VERSION 5.8 ;
BUSBITCHARS "[]" ;
DIVIDERCHAR "/" ;
UNITS
    DATABASE MICRONS 1000 ;
END UNITS

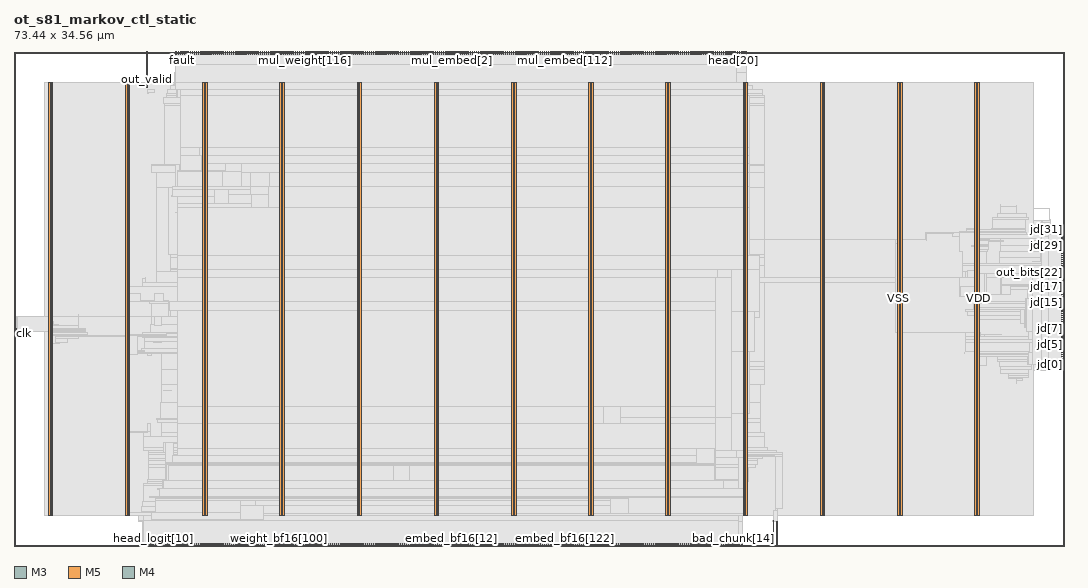
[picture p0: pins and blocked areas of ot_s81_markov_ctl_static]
MACRO ot_s81_markov_ctl_static
  FOREIGN ot_s81_markov_ctl_static 0 0 ;
  CLASS BLOCK ;
  SIZE 73.44 BY 34.56 ;
  PIN bad_chunk[0]
    DIRECTION INPUT ;
    USE SIGNAL ;
    PORT
      LAYER M3 ;
        RECT  49.32 0 49.338 0.144 ;
    END
  END bad_chunk[0]
  PIN bad_chunk[10]
    DIRECTION INPUT ;
    USE SIGNAL ;
    PORT
      LAYER M3 ;
        RECT  50.04 0 50.058 0.144 ;
    END
  END bad_chunk[10]
  PIN bad_chunk[11]
    DIRECTION INPUT ;
    USE SIGNAL ;
    PORT
      LAYER M5 ;
        RECT  50.064 0 50.088 0.192 ;
    END
  END bad_chunk[11]
  PIN bad_chunk[12]
    DIRECTION INPUT ;
    USE SIGNAL ;
    PORT
      LAYER M3 ;
        RECT  50.184 0 50.202 0.144 ;
    END
  END bad_chunk[12]
  PIN bad_chunk[13]
    DIRECTION INPUT ;
    USE SIGNAL ;
    PORT
      LAYER M5 ;
        RECT  50.208 0 50.232 0.192 ;
    END
  END bad_chunk[13]
  PIN bad_chunk[14]
    DIRECTION INPUT ;
    USE SIGNAL ;
    PORT
      LAYER M3 ;
        RECT  50.328 0 50.346 0.144 ;
    END
  END bad_chunk[14]
  PIN bad_chunk[15]
    DIRECTION INPUT ;
    USE SIGNAL ;
    PORT
      LAYER M5 ;
        RECT  50.352 0 50.376 0.192 ;
    END
  END bad_chunk[15]
  PIN bad_chunk[1]
    DIRECTION INPUT ;
    USE SIGNAL ;
    PORT
      LAYER M5 ;
        RECT  49.344 0 49.368 0.192 ;
    END
  END bad_chunk[1]
  PIN bad_chunk[2]
    DIRECTION INPUT ;
    USE SIGNAL ;
    PORT
      LAYER M3 ;
        RECT  49.464 0 49.482 0.144 ;
    END
  END bad_chunk[2]
  PIN bad_chunk[3]
    DIRECTION INPUT ;
    USE SIGNAL ;
    PORT
      LAYER M5 ;
        RECT  49.488 0 49.512 0.192 ;
    END
  END bad_chunk[3]
  PIN bad_chunk[4]
    DIRECTION INPUT ;
    USE SIGNAL ;
    PORT
      LAYER M3 ;
        RECT  49.608 0 49.626 0.144 ;
    END
  END bad_chunk[4]
  PIN bad_chunk[5]
    DIRECTION INPUT ;
    USE SIGNAL ;
    PORT
      LAYER M5 ;
        RECT  49.632 0 49.656 0.192 ;
    END
  END bad_chunk[5]
  PIN bad_chunk[6]
    DIRECTION INPUT ;
    USE SIGNAL ;
    PORT
      LAYER M3 ;
        RECT  49.752 0 49.77 0.144 ;
    END
  END bad_chunk[6]
  PIN bad_chunk[7]
    DIRECTION INPUT ;
    USE SIGNAL ;
    PORT
      LAYER M5 ;
        RECT  49.776 0 49.8 0.192 ;
    END
  END bad_chunk[7]
  PIN bad_chunk[8]
    DIRECTION INPUT ;
    USE SIGNAL ;
    PORT
      LAYER M3 ;
        RECT  49.896 0 49.914 0.144 ;
    END
  END bad_chunk[8]
  PIN bad_chunk[9]
    DIRECTION INPUT ;
    USE SIGNAL ;
    PORT
      LAYER M5 ;
        RECT  49.92 0 49.944 0.192 ;
    END
  END bad_chunk[9]
  PIN bad_tree[0]
    DIRECTION INPUT ;
    USE SIGNAL ;
    PORT
      LAYER M3 ;
        RECT  50.472 0 50.49 0.144 ;
    END
  END bad_tree[0]
  PIN bad_tree[1]
    DIRECTION INPUT ;
    USE SIGNAL ;
    PORT
      LAYER M5 ;
        RECT  50.496 0 50.52 0.192 ;
    END
  END bad_tree[1]
  PIN bad_tree[2]
    DIRECTION INPUT ;
    USE SIGNAL ;
    PORT
      LAYER M3 ;
        RECT  50.616 0 50.634 0.144 ;
    END
  END bad_tree[2]
  PIN bad_tree[3]
    DIRECTION INPUT ;
    USE SIGNAL ;
    PORT
      LAYER M5 ;
        RECT  50.64 0 50.664 0.192 ;
    END
  END bad_tree[3]
  PIN bad_tree[4]
    DIRECTION INPUT ;
    USE SIGNAL ;
    PORT
      LAYER M3 ;
        RECT  50.76 0 50.778 0.144 ;
    END
  END bad_tree[4]
  PIN clk
    DIRECTION INPUT ;
    USE SIGNAL ;
    PORT
      LAYER M4 ;
        RECT  0 14.88 0.192 14.904 ;
    END
  END clk
  PIN embed_bf16[0]
    DIRECTION INPUT ;
    USE SIGNAL ;
    PORT
      LAYER M3 ;
        RECT  29.736 0 29.754 0.144 ;
    END
  END embed_bf16[0]
  PIN embed_bf16[100]
    DIRECTION INPUT ;
    USE SIGNAL ;
    PORT
      LAYER M3 ;
        RECT  36.936 0 36.954 0.144 ;
    END
  END embed_bf16[100]
  PIN embed_bf16[101]
    DIRECTION INPUT ;
    USE SIGNAL ;
    PORT
      LAYER M5 ;
        RECT  36.96 0 36.984 0.192 ;
    END
  END embed_bf16[101]
  PIN embed_bf16[102]
    DIRECTION INPUT ;
    USE SIGNAL ;
    PORT
      LAYER M3 ;
        RECT  37.08 0 37.098 0.144 ;
    END
  END embed_bf16[102]
  PIN embed_bf16[103]
    DIRECTION INPUT ;
    USE SIGNAL ;
    PORT
      LAYER M5 ;
        RECT  37.104 0 37.128 0.192 ;
    END
  END embed_bf16[103]
  PIN embed_bf16[104]
    DIRECTION INPUT ;
    USE SIGNAL ;
    PORT
      LAYER M3 ;
        RECT  37.224 0 37.242 0.144 ;
    END
  END embed_bf16[104]
  PIN embed_bf16[105]
    DIRECTION INPUT ;
    USE SIGNAL ;
    PORT
      LAYER M5 ;
        RECT  37.248 0 37.272 0.192 ;
    END
  END embed_bf16[105]
  PIN embed_bf16[106]
    DIRECTION INPUT ;
    USE SIGNAL ;
    PORT
      LAYER M3 ;
        RECT  37.368 0 37.386 0.144 ;
    END
  END embed_bf16[106]
  PIN embed_bf16[107]
    DIRECTION INPUT ;
    USE SIGNAL ;
    PORT
      LAYER M5 ;
        RECT  37.392 0 37.416 0.192 ;
    END
  END embed_bf16[107]
  PIN embed_bf16[108]
    DIRECTION INPUT ;
    USE SIGNAL ;
    PORT
      LAYER M3 ;
        RECT  37.512 0 37.53 0.144 ;
    END
  END embed_bf16[108]
  PIN embed_bf16[109]
    DIRECTION INPUT ;
    USE SIGNAL ;
    PORT
      LAYER M5 ;
        RECT  37.536 0 37.56 0.192 ;
    END
  END embed_bf16[109]
  PIN embed_bf16[10]
    DIRECTION INPUT ;
    USE SIGNAL ;
    PORT
      LAYER M3 ;
        RECT  30.456 0 30.474 0.144 ;
    END
  END embed_bf16[10]
  PIN embed_bf16[110]
    DIRECTION INPUT ;
    USE SIGNAL ;
    PORT
      LAYER M3 ;
        RECT  37.656 0 37.674 0.144 ;
    END
  END embed_bf16[110]
  PIN embed_bf16[111]
    DIRECTION INPUT ;
    USE SIGNAL ;
    PORT
      LAYER M5 ;
        RECT  37.68 0 37.704 0.192 ;
    END
  END embed_bf16[111]
  PIN embed_bf16[112]
    DIRECTION INPUT ;
    USE SIGNAL ;
    PORT
      LAYER M3 ;
        RECT  37.8 0 37.818 0.144 ;
    END
  END embed_bf16[112]
  PIN embed_bf16[113]
    DIRECTION INPUT ;
    USE SIGNAL ;
    PORT
      LAYER M5 ;
        RECT  37.824 0 37.848 0.192 ;
    END
  END embed_bf16[113]
  PIN embed_bf16[114]
    DIRECTION INPUT ;
    USE SIGNAL ;
    PORT
      LAYER M3 ;
        RECT  37.944 0 37.962 0.144 ;
    END
  END embed_bf16[114]
  PIN embed_bf16[115]
    DIRECTION INPUT ;
    USE SIGNAL ;
    PORT
      LAYER M5 ;
        RECT  37.968 0 37.992 0.192 ;
    END
  END embed_bf16[115]
  PIN embed_bf16[116]
    DIRECTION INPUT ;
    USE SIGNAL ;
    PORT
      LAYER M3 ;
        RECT  38.088 0 38.106 0.144 ;
    END
  END embed_bf16[116]
  PIN embed_bf16[117]
    DIRECTION INPUT ;
    USE SIGNAL ;
    PORT
      LAYER M5 ;
        RECT  38.112 0 38.136 0.192 ;
    END
  END embed_bf16[117]
  PIN embed_bf16[118]
    DIRECTION INPUT ;
    USE SIGNAL ;
    PORT
      LAYER M3 ;
        RECT  38.232 0 38.25 0.144 ;
    END
  END embed_bf16[118]
  PIN embed_bf16[119]
    DIRECTION INPUT ;
    USE SIGNAL ;
    PORT
      LAYER M5 ;
        RECT  38.256 0 38.28 0.192 ;
    END
  END embed_bf16[119]
  PIN embed_bf16[11]
    DIRECTION INPUT ;
    USE SIGNAL ;
    PORT
      LAYER M5 ;
        RECT  30.48 0 30.504 0.192 ;
    END
  END embed_bf16[11]
  PIN embed_bf16[120]
    DIRECTION INPUT ;
    USE SIGNAL ;
    PORT
      LAYER M3 ;
        RECT  38.376 0 38.394 0.144 ;
    END
  END embed_bf16[120]
  PIN embed_bf16[121]
    DIRECTION INPUT ;
    USE SIGNAL ;
    PORT
      LAYER M5 ;
        RECT  38.4 0 38.424 0.192 ;
    END
  END embed_bf16[121]
  PIN embed_bf16[122]
    DIRECTION INPUT ;
    USE SIGNAL ;
    PORT
      LAYER M3 ;
        RECT  38.52 0 38.538 0.144 ;
    END
  END embed_bf16[122]
  PIN embed_bf16[123]
    DIRECTION INPUT ;
    USE SIGNAL ;
    PORT
      LAYER M5 ;
        RECT  38.544 0 38.568 0.192 ;
    END
  END embed_bf16[123]
  PIN embed_bf16[124]
    DIRECTION INPUT ;
    USE SIGNAL ;
    PORT
      LAYER M3 ;
        RECT  38.664 0 38.682 0.144 ;
    END
  END embed_bf16[124]
  PIN embed_bf16[125]
    DIRECTION INPUT ;
    USE SIGNAL ;
    PORT
      LAYER M5 ;
        RECT  38.688 0 38.712 0.192 ;
    END
  END embed_bf16[125]
  PIN embed_bf16[126]
    DIRECTION INPUT ;
    USE SIGNAL ;
    PORT
      LAYER M3 ;
        RECT  38.808 0 38.826 0.144 ;
    END
  END embed_bf16[126]
  PIN embed_bf16[127]
    DIRECTION INPUT ;
    USE SIGNAL ;
    PORT
      LAYER M5 ;
        RECT  38.832 0 38.856 0.192 ;
    END
  END embed_bf16[127]
  PIN embed_bf16[128]
    DIRECTION INPUT ;
    USE SIGNAL ;
    PORT
      LAYER M3 ;
        RECT  38.952 0 38.97 0.144 ;
    END
  END embed_bf16[128]
  PIN embed_bf16[129]
    DIRECTION INPUT ;
    USE SIGNAL ;
    PORT
      LAYER M5 ;
        RECT  38.976 0 39 0.192 ;
    END
  END embed_bf16[129]
  PIN embed_bf16[12]
    DIRECTION INPUT ;
    USE SIGNAL ;
    PORT
      LAYER M3 ;
        RECT  30.6 0 30.618 0.144 ;
    END
  END embed_bf16[12]
  PIN embed_bf16[130]
    DIRECTION INPUT ;
    USE SIGNAL ;
    PORT
      LAYER M3 ;
        RECT  39.096 0 39.114 0.144 ;
    END
  END embed_bf16[130]
  PIN embed_bf16[131]
    DIRECTION INPUT ;
    USE SIGNAL ;
    PORT
      LAYER M5 ;
        RECT  39.12 0 39.144 0.192 ;
    END
  END embed_bf16[131]
  PIN embed_bf16[132]
    DIRECTION INPUT ;
    USE SIGNAL ;
    PORT
      LAYER M3 ;
        RECT  39.24 0 39.258 0.144 ;
    END
  END embed_bf16[132]
  PIN embed_bf16[133]
    DIRECTION INPUT ;
    USE SIGNAL ;
    PORT
      LAYER M5 ;
        RECT  39.264 0 39.288 0.192 ;
    END
  END embed_bf16[133]
  PIN embed_bf16[134]
    DIRECTION INPUT ;
    USE SIGNAL ;
    PORT
      LAYER M3 ;
        RECT  39.384 0 39.402 0.144 ;
    END
  END embed_bf16[134]
  PIN embed_bf16[135]
    DIRECTION INPUT ;
    USE SIGNAL ;
    PORT
      LAYER M5 ;
        RECT  39.408 0 39.432 0.192 ;
    END
  END embed_bf16[135]
  PIN embed_bf16[136]
    DIRECTION INPUT ;
    USE SIGNAL ;
    PORT
      LAYER M3 ;
        RECT  39.528 0 39.546 0.144 ;
    END
  END embed_bf16[136]
  PIN embed_bf16[137]
    DIRECTION INPUT ;
    USE SIGNAL ;
    PORT
      LAYER M5 ;
        RECT  39.552 0 39.576 0.192 ;
    END
  END embed_bf16[137]
  PIN embed_bf16[138]
    DIRECTION INPUT ;
    USE SIGNAL ;
    PORT
      LAYER M3 ;
        RECT  39.672 0 39.69 0.144 ;
    END
  END embed_bf16[138]
  PIN embed_bf16[139]
    DIRECTION INPUT ;
    USE SIGNAL ;
    PORT
      LAYER M5 ;
        RECT  39.696 0 39.72 0.192 ;
    END
  END embed_bf16[139]
  PIN embed_bf16[13]
    DIRECTION INPUT ;
    USE SIGNAL ;
    PORT
      LAYER M5 ;
        RECT  30.624 0 30.648 0.192 ;
    END
  END embed_bf16[13]
  PIN embed_bf16[140]
    DIRECTION INPUT ;
    USE SIGNAL ;
    PORT
      LAYER M3 ;
        RECT  39.816 0 39.834 0.144 ;
    END
  END embed_bf16[140]
  PIN embed_bf16[141]
    DIRECTION INPUT ;
    USE SIGNAL ;
    PORT
      LAYER M5 ;
        RECT  39.84 0 39.864 0.192 ;
    END
  END embed_bf16[141]
  PIN embed_bf16[142]
    DIRECTION INPUT ;
    USE SIGNAL ;
    PORT
      LAYER M3 ;
        RECT  39.96 0 39.978 0.144 ;
    END
  END embed_bf16[142]
  PIN embed_bf16[143]
    DIRECTION INPUT ;
    USE SIGNAL ;
    PORT
      LAYER M5 ;
        RECT  39.984 0 40.008 0.192 ;
    END
  END embed_bf16[143]
  PIN embed_bf16[144]
    DIRECTION INPUT ;
    USE SIGNAL ;
    PORT
      LAYER M3 ;
        RECT  40.104 0 40.122 0.144 ;
    END
  END embed_bf16[144]
  PIN embed_bf16[145]
    DIRECTION INPUT ;
    USE SIGNAL ;
    PORT
      LAYER M5 ;
        RECT  40.128 0 40.152 0.192 ;
    END
  END embed_bf16[145]
  PIN embed_bf16[146]
    DIRECTION INPUT ;
    USE SIGNAL ;
    PORT
      LAYER M3 ;
        RECT  40.248 0 40.266 0.144 ;
    END
  END embed_bf16[146]
  PIN embed_bf16[147]
    DIRECTION INPUT ;
    USE SIGNAL ;
    PORT
      LAYER M5 ;
        RECT  40.272 0 40.296 0.192 ;
    END
  END embed_bf16[147]
  PIN embed_bf16[148]
    DIRECTION INPUT ;
    USE SIGNAL ;
    PORT
      LAYER M3 ;
        RECT  40.392 0 40.41 0.144 ;
    END
  END embed_bf16[148]
  PIN embed_bf16[149]
    DIRECTION INPUT ;
    USE SIGNAL ;
    PORT
      LAYER M5 ;
        RECT  40.416 0 40.44 0.192 ;
    END
  END embed_bf16[149]
  PIN embed_bf16[14]
    DIRECTION INPUT ;
    USE SIGNAL ;
    PORT
      LAYER M3 ;
        RECT  30.744 0 30.762 0.144 ;
    END
  END embed_bf16[14]
  PIN embed_bf16[150]
    DIRECTION INPUT ;
    USE SIGNAL ;
    PORT
      LAYER M3 ;
        RECT  40.536 0 40.554 0.144 ;
    END
  END embed_bf16[150]
  PIN embed_bf16[151]
    DIRECTION INPUT ;
    USE SIGNAL ;
    PORT
      LAYER M5 ;
        RECT  40.56 0 40.584 0.192 ;
    END
  END embed_bf16[151]
  PIN embed_bf16[152]
    DIRECTION INPUT ;
    USE SIGNAL ;
    PORT
      LAYER M3 ;
        RECT  40.68 0 40.698 0.144 ;
    END
  END embed_bf16[152]
  PIN embed_bf16[153]
    DIRECTION INPUT ;
    USE SIGNAL ;
    PORT
      LAYER M5 ;
        RECT  40.704 0 40.728 0.192 ;
    END
  END embed_bf16[153]
  PIN embed_bf16[154]
    DIRECTION INPUT ;
    USE SIGNAL ;
    PORT
      LAYER M3 ;
        RECT  40.824 0 40.842 0.144 ;
    END
  END embed_bf16[154]
  PIN embed_bf16[155]
    DIRECTION INPUT ;
    USE SIGNAL ;
    PORT
      LAYER M5 ;
        RECT  40.848 0 40.872 0.192 ;
    END
  END embed_bf16[155]
  PIN embed_bf16[156]
    DIRECTION INPUT ;
    USE SIGNAL ;
    PORT
      LAYER M3 ;
        RECT  40.968 0 40.986 0.144 ;
    END
  END embed_bf16[156]
  PIN embed_bf16[157]
    DIRECTION INPUT ;
    USE SIGNAL ;
    PORT
      LAYER M5 ;
        RECT  40.992 0 41.016 0.192 ;
    END
  END embed_bf16[157]
  PIN embed_bf16[158]
    DIRECTION INPUT ;
    USE SIGNAL ;
    PORT
      LAYER M3 ;
        RECT  41.112 0 41.13 0.144 ;
    END
  END embed_bf16[158]
  PIN embed_bf16[159]
    DIRECTION INPUT ;
    USE SIGNAL ;
    PORT
      LAYER M5 ;
        RECT  41.136 0 41.16 0.192 ;
    END
  END embed_bf16[159]
  PIN embed_bf16[15]
    DIRECTION INPUT ;
    USE SIGNAL ;
    PORT
      LAYER M5 ;
        RECT  30.768 0 30.792 0.192 ;
    END
  END embed_bf16[15]
  PIN embed_bf16[160]
    DIRECTION INPUT ;
    USE SIGNAL ;
    PORT
      LAYER M3 ;
        RECT  41.256 0 41.274 0.144 ;
    END
  END embed_bf16[160]
  PIN embed_bf16[161]
    DIRECTION INPUT ;
    USE SIGNAL ;
    PORT
      LAYER M5 ;
        RECT  41.28 0 41.304 0.192 ;
    END
  END embed_bf16[161]
  PIN embed_bf16[162]
    DIRECTION INPUT ;
    USE SIGNAL ;
    PORT
      LAYER M3 ;
        RECT  41.4 0 41.418 0.144 ;
    END
  END embed_bf16[162]
  PIN embed_bf16[163]
    DIRECTION INPUT ;
    USE SIGNAL ;
    PORT
      LAYER M5 ;
        RECT  41.424 0 41.448 0.192 ;
    END
  END embed_bf16[163]
  PIN embed_bf16[164]
    DIRECTION INPUT ;
    USE SIGNAL ;
    PORT
      LAYER M3 ;
        RECT  41.544 0 41.562 0.144 ;
    END
  END embed_bf16[164]
  PIN embed_bf16[165]
    DIRECTION INPUT ;
    USE SIGNAL ;
    PORT
      LAYER M5 ;
        RECT  41.568 0 41.592 0.192 ;
    END
  END embed_bf16[165]
  PIN embed_bf16[166]
    DIRECTION INPUT ;
    USE SIGNAL ;
    PORT
      LAYER M3 ;
        RECT  41.688 0 41.706 0.144 ;
    END
  END embed_bf16[166]
  PIN embed_bf16[167]
    DIRECTION INPUT ;
    USE SIGNAL ;
    PORT
      LAYER M5 ;
        RECT  41.712 0 41.736 0.192 ;
    END
  END embed_bf16[167]
  PIN embed_bf16[168]
    DIRECTION INPUT ;
    USE SIGNAL ;
    PORT
      LAYER M3 ;
        RECT  41.832 0 41.85 0.144 ;
    END
  END embed_bf16[168]
  PIN embed_bf16[169]
    DIRECTION INPUT ;
    USE SIGNAL ;
    PORT
      LAYER M5 ;
        RECT  41.856 0 41.88 0.192 ;
    END
  END embed_bf16[169]
  PIN embed_bf16[16]
    DIRECTION INPUT ;
    USE SIGNAL ;
    PORT
      LAYER M3 ;
        RECT  30.888 0 30.906 0.144 ;
    END
  END embed_bf16[16]
  PIN embed_bf16[170]
    DIRECTION INPUT ;
    USE SIGNAL ;
    PORT
      LAYER M3 ;
        RECT  41.976 0 41.994 0.144 ;
    END
  END embed_bf16[170]
  PIN embed_bf16[171]
    DIRECTION INPUT ;
    USE SIGNAL ;
    PORT
      LAYER M5 ;
        RECT  42 0 42.024 0.192 ;
    END
  END embed_bf16[171]
  PIN embed_bf16[172]
    DIRECTION INPUT ;
    USE SIGNAL ;
    PORT
      LAYER M3 ;
        RECT  42.12 0 42.138 0.144 ;
    END
  END embed_bf16[172]
  PIN embed_bf16[173]
    DIRECTION INPUT ;
    USE SIGNAL ;
    PORT
      LAYER M5 ;
        RECT  42.144 0 42.168 0.192 ;
    END
  END embed_bf16[173]
  PIN embed_bf16[174]
    DIRECTION INPUT ;
    USE SIGNAL ;
    PORT
      LAYER M3 ;
        RECT  42.264 0 42.282 0.144 ;
    END
  END embed_bf16[174]
  PIN embed_bf16[175]
    DIRECTION INPUT ;
    USE SIGNAL ;
    PORT
      LAYER M5 ;
        RECT  42.288 0 42.312 0.192 ;
    END
  END embed_bf16[175]
  PIN embed_bf16[176]
    DIRECTION INPUT ;
    USE SIGNAL ;
    PORT
      LAYER M3 ;
        RECT  42.408 0 42.426 0.144 ;
    END
  END embed_bf16[176]
  PIN embed_bf16[177]
    DIRECTION INPUT ;
    USE SIGNAL ;
    PORT
      LAYER M5 ;
        RECT  42.432 0 42.456 0.192 ;
    END
  END embed_bf16[177]
  PIN embed_bf16[178]
    DIRECTION INPUT ;
    USE SIGNAL ;
    PORT
      LAYER M3 ;
        RECT  42.552 0 42.57 0.144 ;
    END
  END embed_bf16[178]
  PIN embed_bf16[179]
    DIRECTION INPUT ;
    USE SIGNAL ;
    PORT
      LAYER M5 ;
        RECT  42.576 0 42.6 0.192 ;
    END
  END embed_bf16[179]
  PIN embed_bf16[17]
    DIRECTION INPUT ;
    USE SIGNAL ;
    PORT
      LAYER M5 ;
        RECT  30.912 0 30.936 0.192 ;
    END
  END embed_bf16[17]
  PIN embed_bf16[180]
    DIRECTION INPUT ;
    USE SIGNAL ;
    PORT
      LAYER M3 ;
        RECT  42.696 0 42.714 0.144 ;
    END
  END embed_bf16[180]
  PIN embed_bf16[181]
    DIRECTION INPUT ;
    USE SIGNAL ;
    PORT
      LAYER M5 ;
        RECT  42.72 0 42.744 0.192 ;
    END
  END embed_bf16[181]
  PIN embed_bf16[182]
    DIRECTION INPUT ;
    USE SIGNAL ;
    PORT
      LAYER M3 ;
        RECT  42.84 0 42.858 0.144 ;
    END
  END embed_bf16[182]
  PIN embed_bf16[183]
    DIRECTION INPUT ;
    USE SIGNAL ;
    PORT
      LAYER M5 ;
        RECT  42.864 0 42.888 0.192 ;
    END
  END embed_bf16[183]
  PIN embed_bf16[184]
    DIRECTION INPUT ;
    USE SIGNAL ;
    PORT
      LAYER M3 ;
        RECT  42.984 0 43.002 0.144 ;
    END
  END embed_bf16[184]
  PIN embed_bf16[185]
    DIRECTION INPUT ;
    USE SIGNAL ;
    PORT
      LAYER M5 ;
        RECT  43.008 0 43.032 0.192 ;
    END
  END embed_bf16[185]
  PIN embed_bf16[186]
    DIRECTION INPUT ;
    USE SIGNAL ;
    PORT
      LAYER M3 ;
        RECT  43.128 0 43.146 0.144 ;
    END
  END embed_bf16[186]
  PIN embed_bf16[187]
    DIRECTION INPUT ;
    USE SIGNAL ;
    PORT
      LAYER M5 ;
        RECT  43.152 0 43.176 0.192 ;
    END
  END embed_bf16[187]
  PIN embed_bf16[188]
    DIRECTION INPUT ;
    USE SIGNAL ;
    PORT
      LAYER M3 ;
        RECT  43.272 0 43.29 0.144 ;
    END
  END embed_bf16[188]
  PIN embed_bf16[189]
    DIRECTION INPUT ;
    USE SIGNAL ;
    PORT
      LAYER M5 ;
        RECT  43.296 0 43.32 0.192 ;
    END
  END embed_bf16[189]
  PIN embed_bf16[18]
    DIRECTION INPUT ;
    USE SIGNAL ;
    PORT
      LAYER M3 ;
        RECT  31.032 0 31.05 0.144 ;
    END
  END embed_bf16[18]
  PIN embed_bf16[190]
    DIRECTION INPUT ;
    USE SIGNAL ;
    PORT
      LAYER M3 ;
        RECT  43.416 0 43.434 0.144 ;
    END
  END embed_bf16[190]
  PIN embed_bf16[191]
    DIRECTION INPUT ;
    USE SIGNAL ;
    PORT
      LAYER M5 ;
        RECT  43.44 0 43.464 0.192 ;
    END
  END embed_bf16[191]
  PIN embed_bf16[192]
    DIRECTION INPUT ;
    USE SIGNAL ;
    PORT
      LAYER M3 ;
        RECT  43.56 0 43.578 0.144 ;
    END
  END embed_bf16[192]
  PIN embed_bf16[193]
    DIRECTION INPUT ;
    USE SIGNAL ;
    PORT
      LAYER M5 ;
        RECT  43.584 0 43.608 0.192 ;
    END
  END embed_bf16[193]
  PIN embed_bf16[194]
    DIRECTION INPUT ;
    USE SIGNAL ;
    PORT
      LAYER M3 ;
        RECT  43.704 0 43.722 0.144 ;
    END
  END embed_bf16[194]
  PIN embed_bf16[195]
    DIRECTION INPUT ;
    USE SIGNAL ;
    PORT
      LAYER M5 ;
        RECT  43.728 0 43.752 0.192 ;
    END
  END embed_bf16[195]
  PIN embed_bf16[196]
    DIRECTION INPUT ;
    USE SIGNAL ;
    PORT
      LAYER M3 ;
        RECT  43.848 0 43.866 0.144 ;
    END
  END embed_bf16[196]
  PIN embed_bf16[197]
    DIRECTION INPUT ;
    USE SIGNAL ;
    PORT
      LAYER M5 ;
        RECT  43.872 0 43.896 0.192 ;
    END
  END embed_bf16[197]
  PIN embed_bf16[198]
    DIRECTION INPUT ;
    USE SIGNAL ;
    PORT
      LAYER M3 ;
        RECT  43.992 0 44.01 0.144 ;
    END
  END embed_bf16[198]
  PIN embed_bf16[199]
    DIRECTION INPUT ;
    USE SIGNAL ;
    PORT
      LAYER M5 ;
        RECT  44.016 0 44.04 0.192 ;
    END
  END embed_bf16[199]
  PIN embed_bf16[19]
    DIRECTION INPUT ;
    USE SIGNAL ;
    PORT
      LAYER M5 ;
        RECT  31.056 0 31.08 0.192 ;
    END
  END embed_bf16[19]
  PIN embed_bf16[1]
    DIRECTION INPUT ;
    USE SIGNAL ;
    PORT
      LAYER M5 ;
        RECT  29.76 0 29.784 0.192 ;
    END
  END embed_bf16[1]
  PIN embed_bf16[200]
    DIRECTION INPUT ;
    USE SIGNAL ;
    PORT
      LAYER M3 ;
        RECT  44.136 0 44.154 0.144 ;
    END
  END embed_bf16[200]
  PIN embed_bf16[201]
    DIRECTION INPUT ;
    USE SIGNAL ;
    PORT
      LAYER M5 ;
        RECT  44.16 0 44.184 0.192 ;
    END
  END embed_bf16[201]
  PIN embed_bf16[202]
    DIRECTION INPUT ;
    USE SIGNAL ;
    PORT
      LAYER M3 ;
        RECT  44.28 0 44.298 0.144 ;
    END
  END embed_bf16[202]
  PIN embed_bf16[203]
    DIRECTION INPUT ;
    USE SIGNAL ;
    PORT
      LAYER M5 ;
        RECT  44.304 0 44.328 0.192 ;
    END
  END embed_bf16[203]
  PIN embed_bf16[204]
    DIRECTION INPUT ;
    USE SIGNAL ;
    PORT
      LAYER M3 ;
        RECT  44.424 0 44.442 0.144 ;
    END
  END embed_bf16[204]
  PIN embed_bf16[205]
    DIRECTION INPUT ;
    USE SIGNAL ;
    PORT
      LAYER M5 ;
        RECT  44.448 0 44.472 0.192 ;
    END
  END embed_bf16[205]
  PIN embed_bf16[206]
    DIRECTION INPUT ;
    USE SIGNAL ;
    PORT
      LAYER M3 ;
        RECT  44.568 0 44.586 0.144 ;
    END
  END embed_bf16[206]
  PIN embed_bf16[207]
    DIRECTION INPUT ;
    USE SIGNAL ;
    PORT
      LAYER M5 ;
        RECT  44.592 0 44.616 0.192 ;
    END
  END embed_bf16[207]
  PIN embed_bf16[208]
    DIRECTION INPUT ;
    USE SIGNAL ;
    PORT
      LAYER M3 ;
        RECT  44.712 0 44.73 0.144 ;
    END
  END embed_bf16[208]
  PIN embed_bf16[209]
    DIRECTION INPUT ;
    USE SIGNAL ;
    PORT
      LAYER M5 ;
        RECT  44.736 0 44.76 0.192 ;
    END
  END embed_bf16[209]
  PIN embed_bf16[20]
    DIRECTION INPUT ;
    USE SIGNAL ;
    PORT
      LAYER M3 ;
        RECT  31.176 0 31.194 0.144 ;
    END
  END embed_bf16[20]
  PIN embed_bf16[210]
    DIRECTION INPUT ;
    USE SIGNAL ;
    PORT
      LAYER M3 ;
        RECT  44.856 0 44.874 0.144 ;
    END
  END embed_bf16[210]
  PIN embed_bf16[211]
    DIRECTION INPUT ;
    USE SIGNAL ;
    PORT
      LAYER M5 ;
        RECT  44.88 0 44.904 0.192 ;
    END
  END embed_bf16[211]
  PIN embed_bf16[212]
    DIRECTION INPUT ;
    USE SIGNAL ;
    PORT
      LAYER M3 ;
        RECT  45 0 45.018 0.144 ;
    END
  END embed_bf16[212]
  PIN embed_bf16[213]
    DIRECTION INPUT ;
    USE SIGNAL ;
    PORT
      LAYER M5 ;
        RECT  45.024 0 45.048 0.192 ;
    END
  END embed_bf16[213]
  PIN embed_bf16[214]
    DIRECTION INPUT ;
    USE SIGNAL ;
    PORT
      LAYER M3 ;
        RECT  45.144 0 45.162 0.144 ;
    END
  END embed_bf16[214]
  PIN embed_bf16[215]
    DIRECTION INPUT ;
    USE SIGNAL ;
    PORT
      LAYER M5 ;
        RECT  45.168 0 45.192 0.192 ;
    END
  END embed_bf16[215]
  PIN embed_bf16[216]
    DIRECTION INPUT ;
    USE SIGNAL ;
    PORT
      LAYER M3 ;
        RECT  45.288 0 45.306 0.144 ;
    END
  END embed_bf16[216]
  PIN embed_bf16[217]
    DIRECTION INPUT ;
    USE SIGNAL ;
    PORT
      LAYER M5 ;
        RECT  45.312 0 45.336 0.192 ;
    END
  END embed_bf16[217]
  PIN embed_bf16[218]
    DIRECTION INPUT ;
    USE SIGNAL ;
    PORT
      LAYER M3 ;
        RECT  45.432 0 45.45 0.144 ;
    END
  END embed_bf16[218]
  PIN embed_bf16[219]
    DIRECTION INPUT ;
    USE SIGNAL ;
    PORT
      LAYER M5 ;
        RECT  45.456 0 45.48 0.192 ;
    END
  END embed_bf16[219]
  PIN embed_bf16[21]
    DIRECTION INPUT ;
    USE SIGNAL ;
    PORT
      LAYER M5 ;
        RECT  31.2 0 31.224 0.192 ;
    END
  END embed_bf16[21]
  PIN embed_bf16[220]
    DIRECTION INPUT ;
    USE SIGNAL ;
    PORT
      LAYER M3 ;
        RECT  45.576 0 45.594 0.144 ;
    END
  END embed_bf16[220]
  PIN embed_bf16[221]
    DIRECTION INPUT ;
    USE SIGNAL ;
    PORT
      LAYER M5 ;
        RECT  45.6 0 45.624 0.192 ;
    END
  END embed_bf16[221]
  PIN embed_bf16[222]
    DIRECTION INPUT ;
    USE SIGNAL ;
    PORT
      LAYER M3 ;
        RECT  45.72 0 45.738 0.144 ;
    END
  END embed_bf16[222]
  PIN embed_bf16[223]
    DIRECTION INPUT ;
    USE SIGNAL ;
    PORT
      LAYER M5 ;
        RECT  45.744 0 45.768 0.192 ;
    END
  END embed_bf16[223]
  PIN embed_bf16[224]
    DIRECTION INPUT ;
    USE SIGNAL ;
    PORT
      LAYER M3 ;
        RECT  45.864 0 45.882 0.144 ;
    END
  END embed_bf16[224]
  PIN embed_bf16[225]
    DIRECTION INPUT ;
    USE SIGNAL ;
    PORT
      LAYER M5 ;
        RECT  45.888 0 45.912 0.192 ;
    END
  END embed_bf16[225]
  PIN embed_bf16[226]
    DIRECTION INPUT ;
    USE SIGNAL ;
    PORT
      LAYER M3 ;
        RECT  46.008 0 46.026 0.144 ;
    END
  END embed_bf16[226]
  PIN embed_bf16[227]
    DIRECTION INPUT ;
    USE SIGNAL ;
    PORT
      LAYER M5 ;
        RECT  46.032 0 46.056 0.192 ;
    END
  END embed_bf16[227]
  PIN embed_bf16[228]
    DIRECTION INPUT ;
    USE SIGNAL ;
    PORT
      LAYER M3 ;
        RECT  46.152 0 46.17 0.144 ;
    END
  END embed_bf16[228]
  PIN embed_bf16[229]
    DIRECTION INPUT ;
    USE SIGNAL ;
    PORT
      LAYER M5 ;
        RECT  46.176 0 46.2 0.192 ;
    END
  END embed_bf16[229]
  PIN embed_bf16[22]
    DIRECTION INPUT ;
    USE SIGNAL ;
    PORT
      LAYER M3 ;
        RECT  31.32 0 31.338 0.144 ;
    END
  END embed_bf16[22]
  PIN embed_bf16[230]
    DIRECTION INPUT ;
    USE SIGNAL ;
    PORT
      LAYER M3 ;
        RECT  46.296 0 46.314 0.144 ;
    END
  END embed_bf16[230]
  PIN embed_bf16[231]
    DIRECTION INPUT ;
    USE SIGNAL ;
    PORT
      LAYER M5 ;
        RECT  46.32 0 46.344 0.192 ;
    END
  END embed_bf16[231]
  PIN embed_bf16[232]
    DIRECTION INPUT ;
    USE SIGNAL ;
    PORT
      LAYER M3 ;
        RECT  46.44 0 46.458 0.144 ;
    END
  END embed_bf16[232]
  PIN embed_bf16[233]
    DIRECTION INPUT ;
    USE SIGNAL ;
    PORT
      LAYER M5 ;
        RECT  46.464 0 46.488 0.192 ;
    END
  END embed_bf16[233]
  PIN embed_bf16[234]
    DIRECTION INPUT ;
    USE SIGNAL ;
    PORT
      LAYER M3 ;
        RECT  46.584 0 46.602 0.144 ;
    END
  END embed_bf16[234]
  PIN embed_bf16[235]
    DIRECTION INPUT ;
    USE SIGNAL ;
    PORT
      LAYER M5 ;
        RECT  46.608 0 46.632 0.192 ;
    END
  END embed_bf16[235]
  PIN embed_bf16[236]
    DIRECTION INPUT ;
    USE SIGNAL ;
    PORT
      LAYER M3 ;
        RECT  46.728 0 46.746 0.144 ;
    END
  END embed_bf16[236]
  PIN embed_bf16[237]
    DIRECTION INPUT ;
    USE SIGNAL ;
    PORT
      LAYER M5 ;
        RECT  46.752 0 46.776 0.192 ;
    END
  END embed_bf16[237]
  PIN embed_bf16[238]
    DIRECTION INPUT ;
    USE SIGNAL ;
    PORT
      LAYER M3 ;
        RECT  46.872 0 46.89 0.144 ;
    END
  END embed_bf16[238]
  PIN embed_bf16[239]
    DIRECTION INPUT ;
    USE SIGNAL ;
    PORT
      LAYER M5 ;
        RECT  46.896 0 46.92 0.192 ;
    END
  END embed_bf16[239]
  PIN embed_bf16[23]
    DIRECTION INPUT ;
    USE SIGNAL ;
    PORT
      LAYER M5 ;
        RECT  31.344 0 31.368 0.192 ;
    END
  END embed_bf16[23]
  PIN embed_bf16[240]
    DIRECTION INPUT ;
    USE SIGNAL ;
    PORT
      LAYER M3 ;
        RECT  47.016 0 47.034 0.144 ;
    END
  END embed_bf16[240]
  PIN embed_bf16[241]
    DIRECTION INPUT ;
    USE SIGNAL ;
    PORT
      LAYER M5 ;
        RECT  47.04 0 47.064 0.192 ;
    END
  END embed_bf16[241]
  PIN embed_bf16[242]
    DIRECTION INPUT ;
    USE SIGNAL ;
    PORT
      LAYER M3 ;
        RECT  47.16 0 47.178 0.144 ;
    END
  END embed_bf16[242]
  PIN embed_bf16[243]
    DIRECTION INPUT ;
    USE SIGNAL ;
    PORT
      LAYER M5 ;
        RECT  47.184 0 47.208 0.192 ;
    END
  END embed_bf16[243]
  PIN embed_bf16[244]
    DIRECTION INPUT ;
    USE SIGNAL ;
    PORT
      LAYER M3 ;
        RECT  47.304 0 47.322 0.144 ;
    END
  END embed_bf16[244]
  PIN embed_bf16[245]
    DIRECTION INPUT ;
    USE SIGNAL ;
    PORT
      LAYER M5 ;
        RECT  47.328 0 47.352 0.192 ;
    END
  END embed_bf16[245]
  PIN embed_bf16[246]
    DIRECTION INPUT ;
    USE SIGNAL ;
    PORT
      LAYER M3 ;
        RECT  47.448 0 47.466 0.144 ;
    END
  END embed_bf16[246]
  PIN embed_bf16[247]
    DIRECTION INPUT ;
    USE SIGNAL ;
    PORT
      LAYER M5 ;
        RECT  47.472 0 47.496 0.192 ;
    END
  END embed_bf16[247]
  PIN embed_bf16[248]
    DIRECTION INPUT ;
    USE SIGNAL ;
    PORT
      LAYER M3 ;
        RECT  47.592 0 47.61 0.144 ;
    END
  END embed_bf16[248]
  PIN embed_bf16[249]
    DIRECTION INPUT ;
    USE SIGNAL ;
    PORT
      LAYER M5 ;
        RECT  47.616 0 47.64 0.192 ;
    END
  END embed_bf16[249]
  PIN embed_bf16[24]
    DIRECTION INPUT ;
    USE SIGNAL ;
    PORT
      LAYER M3 ;
        RECT  31.464 0 31.482 0.144 ;
    END
  END embed_bf16[24]
  PIN embed_bf16[250]
    DIRECTION INPUT ;
    USE SIGNAL ;
    PORT
      LAYER M3 ;
        RECT  47.736 0 47.754 0.144 ;
    END
  END embed_bf16[250]
  PIN embed_bf16[251]
    DIRECTION INPUT ;
    USE SIGNAL ;
    PORT
      LAYER M5 ;
        RECT  47.76 0 47.784 0.192 ;
    END
  END embed_bf16[251]
  PIN embed_bf16[252]
    DIRECTION INPUT ;
    USE SIGNAL ;
    PORT
      LAYER M3 ;
        RECT  47.88 0 47.898 0.144 ;
    END
  END embed_bf16[252]
  PIN embed_bf16[253]
    DIRECTION INPUT ;
    USE SIGNAL ;
    PORT
      LAYER M5 ;
        RECT  47.904 0 47.928 0.192 ;
    END
  END embed_bf16[253]
  PIN embed_bf16[254]
    DIRECTION INPUT ;
    USE SIGNAL ;
    PORT
      LAYER M3 ;
        RECT  48.024 0 48.042 0.144 ;
    END
  END embed_bf16[254]
  PIN embed_bf16[255]
    DIRECTION INPUT ;
    USE SIGNAL ;
    PORT
      LAYER M5 ;
        RECT  48.048 0 48.072 0.192 ;
    END
  END embed_bf16[255]
  PIN embed_bf16[25]
    DIRECTION INPUT ;
    USE SIGNAL ;
    PORT
      LAYER M5 ;
        RECT  31.488 0 31.512 0.192 ;
    END
  END embed_bf16[25]
  PIN embed_bf16[26]
    DIRECTION INPUT ;
    USE SIGNAL ;
    PORT
      LAYER M3 ;
        RECT  31.608 0 31.626 0.144 ;
    END
  END embed_bf16[26]
  PIN embed_bf16[27]
    DIRECTION INPUT ;
    USE SIGNAL ;
    PORT
      LAYER M5 ;
        RECT  31.632 0 31.656 0.192 ;
    END
  END embed_bf16[27]
  PIN embed_bf16[28]
    DIRECTION INPUT ;
    USE SIGNAL ;
    PORT
      LAYER M3 ;
        RECT  31.752 0 31.77 0.144 ;
    END
  END embed_bf16[28]
  PIN embed_bf16[29]
    DIRECTION INPUT ;
    USE SIGNAL ;
    PORT
      LAYER M5 ;
        RECT  31.776 0 31.8 0.192 ;
    END
  END embed_bf16[29]
  PIN embed_bf16[2]
    DIRECTION INPUT ;
    USE SIGNAL ;
    PORT
      LAYER M3 ;
        RECT  29.88 0 29.898 0.144 ;
    END
  END embed_bf16[2]
  PIN embed_bf16[30]
    DIRECTION INPUT ;
    USE SIGNAL ;
    PORT
      LAYER M3 ;
        RECT  31.896 0 31.914 0.144 ;
    END
  END embed_bf16[30]
  PIN embed_bf16[31]
    DIRECTION INPUT ;
    USE SIGNAL ;
    PORT
      LAYER M5 ;
        RECT  31.92 0 31.944 0.192 ;
    END
  END embed_bf16[31]
  PIN embed_bf16[32]
    DIRECTION INPUT ;
    USE SIGNAL ;
    PORT
      LAYER M3 ;
        RECT  32.04 0 32.058 0.144 ;
    END
  END embed_bf16[32]
  PIN embed_bf16[33]
    DIRECTION INPUT ;
    USE SIGNAL ;
    PORT
      LAYER M5 ;
        RECT  32.064 0 32.088 0.192 ;
    END
  END embed_bf16[33]
  PIN embed_bf16[34]
    DIRECTION INPUT ;
    USE SIGNAL ;
    PORT
      LAYER M3 ;
        RECT  32.184 0 32.202 0.144 ;
    END
  END embed_bf16[34]
  PIN embed_bf16[35]
    DIRECTION INPUT ;
    USE SIGNAL ;
    PORT
      LAYER M5 ;
        RECT  32.208 0 32.232 0.192 ;
    END
  END embed_bf16[35]
  PIN embed_bf16[36]
    DIRECTION INPUT ;
    USE SIGNAL ;
    PORT
      LAYER M3 ;
        RECT  32.328 0 32.346 0.144 ;
    END
  END embed_bf16[36]
  PIN embed_bf16[37]
    DIRECTION INPUT ;
    USE SIGNAL ;
    PORT
      LAYER M5 ;
        RECT  32.352 0 32.376 0.192 ;
    END
  END embed_bf16[37]
  PIN embed_bf16[38]
    DIRECTION INPUT ;
    USE SIGNAL ;
    PORT
      LAYER M3 ;
        RECT  32.472 0 32.49 0.144 ;
    END
  END embed_bf16[38]
  PIN embed_bf16[39]
    DIRECTION INPUT ;
    USE SIGNAL ;
    PORT
      LAYER M5 ;
        RECT  32.496 0 32.52 0.192 ;
    END
  END embed_bf16[39]
  PIN embed_bf16[3]
    DIRECTION INPUT ;
    USE SIGNAL ;
    PORT
      LAYER M5 ;
        RECT  29.904 0 29.928 0.192 ;
    END
  END embed_bf16[3]
  PIN embed_bf16[40]
    DIRECTION INPUT ;
    USE SIGNAL ;
    PORT
      LAYER M3 ;
        RECT  32.616 0 32.634 0.144 ;
    END
  END embed_bf16[40]
  PIN embed_bf16[41]
    DIRECTION INPUT ;
    USE SIGNAL ;
    PORT
      LAYER M5 ;
        RECT  32.64 0 32.664 0.192 ;
    END
  END embed_bf16[41]
  PIN embed_bf16[42]
    DIRECTION INPUT ;
    USE SIGNAL ;
    PORT
      LAYER M3 ;
        RECT  32.76 0 32.778 0.144 ;
    END
  END embed_bf16[42]
  PIN embed_bf16[43]
    DIRECTION INPUT ;
    USE SIGNAL ;
    PORT
      LAYER M5 ;
        RECT  32.784 0 32.808 0.192 ;
    END
  END embed_bf16[43]
  PIN embed_bf16[44]
    DIRECTION INPUT ;
    USE SIGNAL ;
    PORT
      LAYER M3 ;
        RECT  32.904 0 32.922 0.144 ;
    END
  END embed_bf16[44]
  PIN embed_bf16[45]
    DIRECTION INPUT ;
    USE SIGNAL ;
    PORT
      LAYER M5 ;
        RECT  32.928 0 32.952 0.192 ;
    END
  END embed_bf16[45]
  PIN embed_bf16[46]
    DIRECTION INPUT ;
    USE SIGNAL ;
    PORT
      LAYER M3 ;
        RECT  33.048 0 33.066 0.144 ;
    END
  END embed_bf16[46]
  PIN embed_bf16[47]
    DIRECTION INPUT ;
    USE SIGNAL ;
    PORT
      LAYER M5 ;
        RECT  33.072 0 33.096 0.192 ;
    END
  END embed_bf16[47]
  PIN embed_bf16[48]
    DIRECTION INPUT ;
    USE SIGNAL ;
    PORT
      LAYER M3 ;
        RECT  33.192 0 33.21 0.144 ;
    END
  END embed_bf16[48]
  PIN embed_bf16[49]
    DIRECTION INPUT ;
    USE SIGNAL ;
    PORT
      LAYER M5 ;
        RECT  33.216 0 33.24 0.192 ;
    END
  END embed_bf16[49]
  PIN embed_bf16[4]
    DIRECTION INPUT ;
    USE SIGNAL ;
    PORT
      LAYER M3 ;
        RECT  30.024 0 30.042 0.144 ;
    END
  END embed_bf16[4]
  PIN embed_bf16[50]
    DIRECTION INPUT ;
    USE SIGNAL ;
    PORT
      LAYER M3 ;
        RECT  33.336 0 33.354 0.144 ;
    END
  END embed_bf16[50]
  PIN embed_bf16[51]
    DIRECTION INPUT ;
    USE SIGNAL ;
    PORT
      LAYER M5 ;
        RECT  33.36 0 33.384 0.192 ;
    END
  END embed_bf16[51]
  PIN embed_bf16[52]
    DIRECTION INPUT ;
    USE SIGNAL ;
    PORT
      LAYER M3 ;
        RECT  33.48 0 33.498 0.144 ;
    END
  END embed_bf16[52]
  PIN embed_bf16[53]
    DIRECTION INPUT ;
    USE SIGNAL ;
    PORT
      LAYER M5 ;
        RECT  33.504 0 33.528 0.192 ;
    END
  END embed_bf16[53]
  PIN embed_bf16[54]
    DIRECTION INPUT ;
    USE SIGNAL ;
    PORT
      LAYER M3 ;
        RECT  33.624 0 33.642 0.144 ;
    END
  END embed_bf16[54]
  PIN embed_bf16[55]
    DIRECTION INPUT ;
    USE SIGNAL ;
    PORT
      LAYER M5 ;
        RECT  33.648 0 33.672 0.192 ;
    END
  END embed_bf16[55]
  PIN embed_bf16[56]
    DIRECTION INPUT ;
    USE SIGNAL ;
    PORT
      LAYER M3 ;
        RECT  33.768 0 33.786 0.144 ;
    END
  END embed_bf16[56]
  PIN embed_bf16[57]
    DIRECTION INPUT ;
    USE SIGNAL ;
    PORT
      LAYER M5 ;
        RECT  33.792 0 33.816 0.192 ;
    END
  END embed_bf16[57]
  PIN embed_bf16[58]
    DIRECTION INPUT ;
    USE SIGNAL ;
    PORT
      LAYER M3 ;
        RECT  33.912 0 33.93 0.144 ;
    END
  END embed_bf16[58]
  PIN embed_bf16[59]
    DIRECTION INPUT ;
    USE SIGNAL ;
    PORT
      LAYER M5 ;
        RECT  33.936 0 33.96 0.192 ;
    END
  END embed_bf16[59]
  PIN embed_bf16[5]
    DIRECTION INPUT ;
    USE SIGNAL ;
    PORT
      LAYER M5 ;
        RECT  30.048 0 30.072 0.192 ;
    END
  END embed_bf16[5]
  PIN embed_bf16[60]
    DIRECTION INPUT ;
    USE SIGNAL ;
    PORT
      LAYER M3 ;
        RECT  34.056 0 34.074 0.144 ;
    END
  END embed_bf16[60]
  PIN embed_bf16[61]
    DIRECTION INPUT ;
    USE SIGNAL ;
    PORT
      LAYER M5 ;
        RECT  34.08 0 34.104 0.192 ;
    END
  END embed_bf16[61]
  PIN embed_bf16[62]
    DIRECTION INPUT ;
    USE SIGNAL ;
    PORT
      LAYER M3 ;
        RECT  34.2 0 34.218 0.144 ;
    END
  END embed_bf16[62]
  PIN embed_bf16[63]
    DIRECTION INPUT ;
    USE SIGNAL ;
    PORT
      LAYER M5 ;
        RECT  34.224 0 34.248 0.192 ;
    END
  END embed_bf16[63]
  PIN embed_bf16[64]
    DIRECTION INPUT ;
    USE SIGNAL ;
    PORT
      LAYER M3 ;
        RECT  34.344 0 34.362 0.144 ;
    END
  END embed_bf16[64]
  PIN embed_bf16[65]
    DIRECTION INPUT ;
    USE SIGNAL ;
    PORT
      LAYER M5 ;
        RECT  34.368 0 34.392 0.192 ;
    END
  END embed_bf16[65]
  PIN embed_bf16[66]
    DIRECTION INPUT ;
    USE SIGNAL ;
    PORT
      LAYER M3 ;
        RECT  34.488 0 34.506 0.144 ;
    END
  END embed_bf16[66]
  PIN embed_bf16[67]
    DIRECTION INPUT ;
    USE SIGNAL ;
    PORT
      LAYER M5 ;
        RECT  34.512 0 34.536 0.192 ;
    END
  END embed_bf16[67]
  PIN embed_bf16[68]
    DIRECTION INPUT ;
    USE SIGNAL ;
    PORT
      LAYER M3 ;
        RECT  34.632 0 34.65 0.144 ;
    END
  END embed_bf16[68]
  PIN embed_bf16[69]
    DIRECTION INPUT ;
    USE SIGNAL ;
    PORT
      LAYER M5 ;
        RECT  34.656 0 34.68 0.192 ;
    END
  END embed_bf16[69]
  PIN embed_bf16[6]
    DIRECTION INPUT ;
    USE SIGNAL ;
    PORT
      LAYER M3 ;
        RECT  30.168 0 30.186 0.144 ;
    END
  END embed_bf16[6]
  PIN embed_bf16[70]
    DIRECTION INPUT ;
    USE SIGNAL ;
    PORT
      LAYER M3 ;
        RECT  34.776 0 34.794 0.144 ;
    END
  END embed_bf16[70]
  PIN embed_bf16[71]
    DIRECTION INPUT ;
    USE SIGNAL ;
    PORT
      LAYER M5 ;
        RECT  34.8 0 34.824 0.192 ;
    END
  END embed_bf16[71]
  PIN embed_bf16[72]
    DIRECTION INPUT ;
    USE SIGNAL ;
    PORT
      LAYER M3 ;
        RECT  34.92 0 34.938 0.144 ;
    END
  END embed_bf16[72]
  PIN embed_bf16[73]
    DIRECTION INPUT ;
    USE SIGNAL ;
    PORT
      LAYER M5 ;
        RECT  34.944 0 34.968 0.192 ;
    END
  END embed_bf16[73]
  PIN embed_bf16[74]
    DIRECTION INPUT ;
    USE SIGNAL ;
    PORT
      LAYER M3 ;
        RECT  35.064 0 35.082 0.144 ;
    END
  END embed_bf16[74]
  PIN embed_bf16[75]
    DIRECTION INPUT ;
    USE SIGNAL ;
    PORT
      LAYER M5 ;
        RECT  35.088 0 35.112 0.192 ;
    END
  END embed_bf16[75]
  PIN embed_bf16[76]
    DIRECTION INPUT ;
    USE SIGNAL ;
    PORT
      LAYER M3 ;
        RECT  35.208 0 35.226 0.144 ;
    END
  END embed_bf16[76]
  PIN embed_bf16[77]
    DIRECTION INPUT ;
    USE SIGNAL ;
    PORT
      LAYER M5 ;
        RECT  35.232 0 35.256 0.192 ;
    END
  END embed_bf16[77]
  PIN embed_bf16[78]
    DIRECTION INPUT ;
    USE SIGNAL ;
    PORT
      LAYER M3 ;
        RECT  35.352 0 35.37 0.144 ;
    END
  END embed_bf16[78]
  PIN embed_bf16[79]
    DIRECTION INPUT ;
    USE SIGNAL ;
    PORT
      LAYER M5 ;
        RECT  35.376 0 35.4 0.192 ;
    END
  END embed_bf16[79]
  PIN embed_bf16[7]
    DIRECTION INPUT ;
    USE SIGNAL ;
    PORT
      LAYER M5 ;
        RECT  30.192 0 30.216 0.192 ;
    END
  END embed_bf16[7]
  PIN embed_bf16[80]
    DIRECTION INPUT ;
    USE SIGNAL ;
    PORT
      LAYER M3 ;
        RECT  35.496 0 35.514 0.144 ;
    END
  END embed_bf16[80]
  PIN embed_bf16[81]
    DIRECTION INPUT ;
    USE SIGNAL ;
    PORT
      LAYER M5 ;
        RECT  35.52 0 35.544 0.192 ;
    END
  END embed_bf16[81]
  PIN embed_bf16[82]
    DIRECTION INPUT ;
    USE SIGNAL ;
    PORT
      LAYER M3 ;
        RECT  35.64 0 35.658 0.144 ;
    END
  END embed_bf16[82]
  PIN embed_bf16[83]
    DIRECTION INPUT ;
    USE SIGNAL ;
    PORT
      LAYER M5 ;
        RECT  35.664 0 35.688 0.192 ;
    END
  END embed_bf16[83]
  PIN embed_bf16[84]
    DIRECTION INPUT ;
    USE SIGNAL ;
    PORT
      LAYER M3 ;
        RECT  35.784 0 35.802 0.144 ;
    END
  END embed_bf16[84]
  PIN embed_bf16[85]
    DIRECTION INPUT ;
    USE SIGNAL ;
    PORT
      LAYER M5 ;
        RECT  35.808 0 35.832 0.192 ;
    END
  END embed_bf16[85]
  PIN embed_bf16[86]
    DIRECTION INPUT ;
    USE SIGNAL ;
    PORT
      LAYER M3 ;
        RECT  35.928 0 35.946 0.144 ;
    END
  END embed_bf16[86]
  PIN embed_bf16[87]
    DIRECTION INPUT ;
    USE SIGNAL ;
    PORT
      LAYER M5 ;
        RECT  35.952 0 35.976 0.192 ;
    END
  END embed_bf16[87]
  PIN embed_bf16[88]
    DIRECTION INPUT ;
    USE SIGNAL ;
    PORT
      LAYER M3 ;
        RECT  36.072 0 36.09 0.144 ;
    END
  END embed_bf16[88]
  PIN embed_bf16[89]
    DIRECTION INPUT ;
    USE SIGNAL ;
    PORT
      LAYER M5 ;
        RECT  36.096 0 36.12 0.192 ;
    END
  END embed_bf16[89]
  PIN embed_bf16[8]
    DIRECTION INPUT ;
    USE SIGNAL ;
    PORT
      LAYER M3 ;
        RECT  30.312 0 30.33 0.144 ;
    END
  END embed_bf16[8]
  PIN embed_bf16[90]
    DIRECTION INPUT ;
    USE SIGNAL ;
    PORT
      LAYER M3 ;
        RECT  36.216 0 36.234 0.144 ;
    END
  END embed_bf16[90]
  PIN embed_bf16[91]
    DIRECTION INPUT ;
    USE SIGNAL ;
    PORT
      LAYER M5 ;
        RECT  36.24 0 36.264 0.192 ;
    END
  END embed_bf16[91]
  PIN embed_bf16[92]
    DIRECTION INPUT ;
    USE SIGNAL ;
    PORT
      LAYER M3 ;
        RECT  36.36 0 36.378 0.144 ;
    END
  END embed_bf16[92]
  PIN embed_bf16[93]
    DIRECTION INPUT ;
    USE SIGNAL ;
    PORT
      LAYER M5 ;
        RECT  36.384 0 36.408 0.192 ;
    END
  END embed_bf16[93]
  PIN embed_bf16[94]
    DIRECTION INPUT ;
    USE SIGNAL ;
    PORT
      LAYER M3 ;
        RECT  36.504 0 36.522 0.144 ;
    END
  END embed_bf16[94]
  PIN embed_bf16[95]
    DIRECTION INPUT ;
    USE SIGNAL ;
    PORT
      LAYER M5 ;
        RECT  36.528 0 36.552 0.192 ;
    END
  END embed_bf16[95]
  PIN embed_bf16[96]
    DIRECTION INPUT ;
    USE SIGNAL ;
    PORT
      LAYER M3 ;
        RECT  36.648 0 36.666 0.144 ;
    END
  END embed_bf16[96]
  PIN embed_bf16[97]
    DIRECTION INPUT ;
    USE SIGNAL ;
    PORT
      LAYER M5 ;
        RECT  36.672 0 36.696 0.192 ;
    END
  END embed_bf16[97]
  PIN embed_bf16[98]
    DIRECTION INPUT ;
    USE SIGNAL ;
    PORT
      LAYER M3 ;
        RECT  36.792 0 36.81 0.144 ;
    END
  END embed_bf16[98]
  PIN embed_bf16[99]
    DIRECTION INPUT ;
    USE SIGNAL ;
    PORT
      LAYER M5 ;
        RECT  36.816 0 36.84 0.192 ;
    END
  END embed_bf16[99]
  PIN embed_bf16[9]
    DIRECTION INPUT ;
    USE SIGNAL ;
    PORT
      LAYER M5 ;
        RECT  30.336 0 30.36 0.192 ;
    END
  END embed_bf16[9]
  PIN fault
    DIRECTION OUTPUT ;
    USE SIGNAL ;
    PORT
      LAYER M3 ;
        RECT  11.736 34.416 11.754 34.56 ;
    END
  END fault
  PIN head[0]
    DIRECTION OUTPUT ;
    USE SIGNAL ;
    PORT
      LAYER M3 ;
        RECT  48.888 34.416 48.906 34.56 ;
    END
  END head[0]
  PIN head[10]
    DIRECTION OUTPUT ;
    USE SIGNAL ;
    PORT
      LAYER M3 ;
        RECT  49.608 34.416 49.626 34.56 ;
    END
  END head[10]
  PIN head[11]
    DIRECTION OUTPUT ;
    USE SIGNAL ;
    PORT
      LAYER M5 ;
        RECT  48.912 34.368 48.936 34.56 ;
    END
  END head[11]
  PIN head[12]
    DIRECTION OUTPUT ;
    USE SIGNAL ;
    PORT
      LAYER M3 ;
        RECT  49.752 34.416 49.77 34.56 ;
    END
  END head[12]
  PIN head[13]
    DIRECTION OUTPUT ;
    USE SIGNAL ;
    PORT
      LAYER M5 ;
        RECT  49.056 34.368 49.08 34.56 ;
    END
  END head[13]
  PIN head[14]
    DIRECTION OUTPUT ;
    USE SIGNAL ;
    PORT
      LAYER M3 ;
        RECT  49.896 34.416 49.914 34.56 ;
    END
  END head[14]
  PIN head[15]
    DIRECTION OUTPUT ;
    USE SIGNAL ;
    PORT
      LAYER M5 ;
        RECT  49.2 34.368 49.224 34.56 ;
    END
  END head[15]
  PIN head[16]
    DIRECTION OUTPUT ;
    USE SIGNAL ;
    PORT
      LAYER M3 ;
        RECT  50.04 34.416 50.058 34.56 ;
    END
  END head[16]
  PIN head[17]
    DIRECTION OUTPUT ;
    USE SIGNAL ;
    PORT
      LAYER M5 ;
        RECT  49.344 34.368 49.368 34.56 ;
    END
  END head[17]
  PIN head[18]
    DIRECTION OUTPUT ;
    USE SIGNAL ;
    PORT
      LAYER M3 ;
        RECT  50.184 34.416 50.202 34.56 ;
    END
  END head[18]
  PIN head[19]
    DIRECTION OUTPUT ;
    USE SIGNAL ;
    PORT
      LAYER M5 ;
        RECT  49.488 34.368 49.512 34.56 ;
    END
  END head[19]
  PIN head[1]
    DIRECTION OUTPUT ;
    USE SIGNAL ;
    PORT
      LAYER M5 ;
        RECT  48.192 34.368 48.216 34.56 ;
    END
  END head[1]
  PIN head[20]
    DIRECTION OUTPUT ;
    USE SIGNAL ;
    PORT
      LAYER M3 ;
        RECT  50.328 34.416 50.346 34.56 ;
    END
  END head[20]
  PIN head[21]
    DIRECTION OUTPUT ;
    USE SIGNAL ;
    PORT
      LAYER M5 ;
        RECT  49.632 34.368 49.656 34.56 ;
    END
  END head[21]
  PIN head[22]
    DIRECTION OUTPUT ;
    USE SIGNAL ;
    PORT
      LAYER M3 ;
        RECT  50.472 34.416 50.49 34.56 ;
    END
  END head[22]
  PIN head[23]
    DIRECTION OUTPUT ;
    USE SIGNAL ;
    PORT
      LAYER M5 ;
        RECT  49.776 34.368 49.8 34.56 ;
    END
  END head[23]
  PIN head[24]
    DIRECTION OUTPUT ;
    USE SIGNAL ;
    PORT
      LAYER M3 ;
        RECT  50.616 34.416 50.634 34.56 ;
    END
  END head[24]
  PIN head[25]
    DIRECTION OUTPUT ;
    USE SIGNAL ;
    PORT
      LAYER M5 ;
        RECT  49.92 34.368 49.944 34.56 ;
    END
  END head[25]
  PIN head[26]
    DIRECTION OUTPUT ;
    USE SIGNAL ;
    PORT
      LAYER M3 ;
        RECT  50.76 34.416 50.778 34.56 ;
    END
  END head[26]
  PIN head[27]
    DIRECTION OUTPUT ;
    USE SIGNAL ;
    PORT
      LAYER M5 ;
        RECT  50.064 34.368 50.088 34.56 ;
    END
  END head[27]
  PIN head[28]
    DIRECTION OUTPUT ;
    USE SIGNAL ;
    PORT
      LAYER M3 ;
        RECT  50.904 34.416 50.922 34.56 ;
    END
  END head[28]
  PIN head[29]
    DIRECTION OUTPUT ;
    USE SIGNAL ;
    PORT
      LAYER M5 ;
        RECT  50.208 34.368 50.232 34.56 ;
    END
  END head[29]
  PIN head[2]
    DIRECTION OUTPUT ;
    USE SIGNAL ;
    PORT
      LAYER M3 ;
        RECT  49.032 34.416 49.05 34.56 ;
    END
  END head[2]
  PIN head[30]
    DIRECTION OUTPUT ;
    USE SIGNAL ;
    PORT
      LAYER M3 ;
        RECT  51.048 34.416 51.066 34.56 ;
    END
  END head[30]
  PIN head[31]
    DIRECTION OUTPUT ;
    USE SIGNAL ;
    PORT
      LAYER M5 ;
        RECT  50.352 34.368 50.376 34.56 ;
    END
  END head[31]
  PIN head[3]
    DIRECTION OUTPUT ;
    USE SIGNAL ;
    PORT
      LAYER M5 ;
        RECT  48.336 34.368 48.36 34.56 ;
    END
  END head[3]
  PIN head[4]
    DIRECTION OUTPUT ;
    USE SIGNAL ;
    PORT
      LAYER M3 ;
        RECT  49.176 34.416 49.194 34.56 ;
    END
  END head[4]
  PIN head[5]
    DIRECTION OUTPUT ;
    USE SIGNAL ;
    PORT
      LAYER M5 ;
        RECT  48.48 34.368 48.504 34.56 ;
    END
  END head[5]
  PIN head[6]
    DIRECTION OUTPUT ;
    USE SIGNAL ;
    PORT
      LAYER M3 ;
        RECT  49.32 34.416 49.338 34.56 ;
    END
  END head[6]
  PIN head[7]
    DIRECTION OUTPUT ;
    USE SIGNAL ;
    PORT
      LAYER M5 ;
        RECT  48.624 34.368 48.648 34.56 ;
    END
  END head[7]
  PIN head[8]
    DIRECTION OUTPUT ;
    USE SIGNAL ;
    PORT
      LAYER M3 ;
        RECT  49.464 34.416 49.482 34.56 ;
    END
  END head[8]
  PIN head[9]
    DIRECTION OUTPUT ;
    USE SIGNAL ;
    PORT
      LAYER M5 ;
        RECT  48.768 34.368 48.792 34.56 ;
    END
  END head[9]
  PIN head_logit[0]
    DIRECTION INPUT ;
    USE SIGNAL ;
    PORT
      LAYER M3 ;
        RECT  9 0 9.018 0.144 ;
    END
  END head_logit[0]
  PIN head_logit[10]
    DIRECTION INPUT ;
    USE SIGNAL ;
    PORT
      LAYER M3 ;
        RECT  9.72 0 9.738 0.144 ;
    END
  END head_logit[10]
  PIN head_logit[11]
    DIRECTION INPUT ;
    USE SIGNAL ;
    PORT
      LAYER M5 ;
        RECT  9.744 0 9.768 0.192 ;
    END
  END head_logit[11]
  PIN head_logit[12]
    DIRECTION INPUT ;
    USE SIGNAL ;
    PORT
      LAYER M3 ;
        RECT  9.864 0 9.882 0.144 ;
    END
  END head_logit[12]
  PIN head_logit[13]
    DIRECTION INPUT ;
    USE SIGNAL ;
    PORT
      LAYER M5 ;
        RECT  9.888 0 9.912 0.192 ;
    END
  END head_logit[13]
  PIN head_logit[14]
    DIRECTION INPUT ;
    USE SIGNAL ;
    PORT
      LAYER M3 ;
        RECT  10.008 0 10.026 0.144 ;
    END
  END head_logit[14]
  PIN head_logit[15]
    DIRECTION INPUT ;
    USE SIGNAL ;
    PORT
      LAYER M5 ;
        RECT  10.032 0 10.056 0.192 ;
    END
  END head_logit[15]
  PIN head_logit[16]
    DIRECTION INPUT ;
    USE SIGNAL ;
    PORT
      LAYER M3 ;
        RECT  10.152 0 10.17 0.144 ;
    END
  END head_logit[16]
  PIN head_logit[17]
    DIRECTION INPUT ;
    USE SIGNAL ;
    PORT
      LAYER M5 ;
        RECT  10.176 0 10.2 0.192 ;
    END
  END head_logit[17]
  PIN head_logit[18]
    DIRECTION INPUT ;
    USE SIGNAL ;
    PORT
      LAYER M3 ;
        RECT  10.296 0 10.314 0.144 ;
    END
  END head_logit[18]
  PIN head_logit[19]
    DIRECTION INPUT ;
    USE SIGNAL ;
    PORT
      LAYER M5 ;
        RECT  10.32 0 10.344 0.192 ;
    END
  END head_logit[19]
  PIN head_logit[1]
    DIRECTION INPUT ;
    USE SIGNAL ;
    PORT
      LAYER M5 ;
        RECT  9.024 0 9.048 0.192 ;
    END
  END head_logit[1]
  PIN head_logit[20]
    DIRECTION INPUT ;
    USE SIGNAL ;
    PORT
      LAYER M3 ;
        RECT  10.44 0 10.458 0.144 ;
    END
  END head_logit[20]
  PIN head_logit[21]
    DIRECTION INPUT ;
    USE SIGNAL ;
    PORT
      LAYER M5 ;
        RECT  10.464 0 10.488 0.192 ;
    END
  END head_logit[21]
  PIN head_logit[22]
    DIRECTION INPUT ;
    USE SIGNAL ;
    PORT
      LAYER M3 ;
        RECT  10.584 0 10.602 0.144 ;
    END
  END head_logit[22]
  PIN head_logit[23]
    DIRECTION INPUT ;
    USE SIGNAL ;
    PORT
      LAYER M5 ;
        RECT  10.608 0 10.632 0.192 ;
    END
  END head_logit[23]
  PIN head_logit[24]
    DIRECTION INPUT ;
    USE SIGNAL ;
    PORT
      LAYER M3 ;
        RECT  10.728 0 10.746 0.144 ;
    END
  END head_logit[24]
  PIN head_logit[25]
    DIRECTION INPUT ;
    USE SIGNAL ;
    PORT
      LAYER M5 ;
        RECT  10.752 0 10.776 0.192 ;
    END
  END head_logit[25]
  PIN head_logit[26]
    DIRECTION INPUT ;
    USE SIGNAL ;
    PORT
      LAYER M3 ;
        RECT  10.872 0 10.89 0.144 ;
    END
  END head_logit[26]
  PIN head_logit[27]
    DIRECTION INPUT ;
    USE SIGNAL ;
    PORT
      LAYER M5 ;
        RECT  10.896 0 10.92 0.192 ;
    END
  END head_logit[27]
  PIN head_logit[28]
    DIRECTION INPUT ;
    USE SIGNAL ;
    PORT
      LAYER M3 ;
        RECT  11.016 0 11.034 0.144 ;
    END
  END head_logit[28]
  PIN head_logit[29]
    DIRECTION INPUT ;
    USE SIGNAL ;
    PORT
      LAYER M5 ;
        RECT  11.04 0 11.064 0.192 ;
    END
  END head_logit[29]
  PIN head_logit[2]
    DIRECTION INPUT ;
    USE SIGNAL ;
    PORT
      LAYER M3 ;
        RECT  9.144 0 9.162 0.144 ;
    END
  END head_logit[2]
  PIN head_logit[30]
    DIRECTION INPUT ;
    USE SIGNAL ;
    PORT
      LAYER M3 ;
        RECT  11.16 0 11.178 0.144 ;
    END
  END head_logit[30]
  PIN head_logit[31]
    DIRECTION INPUT ;
    USE SIGNAL ;
    PORT
      LAYER M5 ;
        RECT  11.184 0 11.208 0.192 ;
    END
  END head_logit[31]
  PIN head_logit[3]
    DIRECTION INPUT ;
    USE SIGNAL ;
    PORT
      LAYER M5 ;
        RECT  9.168 0 9.192 0.192 ;
    END
  END head_logit[3]
  PIN head_logit[4]
    DIRECTION INPUT ;
    USE SIGNAL ;
    PORT
      LAYER M3 ;
        RECT  9.288 0 9.306 0.144 ;
    END
  END head_logit[4]
  PIN head_logit[5]
    DIRECTION INPUT ;
    USE SIGNAL ;
    PORT
      LAYER M5 ;
        RECT  9.312 0 9.336 0.192 ;
    END
  END head_logit[5]
  PIN head_logit[6]
    DIRECTION INPUT ;
    USE SIGNAL ;
    PORT
      LAYER M3 ;
        RECT  9.432 0 9.45 0.144 ;
    END
  END head_logit[6]
  PIN head_logit[7]
    DIRECTION INPUT ;
    USE SIGNAL ;
    PORT
      LAYER M5 ;
        RECT  9.456 0 9.48 0.192 ;
    END
  END head_logit[7]
  PIN head_logit[8]
    DIRECTION INPUT ;
    USE SIGNAL ;
    PORT
      LAYER M3 ;
        RECT  9.576 0 9.594 0.144 ;
    END
  END head_logit[8]
  PIN head_logit[9]
    DIRECTION INPUT ;
    USE SIGNAL ;
    PORT
      LAYER M5 ;
        RECT  9.6 0 9.624 0.192 ;
    END
  END head_logit[9]
  PIN jd[0]
    DIRECTION INPUT ;
    USE SIGNAL ;
    PORT
      LAYER M4 ;
        RECT  73.248 12.672 73.44 12.696 ;
    END
  END jd[0]
  PIN jd[10]
    DIRECTION INPUT ;
    USE SIGNAL ;
    PORT
      LAYER M4 ;
        RECT  73.248 15.552 73.44 15.576 ;
    END
  END jd[10]
  PIN jd[11]
    DIRECTION INPUT ;
    USE SIGNAL ;
    PORT
      LAYER M4 ;
        RECT  73.248 15.84 73.44 15.864 ;
    END
  END jd[11]
  PIN jd[12]
    DIRECTION INPUT ;
    USE SIGNAL ;
    PORT
      LAYER M4 ;
        RECT  73.248 16.128 73.44 16.152 ;
    END
  END jd[12]
  PIN jd[13]
    DIRECTION INPUT ;
    USE SIGNAL ;
    PORT
      LAYER M4 ;
        RECT  73.248 16.416 73.44 16.44 ;
    END
  END jd[13]
  PIN jd[14]
    DIRECTION INPUT ;
    USE SIGNAL ;
    PORT
      LAYER M4 ;
        RECT  73.248 16.704 73.44 16.728 ;
    END
  END jd[14]
  PIN jd[15]
    DIRECTION INPUT ;
    USE SIGNAL ;
    PORT
      LAYER M4 ;
        RECT  73.248 16.992 73.44 17.016 ;
    END
  END jd[15]
  PIN jd[16]
    DIRECTION INPUT ;
    USE SIGNAL ;
    PORT
      LAYER M4 ;
        RECT  73.248 17.28 73.44 17.304 ;
    END
  END jd[16]
  PIN jd[17]
    DIRECTION INPUT ;
    USE SIGNAL ;
    PORT
      LAYER M4 ;
        RECT  73.248 17.568 73.44 17.592 ;
    END
  END jd[17]
  PIN jd[18]
    DIRECTION INPUT ;
    USE SIGNAL ;
    PORT
      LAYER M4 ;
        RECT  73.248 17.856 73.44 17.88 ;
    END
  END jd[18]
  PIN jd[19]
    DIRECTION INPUT ;
    USE SIGNAL ;
    PORT
      LAYER M4 ;
        RECT  73.248 18.144 73.44 18.168 ;
    END
  END jd[19]
  PIN jd[1]
    DIRECTION INPUT ;
    USE SIGNAL ;
    PORT
      LAYER M4 ;
        RECT  73.248 12.96 73.44 12.984 ;
    END
  END jd[1]
  PIN jd[20]
    DIRECTION INPUT ;
    USE SIGNAL ;
    PORT
      LAYER M4 ;
        RECT  73.248 18.432 73.44 18.456 ;
    END
  END jd[20]
  PIN jd[21]
    DIRECTION INPUT ;
    USE SIGNAL ;
    PORT
      LAYER M4 ;
        RECT  73.248 18.72 73.44 18.744 ;
    END
  END jd[21]
  PIN jd[22]
    DIRECTION INPUT ;
    USE SIGNAL ;
    PORT
      LAYER M4 ;
        RECT  73.248 19.008 73.44 19.032 ;
    END
  END jd[22]
  PIN jd[23]
    DIRECTION INPUT ;
    USE SIGNAL ;
    PORT
      LAYER M4 ;
        RECT  73.248 19.296 73.44 19.32 ;
    END
  END jd[23]
  PIN jd[24]
    DIRECTION INPUT ;
    USE SIGNAL ;
    PORT
      LAYER M4 ;
        RECT  73.248 19.584 73.44 19.608 ;
    END
  END jd[24]
  PIN jd[25]
    DIRECTION INPUT ;
    USE SIGNAL ;
    PORT
      LAYER M4 ;
        RECT  73.248 19.872 73.44 19.896 ;
    END
  END jd[25]
  PIN jd[26]
    DIRECTION INPUT ;
    USE SIGNAL ;
    PORT
      LAYER M4 ;
        RECT  73.248 20.16 73.44 20.184 ;
    END
  END jd[26]
  PIN jd[27]
    DIRECTION INPUT ;
    USE SIGNAL ;
    PORT
      LAYER M4 ;
        RECT  73.248 20.448 73.44 20.472 ;
    END
  END jd[27]
  PIN jd[28]
    DIRECTION INPUT ;
    USE SIGNAL ;
    PORT
      LAYER M4 ;
        RECT  73.248 20.736 73.44 20.76 ;
    END
  END jd[28]
  PIN jd[29]
    DIRECTION INPUT ;
    USE SIGNAL ;
    PORT
      LAYER M4 ;
        RECT  73.248 21.024 73.44 21.048 ;
    END
  END jd[29]
  PIN jd[2]
    DIRECTION INPUT ;
    USE SIGNAL ;
    PORT
      LAYER M4 ;
        RECT  73.248 13.248 73.44 13.272 ;
    END
  END jd[2]
  PIN jd[30]
    DIRECTION INPUT ;
    USE SIGNAL ;
    PORT
      LAYER M4 ;
        RECT  73.248 21.312 73.44 21.336 ;
    END
  END jd[30]
  PIN jd[31]
    DIRECTION INPUT ;
    USE SIGNAL ;
    PORT
      LAYER M4 ;
        RECT  73.248 21.6 73.44 21.624 ;
    END
  END jd[31]
  PIN jd[3]
    DIRECTION INPUT ;
    USE SIGNAL ;
    PORT
      LAYER M4 ;
        RECT  73.248 13.536 73.44 13.56 ;
    END
  END jd[3]
  PIN jd[4]
    DIRECTION INPUT ;
    USE SIGNAL ;
    PORT
      LAYER M4 ;
        RECT  73.248 13.824 73.44 13.848 ;
    END
  END jd[4]
  PIN jd[5]
    DIRECTION INPUT ;
    USE SIGNAL ;
    PORT
      LAYER M4 ;
        RECT  73.248 14.112 73.44 14.136 ;
    END
  END jd[5]
  PIN jd[6]
    DIRECTION INPUT ;
    USE SIGNAL ;
    PORT
      LAYER M4 ;
        RECT  73.248 14.4 73.44 14.424 ;
    END
  END jd[6]
  PIN jd[7]
    DIRECTION INPUT ;
    USE SIGNAL ;
    PORT
      LAYER M4 ;
        RECT  73.248 14.688 73.44 14.712 ;
    END
  END jd[7]
  PIN jd[8]
    DIRECTION INPUT ;
    USE SIGNAL ;
    PORT
      LAYER M4 ;
        RECT  73.248 14.976 73.44 15 ;
    END
  END jd[8]
  PIN jd[9]
    DIRECTION INPUT ;
    USE SIGNAL ;
    PORT
      LAYER M4 ;
        RECT  73.248 15.264 73.44 15.288 ;
    END
  END jd[9]
  PIN je[0]
    DIRECTION INPUT ;
    USE SIGNAL ;
    PORT
      LAYER M3 ;
        RECT  53.352 0 53.37 0.144 ;
    END
    PORT
      LAYER M3 ;
        RECT  53.352 0.108 53.37 1.723 ;
    END
  END je[0]
  PIN je[1]
    DIRECTION INPUT ;
    USE SIGNAL ;
    PORT
      LAYER M5 ;
        RECT  53.088 0 53.112 0.192 ;
    END
    PORT
      LAYER M5 ;
        RECT  53.088 0.144 53.112 1.763 ;
    END
  END je[1]
  PIN jv
    DIRECTION INPUT ;
    USE SIGNAL ;
    PORT
      LAYER M3 ;
        RECT  50.904 0 50.922 0.144 ;
    END
  END jv
  PIN mul_embed[0]
    DIRECTION OUTPUT ;
    USE SIGNAL ;
    PORT
      LAYER M3 ;
        RECT  30.456 34.416 30.474 34.56 ;
    END
  END mul_embed[0]
  PIN mul_embed[100]
    DIRECTION OUTPUT ;
    USE SIGNAL ;
    PORT
      LAYER M3 ;
        RECT  37.656 34.416 37.674 34.56 ;
    END
  END mul_embed[100]
  PIN mul_embed[101]
    DIRECTION OUTPUT ;
    USE SIGNAL ;
    PORT
      LAYER M5 ;
        RECT  36.96 34.368 36.984 34.56 ;
    END
  END mul_embed[101]
  PIN mul_embed[102]
    DIRECTION OUTPUT ;
    USE SIGNAL ;
    PORT
      LAYER M3 ;
        RECT  37.8 34.416 37.818 34.56 ;
    END
  END mul_embed[102]
  PIN mul_embed[103]
    DIRECTION OUTPUT ;
    USE SIGNAL ;
    PORT
      LAYER M5 ;
        RECT  37.104 34.368 37.128 34.56 ;
    END
  END mul_embed[103]
  PIN mul_embed[104]
    DIRECTION OUTPUT ;
    USE SIGNAL ;
    PORT
      LAYER M3 ;
        RECT  37.944 34.416 37.962 34.56 ;
    END
  END mul_embed[104]
  PIN mul_embed[105]
    DIRECTION OUTPUT ;
    USE SIGNAL ;
    PORT
      LAYER M5 ;
        RECT  37.248 34.368 37.272 34.56 ;
    END
  END mul_embed[105]
  PIN mul_embed[106]
    DIRECTION OUTPUT ;
    USE SIGNAL ;
    PORT
      LAYER M3 ;
        RECT  38.088 34.416 38.106 34.56 ;
    END
  END mul_embed[106]
  PIN mul_embed[107]
    DIRECTION OUTPUT ;
    USE SIGNAL ;
    PORT
      LAYER M5 ;
        RECT  37.392 34.368 37.416 34.56 ;
    END
  END mul_embed[107]
  PIN mul_embed[108]
    DIRECTION OUTPUT ;
    USE SIGNAL ;
    PORT
      LAYER M3 ;
        RECT  38.232 34.416 38.25 34.56 ;
    END
  END mul_embed[108]
  PIN mul_embed[109]
    DIRECTION OUTPUT ;
    USE SIGNAL ;
    PORT
      LAYER M5 ;
        RECT  37.536 34.368 37.56 34.56 ;
    END
  END mul_embed[109]
  PIN mul_embed[10]
    DIRECTION OUTPUT ;
    USE SIGNAL ;
    PORT
      LAYER M3 ;
        RECT  31.176 34.416 31.194 34.56 ;
    END
  END mul_embed[10]
  PIN mul_embed[110]
    DIRECTION OUTPUT ;
    USE SIGNAL ;
    PORT
      LAYER M3 ;
        RECT  38.376 34.416 38.394 34.56 ;
    END
  END mul_embed[110]
  PIN mul_embed[111]
    DIRECTION OUTPUT ;
    USE SIGNAL ;
    PORT
      LAYER M5 ;
        RECT  37.68 34.368 37.704 34.56 ;
    END
  END mul_embed[111]
  PIN mul_embed[112]
    DIRECTION OUTPUT ;
    USE SIGNAL ;
    PORT
      LAYER M3 ;
        RECT  38.52 34.416 38.538 34.56 ;
    END
  END mul_embed[112]
  PIN mul_embed[113]
    DIRECTION OUTPUT ;
    USE SIGNAL ;
    PORT
      LAYER M5 ;
        RECT  37.824 34.368 37.848 34.56 ;
    END
  END mul_embed[113]
  PIN mul_embed[114]
    DIRECTION OUTPUT ;
    USE SIGNAL ;
    PORT
      LAYER M3 ;
        RECT  38.664 34.416 38.682 34.56 ;
    END
  END mul_embed[114]
  PIN mul_embed[115]
    DIRECTION OUTPUT ;
    USE SIGNAL ;
    PORT
      LAYER M5 ;
        RECT  37.968 34.368 37.992 34.56 ;
    END
  END mul_embed[115]
  PIN mul_embed[116]
    DIRECTION OUTPUT ;
    USE SIGNAL ;
    PORT
      LAYER M3 ;
        RECT  38.808 34.416 38.826 34.56 ;
    END
  END mul_embed[116]
  PIN mul_embed[117]
    DIRECTION OUTPUT ;
    USE SIGNAL ;
    PORT
      LAYER M5 ;
        RECT  38.112 34.368 38.136 34.56 ;
    END
  END mul_embed[117]
  PIN mul_embed[118]
    DIRECTION OUTPUT ;
    USE SIGNAL ;
    PORT
      LAYER M3 ;
        RECT  38.952 34.416 38.97 34.56 ;
    END
  END mul_embed[118]
  PIN mul_embed[119]
    DIRECTION OUTPUT ;
    USE SIGNAL ;
    PORT
      LAYER M5 ;
        RECT  38.256 34.368 38.28 34.56 ;
    END
  END mul_embed[119]
  PIN mul_embed[11]
    DIRECTION OUTPUT ;
    USE SIGNAL ;
    PORT
      LAYER M5 ;
        RECT  30.48 34.368 30.504 34.56 ;
    END
  END mul_embed[11]
  PIN mul_embed[120]
    DIRECTION OUTPUT ;
    USE SIGNAL ;
    PORT
      LAYER M3 ;
        RECT  39.096 34.416 39.114 34.56 ;
    END
  END mul_embed[120]
  PIN mul_embed[121]
    DIRECTION OUTPUT ;
    USE SIGNAL ;
    PORT
      LAYER M5 ;
        RECT  38.4 34.368 38.424 34.56 ;
    END
  END mul_embed[121]
  PIN mul_embed[122]
    DIRECTION OUTPUT ;
    USE SIGNAL ;
    PORT
      LAYER M3 ;
        RECT  39.24 34.416 39.258 34.56 ;
    END
  END mul_embed[122]
  PIN mul_embed[123]
    DIRECTION OUTPUT ;
    USE SIGNAL ;
    PORT
      LAYER M5 ;
        RECT  38.544 34.368 38.568 34.56 ;
    END
  END mul_embed[123]
  PIN mul_embed[124]
    DIRECTION OUTPUT ;
    USE SIGNAL ;
    PORT
      LAYER M3 ;
        RECT  39.384 34.416 39.402 34.56 ;
    END
  END mul_embed[124]
  PIN mul_embed[125]
    DIRECTION OUTPUT ;
    USE SIGNAL ;
    PORT
      LAYER M5 ;
        RECT  38.688 34.368 38.712 34.56 ;
    END
  END mul_embed[125]
  PIN mul_embed[126]
    DIRECTION OUTPUT ;
    USE SIGNAL ;
    PORT
      LAYER M3 ;
        RECT  39.528 34.416 39.546 34.56 ;
    END
  END mul_embed[126]
  PIN mul_embed[127]
    DIRECTION OUTPUT ;
    USE SIGNAL ;
    PORT
      LAYER M5 ;
        RECT  38.832 34.368 38.856 34.56 ;
    END
  END mul_embed[127]
  PIN mul_embed[128]
    DIRECTION OUTPUT ;
    USE SIGNAL ;
    PORT
      LAYER M3 ;
        RECT  39.672 34.416 39.69 34.56 ;
    END
  END mul_embed[128]
  PIN mul_embed[129]
    DIRECTION OUTPUT ;
    USE SIGNAL ;
    PORT
      LAYER M5 ;
        RECT  38.976 34.368 39 34.56 ;
    END
  END mul_embed[129]
  PIN mul_embed[12]
    DIRECTION OUTPUT ;
    USE SIGNAL ;
    PORT
      LAYER M3 ;
        RECT  31.32 34.416 31.338 34.56 ;
    END
  END mul_embed[12]
  PIN mul_embed[130]
    DIRECTION OUTPUT ;
    USE SIGNAL ;
    PORT
      LAYER M3 ;
        RECT  39.816 34.416 39.834 34.56 ;
    END
  END mul_embed[130]
  PIN mul_embed[131]
    DIRECTION OUTPUT ;
    USE SIGNAL ;
    PORT
      LAYER M5 ;
        RECT  39.12 34.368 39.144 34.56 ;
    END
  END mul_embed[131]
  PIN mul_embed[132]
    DIRECTION OUTPUT ;
    USE SIGNAL ;
    PORT
      LAYER M3 ;
        RECT  39.96 34.416 39.978 34.56 ;
    END
  END mul_embed[132]
  PIN mul_embed[133]
    DIRECTION OUTPUT ;
    USE SIGNAL ;
    PORT
      LAYER M5 ;
        RECT  39.264 34.368 39.288 34.56 ;
    END
  END mul_embed[133]
  PIN mul_embed[134]
    DIRECTION OUTPUT ;
    USE SIGNAL ;
    PORT
      LAYER M3 ;
        RECT  40.104 34.416 40.122 34.56 ;
    END
  END mul_embed[134]
  PIN mul_embed[135]
    DIRECTION OUTPUT ;
    USE SIGNAL ;
    PORT
      LAYER M5 ;
        RECT  39.408 34.368 39.432 34.56 ;
    END
  END mul_embed[135]
  PIN mul_embed[136]
    DIRECTION OUTPUT ;
    USE SIGNAL ;
    PORT
      LAYER M3 ;
        RECT  40.248 34.416 40.266 34.56 ;
    END
  END mul_embed[136]
  PIN mul_embed[137]
    DIRECTION OUTPUT ;
    USE SIGNAL ;
    PORT
      LAYER M5 ;
        RECT  39.552 34.368 39.576 34.56 ;
    END
  END mul_embed[137]
  PIN mul_embed[138]
    DIRECTION OUTPUT ;
    USE SIGNAL ;
    PORT
      LAYER M3 ;
        RECT  40.392 34.416 40.41 34.56 ;
    END
  END mul_embed[138]
  PIN mul_embed[139]
    DIRECTION OUTPUT ;
    USE SIGNAL ;
    PORT
      LAYER M5 ;
        RECT  39.696 34.368 39.72 34.56 ;
    END
  END mul_embed[139]
  PIN mul_embed[13]
    DIRECTION OUTPUT ;
    USE SIGNAL ;
    PORT
      LAYER M5 ;
        RECT  30.624 34.368 30.648 34.56 ;
    END
  END mul_embed[13]
  PIN mul_embed[140]
    DIRECTION OUTPUT ;
    USE SIGNAL ;
    PORT
      LAYER M3 ;
        RECT  40.536 34.416 40.554 34.56 ;
    END
  END mul_embed[140]
  PIN mul_embed[141]
    DIRECTION OUTPUT ;
    USE SIGNAL ;
    PORT
      LAYER M5 ;
        RECT  39.84 34.368 39.864 34.56 ;
    END
  END mul_embed[141]
  PIN mul_embed[142]
    DIRECTION OUTPUT ;
    USE SIGNAL ;
    PORT
      LAYER M3 ;
        RECT  40.68 34.416 40.698 34.56 ;
    END
  END mul_embed[142]
  PIN mul_embed[143]
    DIRECTION OUTPUT ;
    USE SIGNAL ;
    PORT
      LAYER M5 ;
        RECT  39.984 34.368 40.008 34.56 ;
    END
  END mul_embed[143]
  PIN mul_embed[144]
    DIRECTION OUTPUT ;
    USE SIGNAL ;
    PORT
      LAYER M3 ;
        RECT  40.824 34.416 40.842 34.56 ;
    END
  END mul_embed[144]
  PIN mul_embed[145]
    DIRECTION OUTPUT ;
    USE SIGNAL ;
    PORT
      LAYER M5 ;
        RECT  40.128 34.368 40.152 34.56 ;
    END
  END mul_embed[145]
  PIN mul_embed[146]
    DIRECTION OUTPUT ;
    USE SIGNAL ;
    PORT
      LAYER M3 ;
        RECT  40.968 34.416 40.986 34.56 ;
    END
  END mul_embed[146]
  PIN mul_embed[147]
    DIRECTION OUTPUT ;
    USE SIGNAL ;
    PORT
      LAYER M5 ;
        RECT  40.272 34.368 40.296 34.56 ;
    END
  END mul_embed[147]
  PIN mul_embed[148]
    DIRECTION OUTPUT ;
    USE SIGNAL ;
    PORT
      LAYER M3 ;
        RECT  41.112 34.416 41.13 34.56 ;
    END
  END mul_embed[148]
  PIN mul_embed[149]
    DIRECTION OUTPUT ;
    USE SIGNAL ;
    PORT
      LAYER M5 ;
        RECT  40.416 34.368 40.44 34.56 ;
    END
  END mul_embed[149]
  PIN mul_embed[14]
    DIRECTION OUTPUT ;
    USE SIGNAL ;
    PORT
      LAYER M3 ;
        RECT  31.464 34.416 31.482 34.56 ;
    END
  END mul_embed[14]
  PIN mul_embed[150]
    DIRECTION OUTPUT ;
    USE SIGNAL ;
    PORT
      LAYER M3 ;
        RECT  41.256 34.416 41.274 34.56 ;
    END
  END mul_embed[150]
  PIN mul_embed[151]
    DIRECTION OUTPUT ;
    USE SIGNAL ;
    PORT
      LAYER M5 ;
        RECT  40.56 34.368 40.584 34.56 ;
    END
  END mul_embed[151]
  PIN mul_embed[152]
    DIRECTION OUTPUT ;
    USE SIGNAL ;
    PORT
      LAYER M3 ;
        RECT  41.4 34.416 41.418 34.56 ;
    END
  END mul_embed[152]
  PIN mul_embed[153]
    DIRECTION OUTPUT ;
    USE SIGNAL ;
    PORT
      LAYER M5 ;
        RECT  40.704 34.368 40.728 34.56 ;
    END
  END mul_embed[153]
  PIN mul_embed[154]
    DIRECTION OUTPUT ;
    USE SIGNAL ;
    PORT
      LAYER M3 ;
        RECT  41.544 34.416 41.562 34.56 ;
    END
  END mul_embed[154]
  PIN mul_embed[155]
    DIRECTION OUTPUT ;
    USE SIGNAL ;
    PORT
      LAYER M5 ;
        RECT  40.848 34.368 40.872 34.56 ;
    END
  END mul_embed[155]
  PIN mul_embed[156]
    DIRECTION OUTPUT ;
    USE SIGNAL ;
    PORT
      LAYER M3 ;
        RECT  41.688 34.416 41.706 34.56 ;
    END
  END mul_embed[156]
  PIN mul_embed[157]
    DIRECTION OUTPUT ;
    USE SIGNAL ;
    PORT
      LAYER M5 ;
        RECT  40.992 34.368 41.016 34.56 ;
    END
  END mul_embed[157]
  PIN mul_embed[158]
    DIRECTION OUTPUT ;
    USE SIGNAL ;
    PORT
      LAYER M3 ;
        RECT  41.832 34.416 41.85 34.56 ;
    END
  END mul_embed[158]
  PIN mul_embed[159]
    DIRECTION OUTPUT ;
    USE SIGNAL ;
    PORT
      LAYER M5 ;
        RECT  41.136 34.368 41.16 34.56 ;
    END
  END mul_embed[159]
  PIN mul_embed[15]
    DIRECTION OUTPUT ;
    USE SIGNAL ;
    PORT
      LAYER M5 ;
        RECT  30.768 34.368 30.792 34.56 ;
    END
  END mul_embed[15]
  PIN mul_embed[160]
    DIRECTION OUTPUT ;
    USE SIGNAL ;
    PORT
      LAYER M3 ;
        RECT  41.976 34.416 41.994 34.56 ;
    END
  END mul_embed[160]
  PIN mul_embed[161]
    DIRECTION OUTPUT ;
    USE SIGNAL ;
    PORT
      LAYER M5 ;
        RECT  41.28 34.368 41.304 34.56 ;
    END
  END mul_embed[161]
  PIN mul_embed[162]
    DIRECTION OUTPUT ;
    USE SIGNAL ;
    PORT
      LAYER M3 ;
        RECT  42.12 34.416 42.138 34.56 ;
    END
  END mul_embed[162]
  PIN mul_embed[163]
    DIRECTION OUTPUT ;
    USE SIGNAL ;
    PORT
      LAYER M5 ;
        RECT  41.424 34.368 41.448 34.56 ;
    END
  END mul_embed[163]
  PIN mul_embed[164]
    DIRECTION OUTPUT ;
    USE SIGNAL ;
    PORT
      LAYER M3 ;
        RECT  42.264 34.416 42.282 34.56 ;
    END
  END mul_embed[164]
  PIN mul_embed[165]
    DIRECTION OUTPUT ;
    USE SIGNAL ;
    PORT
      LAYER M5 ;
        RECT  41.568 34.368 41.592 34.56 ;
    END
  END mul_embed[165]
  PIN mul_embed[166]
    DIRECTION OUTPUT ;
    USE SIGNAL ;
    PORT
      LAYER M3 ;
        RECT  42.408 34.416 42.426 34.56 ;
    END
  END mul_embed[166]
  PIN mul_embed[167]
    DIRECTION OUTPUT ;
    USE SIGNAL ;
    PORT
      LAYER M5 ;
        RECT  41.712 34.368 41.736 34.56 ;
    END
  END mul_embed[167]
  PIN mul_embed[168]
    DIRECTION OUTPUT ;
    USE SIGNAL ;
    PORT
      LAYER M3 ;
        RECT  42.552 34.416 42.57 34.56 ;
    END
  END mul_embed[168]
  PIN mul_embed[169]
    DIRECTION OUTPUT ;
    USE SIGNAL ;
    PORT
      LAYER M5 ;
        RECT  41.856 34.368 41.88 34.56 ;
    END
  END mul_embed[169]
  PIN mul_embed[16]
    DIRECTION OUTPUT ;
    USE SIGNAL ;
    PORT
      LAYER M3 ;
        RECT  31.608 34.416 31.626 34.56 ;
    END
  END mul_embed[16]
  PIN mul_embed[170]
    DIRECTION OUTPUT ;
    USE SIGNAL ;
    PORT
      LAYER M3 ;
        RECT  42.696 34.416 42.714 34.56 ;
    END
  END mul_embed[170]
  PIN mul_embed[171]
    DIRECTION OUTPUT ;
    USE SIGNAL ;
    PORT
      LAYER M5 ;
        RECT  42 34.368 42.024 34.56 ;
    END
  END mul_embed[171]
  PIN mul_embed[172]
    DIRECTION OUTPUT ;
    USE SIGNAL ;
    PORT
      LAYER M3 ;
        RECT  42.84 34.416 42.858 34.56 ;
    END
  END mul_embed[172]
  PIN mul_embed[173]
    DIRECTION OUTPUT ;
    USE SIGNAL ;
    PORT
      LAYER M5 ;
        RECT  42.144 34.368 42.168 34.56 ;
    END
  END mul_embed[173]
  PIN mul_embed[174]
    DIRECTION OUTPUT ;
    USE SIGNAL ;
    PORT
      LAYER M3 ;
        RECT  42.984 34.416 43.002 34.56 ;
    END
  END mul_embed[174]
  PIN mul_embed[175]
    DIRECTION OUTPUT ;
    USE SIGNAL ;
    PORT
      LAYER M5 ;
        RECT  42.288 34.368 42.312 34.56 ;
    END
  END mul_embed[175]
  PIN mul_embed[176]
    DIRECTION OUTPUT ;
    USE SIGNAL ;
    PORT
      LAYER M3 ;
        RECT  43.128 34.416 43.146 34.56 ;
    END
  END mul_embed[176]
  PIN mul_embed[177]
    DIRECTION OUTPUT ;
    USE SIGNAL ;
    PORT
      LAYER M5 ;
        RECT  42.432 34.368 42.456 34.56 ;
    END
  END mul_embed[177]
  PIN mul_embed[178]
    DIRECTION OUTPUT ;
    USE SIGNAL ;
    PORT
      LAYER M3 ;
        RECT  43.272 34.416 43.29 34.56 ;
    END
  END mul_embed[178]
  PIN mul_embed[179]
    DIRECTION OUTPUT ;
    USE SIGNAL ;
    PORT
      LAYER M5 ;
        RECT  42.576 34.368 42.6 34.56 ;
    END
  END mul_embed[179]
  PIN mul_embed[17]
    DIRECTION OUTPUT ;
    USE SIGNAL ;
    PORT
      LAYER M5 ;
        RECT  30.912 34.368 30.936 34.56 ;
    END
  END mul_embed[17]
  PIN mul_embed[180]
    DIRECTION OUTPUT ;
    USE SIGNAL ;
    PORT
      LAYER M3 ;
        RECT  43.416 34.416 43.434 34.56 ;
    END
  END mul_embed[180]
  PIN mul_embed[181]
    DIRECTION OUTPUT ;
    USE SIGNAL ;
    PORT
      LAYER M5 ;
        RECT  42.72 34.368 42.744 34.56 ;
    END
  END mul_embed[181]
  PIN mul_embed[182]
    DIRECTION OUTPUT ;
    USE SIGNAL ;
    PORT
      LAYER M3 ;
        RECT  43.56 34.416 43.578 34.56 ;
    END
  END mul_embed[182]
  PIN mul_embed[183]
    DIRECTION OUTPUT ;
    USE SIGNAL ;
    PORT
      LAYER M5 ;
        RECT  42.864 34.368 42.888 34.56 ;
    END
  END mul_embed[183]
  PIN mul_embed[184]
    DIRECTION OUTPUT ;
    USE SIGNAL ;
    PORT
      LAYER M3 ;
        RECT  43.704 34.416 43.722 34.56 ;
    END
  END mul_embed[184]
  PIN mul_embed[185]
    DIRECTION OUTPUT ;
    USE SIGNAL ;
    PORT
      LAYER M5 ;
        RECT  43.008 34.368 43.032 34.56 ;
    END
  END mul_embed[185]
  PIN mul_embed[186]
    DIRECTION OUTPUT ;
    USE SIGNAL ;
    PORT
      LAYER M3 ;
        RECT  43.848 34.416 43.866 34.56 ;
    END
  END mul_embed[186]
  PIN mul_embed[187]
    DIRECTION OUTPUT ;
    USE SIGNAL ;
    PORT
      LAYER M5 ;
        RECT  43.152 34.368 43.176 34.56 ;
    END
  END mul_embed[187]
  PIN mul_embed[188]
    DIRECTION OUTPUT ;
    USE SIGNAL ;
    PORT
      LAYER M3 ;
        RECT  43.992 34.416 44.01 34.56 ;
    END
  END mul_embed[188]
  PIN mul_embed[189]
    DIRECTION OUTPUT ;
    USE SIGNAL ;
    PORT
      LAYER M5 ;
        RECT  43.296 34.368 43.32 34.56 ;
    END
  END mul_embed[189]
  PIN mul_embed[18]
    DIRECTION OUTPUT ;
    USE SIGNAL ;
    PORT
      LAYER M3 ;
        RECT  31.752 34.416 31.77 34.56 ;
    END
  END mul_embed[18]
  PIN mul_embed[190]
    DIRECTION OUTPUT ;
    USE SIGNAL ;
    PORT
      LAYER M3 ;
        RECT  44.136 34.416 44.154 34.56 ;
    END
  END mul_embed[190]
  PIN mul_embed[191]
    DIRECTION OUTPUT ;
    USE SIGNAL ;
    PORT
      LAYER M5 ;
        RECT  43.44 34.368 43.464 34.56 ;
    END
  END mul_embed[191]
  PIN mul_embed[192]
    DIRECTION OUTPUT ;
    USE SIGNAL ;
    PORT
      LAYER M3 ;
        RECT  44.28 34.416 44.298 34.56 ;
    END
  END mul_embed[192]
  PIN mul_embed[193]
    DIRECTION OUTPUT ;
    USE SIGNAL ;
    PORT
      LAYER M5 ;
        RECT  43.584 34.368 43.608 34.56 ;
    END
  END mul_embed[193]
  PIN mul_embed[194]
    DIRECTION OUTPUT ;
    USE SIGNAL ;
    PORT
      LAYER M3 ;
        RECT  44.424 34.416 44.442 34.56 ;
    END
  END mul_embed[194]
  PIN mul_embed[195]
    DIRECTION OUTPUT ;
    USE SIGNAL ;
    PORT
      LAYER M5 ;
        RECT  43.728 34.368 43.752 34.56 ;
    END
  END mul_embed[195]
  PIN mul_embed[196]
    DIRECTION OUTPUT ;
    USE SIGNAL ;
    PORT
      LAYER M3 ;
        RECT  44.568 34.416 44.586 34.56 ;
    END
  END mul_embed[196]
  PIN mul_embed[197]
    DIRECTION OUTPUT ;
    USE SIGNAL ;
    PORT
      LAYER M5 ;
        RECT  43.872 34.368 43.896 34.56 ;
    END
  END mul_embed[197]
  PIN mul_embed[198]
    DIRECTION OUTPUT ;
    USE SIGNAL ;
    PORT
      LAYER M3 ;
        RECT  44.712 34.416 44.73 34.56 ;
    END
  END mul_embed[198]
  PIN mul_embed[199]
    DIRECTION OUTPUT ;
    USE SIGNAL ;
    PORT
      LAYER M5 ;
        RECT  44.016 34.368 44.04 34.56 ;
    END
  END mul_embed[199]
  PIN mul_embed[19]
    DIRECTION OUTPUT ;
    USE SIGNAL ;
    PORT
      LAYER M5 ;
        RECT  31.056 34.368 31.08 34.56 ;
    END
  END mul_embed[19]
  PIN mul_embed[1]
    DIRECTION OUTPUT ;
    USE SIGNAL ;
    PORT
      LAYER M5 ;
        RECT  29.76 34.368 29.784 34.56 ;
    END
  END mul_embed[1]
  PIN mul_embed[200]
    DIRECTION OUTPUT ;
    USE SIGNAL ;
    PORT
      LAYER M3 ;
        RECT  44.856 34.416 44.874 34.56 ;
    END
  END mul_embed[200]
  PIN mul_embed[201]
    DIRECTION OUTPUT ;
    USE SIGNAL ;
    PORT
      LAYER M5 ;
        RECT  44.16 34.368 44.184 34.56 ;
    END
  END mul_embed[201]
  PIN mul_embed[202]
    DIRECTION OUTPUT ;
    USE SIGNAL ;
    PORT
      LAYER M3 ;
        RECT  45 34.416 45.018 34.56 ;
    END
  END mul_embed[202]
  PIN mul_embed[203]
    DIRECTION OUTPUT ;
    USE SIGNAL ;
    PORT
      LAYER M5 ;
        RECT  44.304 34.368 44.328 34.56 ;
    END
  END mul_embed[203]
  PIN mul_embed[204]
    DIRECTION OUTPUT ;
    USE SIGNAL ;
    PORT
      LAYER M3 ;
        RECT  45.144 34.416 45.162 34.56 ;
    END
  END mul_embed[204]
  PIN mul_embed[205]
    DIRECTION OUTPUT ;
    USE SIGNAL ;
    PORT
      LAYER M5 ;
        RECT  44.448 34.368 44.472 34.56 ;
    END
  END mul_embed[205]
  PIN mul_embed[206]
    DIRECTION OUTPUT ;
    USE SIGNAL ;
    PORT
      LAYER M3 ;
        RECT  45.288 34.416 45.306 34.56 ;
    END
  END mul_embed[206]
  PIN mul_embed[207]
    DIRECTION OUTPUT ;
    USE SIGNAL ;
    PORT
      LAYER M5 ;
        RECT  44.592 34.368 44.616 34.56 ;
    END
  END mul_embed[207]
  PIN mul_embed[208]
    DIRECTION OUTPUT ;
    USE SIGNAL ;
    PORT
      LAYER M3 ;
        RECT  45.432 34.416 45.45 34.56 ;
    END
  END mul_embed[208]
  PIN mul_embed[209]
    DIRECTION OUTPUT ;
    USE SIGNAL ;
    PORT
      LAYER M5 ;
        RECT  44.736 34.368 44.76 34.56 ;
    END
  END mul_embed[209]
  PIN mul_embed[20]
    DIRECTION OUTPUT ;
    USE SIGNAL ;
    PORT
      LAYER M3 ;
        RECT  31.896 34.416 31.914 34.56 ;
    END
  END mul_embed[20]
  PIN mul_embed[210]
    DIRECTION OUTPUT ;
    USE SIGNAL ;
    PORT
      LAYER M3 ;
        RECT  45.576 34.416 45.594 34.56 ;
    END
  END mul_embed[210]
  PIN mul_embed[211]
    DIRECTION OUTPUT ;
    USE SIGNAL ;
    PORT
      LAYER M5 ;
        RECT  44.88 34.368 44.904 34.56 ;
    END
  END mul_embed[211]
  PIN mul_embed[212]
    DIRECTION OUTPUT ;
    USE SIGNAL ;
    PORT
      LAYER M3 ;
        RECT  45.72 34.416 45.738 34.56 ;
    END
  END mul_embed[212]
  PIN mul_embed[213]
    DIRECTION OUTPUT ;
    USE SIGNAL ;
    PORT
      LAYER M5 ;
        RECT  45.024 34.368 45.048 34.56 ;
    END
  END mul_embed[213]
  PIN mul_embed[214]
    DIRECTION OUTPUT ;
    USE SIGNAL ;
    PORT
      LAYER M3 ;
        RECT  45.864 34.416 45.882 34.56 ;
    END
  END mul_embed[214]
  PIN mul_embed[215]
    DIRECTION OUTPUT ;
    USE SIGNAL ;
    PORT
      LAYER M5 ;
        RECT  45.168 34.368 45.192 34.56 ;
    END
  END mul_embed[215]
  PIN mul_embed[216]
    DIRECTION OUTPUT ;
    USE SIGNAL ;
    PORT
      LAYER M3 ;
        RECT  46.008 34.416 46.026 34.56 ;
    END
  END mul_embed[216]
  PIN mul_embed[217]
    DIRECTION OUTPUT ;
    USE SIGNAL ;
    PORT
      LAYER M5 ;
        RECT  45.312 34.368 45.336 34.56 ;
    END
  END mul_embed[217]
  PIN mul_embed[218]
    DIRECTION OUTPUT ;
    USE SIGNAL ;
    PORT
      LAYER M3 ;
        RECT  46.152 34.416 46.17 34.56 ;
    END
  END mul_embed[218]
  PIN mul_embed[219]
    DIRECTION OUTPUT ;
    USE SIGNAL ;
    PORT
      LAYER M5 ;
        RECT  45.456 34.368 45.48 34.56 ;
    END
  END mul_embed[219]
  PIN mul_embed[21]
    DIRECTION OUTPUT ;
    USE SIGNAL ;
    PORT
      LAYER M5 ;
        RECT  31.2 34.368 31.224 34.56 ;
    END
  END mul_embed[21]
  PIN mul_embed[220]
    DIRECTION OUTPUT ;
    USE SIGNAL ;
    PORT
      LAYER M3 ;
        RECT  46.296 34.416 46.314 34.56 ;
    END
  END mul_embed[220]
  PIN mul_embed[221]
    DIRECTION OUTPUT ;
    USE SIGNAL ;
    PORT
      LAYER M5 ;
        RECT  45.6 34.368 45.624 34.56 ;
    END
  END mul_embed[221]
  PIN mul_embed[222]
    DIRECTION OUTPUT ;
    USE SIGNAL ;
    PORT
      LAYER M3 ;
        RECT  46.44 34.416 46.458 34.56 ;
    END
  END mul_embed[222]
  PIN mul_embed[223]
    DIRECTION OUTPUT ;
    USE SIGNAL ;
    PORT
      LAYER M5 ;
        RECT  45.744 34.368 45.768 34.56 ;
    END
  END mul_embed[223]
  PIN mul_embed[224]
    DIRECTION OUTPUT ;
    USE SIGNAL ;
    PORT
      LAYER M3 ;
        RECT  46.584 34.416 46.602 34.56 ;
    END
  END mul_embed[224]
  PIN mul_embed[225]
    DIRECTION OUTPUT ;
    USE SIGNAL ;
    PORT
      LAYER M5 ;
        RECT  45.888 34.368 45.912 34.56 ;
    END
  END mul_embed[225]
  PIN mul_embed[226]
    DIRECTION OUTPUT ;
    USE SIGNAL ;
    PORT
      LAYER M3 ;
        RECT  46.728 34.416 46.746 34.56 ;
    END
  END mul_embed[226]
  PIN mul_embed[227]
    DIRECTION OUTPUT ;
    USE SIGNAL ;
    PORT
      LAYER M5 ;
        RECT  46.032 34.368 46.056 34.56 ;
    END
  END mul_embed[227]
  PIN mul_embed[228]
    DIRECTION OUTPUT ;
    USE SIGNAL ;
    PORT
      LAYER M3 ;
        RECT  46.872 34.416 46.89 34.56 ;
    END
  END mul_embed[228]
  PIN mul_embed[229]
    DIRECTION OUTPUT ;
    USE SIGNAL ;
    PORT
      LAYER M5 ;
        RECT  46.176 34.368 46.2 34.56 ;
    END
  END mul_embed[229]
  PIN mul_embed[22]
    DIRECTION OUTPUT ;
    USE SIGNAL ;
    PORT
      LAYER M3 ;
        RECT  32.04 34.416 32.058 34.56 ;
    END
  END mul_embed[22]
  PIN mul_embed[230]
    DIRECTION OUTPUT ;
    USE SIGNAL ;
    PORT
      LAYER M3 ;
        RECT  47.016 34.416 47.034 34.56 ;
    END
  END mul_embed[230]
  PIN mul_embed[231]
    DIRECTION OUTPUT ;
    USE SIGNAL ;
    PORT
      LAYER M5 ;
        RECT  46.32 34.368 46.344 34.56 ;
    END
  END mul_embed[231]
  PIN mul_embed[232]
    DIRECTION OUTPUT ;
    USE SIGNAL ;
    PORT
      LAYER M3 ;
        RECT  47.16 34.416 47.178 34.56 ;
    END
  END mul_embed[232]
  PIN mul_embed[233]
    DIRECTION OUTPUT ;
    USE SIGNAL ;
    PORT
      LAYER M5 ;
        RECT  46.464 34.368 46.488 34.56 ;
    END
  END mul_embed[233]
  PIN mul_embed[234]
    DIRECTION OUTPUT ;
    USE SIGNAL ;
    PORT
      LAYER M3 ;
        RECT  47.304 34.416 47.322 34.56 ;
    END
  END mul_embed[234]
  PIN mul_embed[235]
    DIRECTION OUTPUT ;
    USE SIGNAL ;
    PORT
      LAYER M5 ;
        RECT  46.608 34.368 46.632 34.56 ;
    END
  END mul_embed[235]
  PIN mul_embed[236]
    DIRECTION OUTPUT ;
    USE SIGNAL ;
    PORT
      LAYER M3 ;
        RECT  47.448 34.416 47.466 34.56 ;
    END
  END mul_embed[236]
  PIN mul_embed[237]
    DIRECTION OUTPUT ;
    USE SIGNAL ;
    PORT
      LAYER M5 ;
        RECT  46.752 34.368 46.776 34.56 ;
    END
  END mul_embed[237]
  PIN mul_embed[238]
    DIRECTION OUTPUT ;
    USE SIGNAL ;
    PORT
      LAYER M3 ;
        RECT  47.592 34.416 47.61 34.56 ;
    END
  END mul_embed[238]
  PIN mul_embed[239]
    DIRECTION OUTPUT ;
    USE SIGNAL ;
    PORT
      LAYER M5 ;
        RECT  46.896 34.368 46.92 34.56 ;
    END
  END mul_embed[239]
  PIN mul_embed[23]
    DIRECTION OUTPUT ;
    USE SIGNAL ;
    PORT
      LAYER M5 ;
        RECT  31.344 34.368 31.368 34.56 ;
    END
  END mul_embed[23]
  PIN mul_embed[240]
    DIRECTION OUTPUT ;
    USE SIGNAL ;
    PORT
      LAYER M3 ;
        RECT  47.736 34.416 47.754 34.56 ;
    END
  END mul_embed[240]
  PIN mul_embed[241]
    DIRECTION OUTPUT ;
    USE SIGNAL ;
    PORT
      LAYER M5 ;
        RECT  47.04 34.368 47.064 34.56 ;
    END
  END mul_embed[241]
  PIN mul_embed[242]
    DIRECTION OUTPUT ;
    USE SIGNAL ;
    PORT
      LAYER M3 ;
        RECT  47.88 34.416 47.898 34.56 ;
    END
  END mul_embed[242]
  PIN mul_embed[243]
    DIRECTION OUTPUT ;
    USE SIGNAL ;
    PORT
      LAYER M5 ;
        RECT  47.184 34.368 47.208 34.56 ;
    END
  END mul_embed[243]
  PIN mul_embed[244]
    DIRECTION OUTPUT ;
    USE SIGNAL ;
    PORT
      LAYER M3 ;
        RECT  48.024 34.416 48.042 34.56 ;
    END
  END mul_embed[244]
  PIN mul_embed[245]
    DIRECTION OUTPUT ;
    USE SIGNAL ;
    PORT
      LAYER M5 ;
        RECT  47.328 34.368 47.352 34.56 ;
    END
  END mul_embed[245]
  PIN mul_embed[246]
    DIRECTION OUTPUT ;
    USE SIGNAL ;
    PORT
      LAYER M3 ;
        RECT  48.168 34.416 48.186 34.56 ;
    END
  END mul_embed[246]
  PIN mul_embed[247]
    DIRECTION OUTPUT ;
    USE SIGNAL ;
    PORT
      LAYER M5 ;
        RECT  47.472 34.368 47.496 34.56 ;
    END
  END mul_embed[247]
  PIN mul_embed[248]
    DIRECTION OUTPUT ;
    USE SIGNAL ;
    PORT
      LAYER M3 ;
        RECT  48.312 34.416 48.33 34.56 ;
    END
  END mul_embed[248]
  PIN mul_embed[249]
    DIRECTION OUTPUT ;
    USE SIGNAL ;
    PORT
      LAYER M5 ;
        RECT  47.616 34.368 47.64 34.56 ;
    END
  END mul_embed[249]
  PIN mul_embed[24]
    DIRECTION OUTPUT ;
    USE SIGNAL ;
    PORT
      LAYER M3 ;
        RECT  32.184 34.416 32.202 34.56 ;
    END
  END mul_embed[24]
  PIN mul_embed[250]
    DIRECTION OUTPUT ;
    USE SIGNAL ;
    PORT
      LAYER M3 ;
        RECT  48.456 34.416 48.474 34.56 ;
    END
  END mul_embed[250]
  PIN mul_embed[251]
    DIRECTION OUTPUT ;
    USE SIGNAL ;
    PORT
      LAYER M5 ;
        RECT  47.76 34.368 47.784 34.56 ;
    END
  END mul_embed[251]
  PIN mul_embed[252]
    DIRECTION OUTPUT ;
    USE SIGNAL ;
    PORT
      LAYER M3 ;
        RECT  48.6 34.416 48.618 34.56 ;
    END
  END mul_embed[252]
  PIN mul_embed[253]
    DIRECTION OUTPUT ;
    USE SIGNAL ;
    PORT
      LAYER M5 ;
        RECT  47.904 34.368 47.928 34.56 ;
    END
  END mul_embed[253]
  PIN mul_embed[254]
    DIRECTION OUTPUT ;
    USE SIGNAL ;
    PORT
      LAYER M3 ;
        RECT  48.744 34.416 48.762 34.56 ;
    END
  END mul_embed[254]
  PIN mul_embed[255]
    DIRECTION OUTPUT ;
    USE SIGNAL ;
    PORT
      LAYER M5 ;
        RECT  48.048 34.368 48.072 34.56 ;
    END
  END mul_embed[255]
  PIN mul_embed[25]
    DIRECTION OUTPUT ;
    USE SIGNAL ;
    PORT
      LAYER M5 ;
        RECT  31.488 34.368 31.512 34.56 ;
    END
  END mul_embed[25]
  PIN mul_embed[26]
    DIRECTION OUTPUT ;
    USE SIGNAL ;
    PORT
      LAYER M3 ;
        RECT  32.328 34.416 32.346 34.56 ;
    END
  END mul_embed[26]
  PIN mul_embed[27]
    DIRECTION OUTPUT ;
    USE SIGNAL ;
    PORT
      LAYER M5 ;
        RECT  31.632 34.368 31.656 34.56 ;
    END
  END mul_embed[27]
  PIN mul_embed[28]
    DIRECTION OUTPUT ;
    USE SIGNAL ;
    PORT
      LAYER M3 ;
        RECT  32.472 34.416 32.49 34.56 ;
    END
  END mul_embed[28]
  PIN mul_embed[29]
    DIRECTION OUTPUT ;
    USE SIGNAL ;
    PORT
      LAYER M5 ;
        RECT  31.776 34.368 31.8 34.56 ;
    END
  END mul_embed[29]
  PIN mul_embed[2]
    DIRECTION OUTPUT ;
    USE SIGNAL ;
    PORT
      LAYER M3 ;
        RECT  30.6 34.416 30.618 34.56 ;
    END
  END mul_embed[2]
  PIN mul_embed[30]
    DIRECTION OUTPUT ;
    USE SIGNAL ;
    PORT
      LAYER M3 ;
        RECT  32.616 34.416 32.634 34.56 ;
    END
  END mul_embed[30]
  PIN mul_embed[31]
    DIRECTION OUTPUT ;
    USE SIGNAL ;
    PORT
      LAYER M5 ;
        RECT  31.92 34.368 31.944 34.56 ;
    END
  END mul_embed[31]
  PIN mul_embed[32]
    DIRECTION OUTPUT ;
    USE SIGNAL ;
    PORT
      LAYER M3 ;
        RECT  32.76 34.416 32.778 34.56 ;
    END
  END mul_embed[32]
  PIN mul_embed[33]
    DIRECTION OUTPUT ;
    USE SIGNAL ;
    PORT
      LAYER M5 ;
        RECT  32.064 34.368 32.088 34.56 ;
    END
  END mul_embed[33]
  PIN mul_embed[34]
    DIRECTION OUTPUT ;
    USE SIGNAL ;
    PORT
      LAYER M3 ;
        RECT  32.904 34.416 32.922 34.56 ;
    END
  END mul_embed[34]
  PIN mul_embed[35]
    DIRECTION OUTPUT ;
    USE SIGNAL ;
    PORT
      LAYER M5 ;
        RECT  32.208 34.368 32.232 34.56 ;
    END
  END mul_embed[35]
  PIN mul_embed[36]
    DIRECTION OUTPUT ;
    USE SIGNAL ;
    PORT
      LAYER M3 ;
        RECT  33.048 34.416 33.066 34.56 ;
    END
  END mul_embed[36]
  PIN mul_embed[37]
    DIRECTION OUTPUT ;
    USE SIGNAL ;
    PORT
      LAYER M5 ;
        RECT  32.352 34.368 32.376 34.56 ;
    END
  END mul_embed[37]
  PIN mul_embed[38]
    DIRECTION OUTPUT ;
    USE SIGNAL ;
    PORT
      LAYER M3 ;
        RECT  33.192 34.416 33.21 34.56 ;
    END
  END mul_embed[38]
  PIN mul_embed[39]
    DIRECTION OUTPUT ;
    USE SIGNAL ;
    PORT
      LAYER M5 ;
        RECT  32.496 34.368 32.52 34.56 ;
    END
  END mul_embed[39]
  PIN mul_embed[3]
    DIRECTION OUTPUT ;
    USE SIGNAL ;
    PORT
      LAYER M5 ;
        RECT  29.904 34.368 29.928 34.56 ;
    END
  END mul_embed[3]
  PIN mul_embed[40]
    DIRECTION OUTPUT ;
    USE SIGNAL ;
    PORT
      LAYER M3 ;
        RECT  33.336 34.416 33.354 34.56 ;
    END
  END mul_embed[40]
  PIN mul_embed[41]
    DIRECTION OUTPUT ;
    USE SIGNAL ;
    PORT
      LAYER M5 ;
        RECT  32.64 34.368 32.664 34.56 ;
    END
  END mul_embed[41]
  PIN mul_embed[42]
    DIRECTION OUTPUT ;
    USE SIGNAL ;
    PORT
      LAYER M3 ;
        RECT  33.48 34.416 33.498 34.56 ;
    END
  END mul_embed[42]
  PIN mul_embed[43]
    DIRECTION OUTPUT ;
    USE SIGNAL ;
    PORT
      LAYER M5 ;
        RECT  32.784 34.368 32.808 34.56 ;
    END
  END mul_embed[43]
  PIN mul_embed[44]
    DIRECTION OUTPUT ;
    USE SIGNAL ;
    PORT
      LAYER M3 ;
        RECT  33.624 34.416 33.642 34.56 ;
    END
  END mul_embed[44]
  PIN mul_embed[45]
    DIRECTION OUTPUT ;
    USE SIGNAL ;
    PORT
      LAYER M5 ;
        RECT  32.928 34.368 32.952 34.56 ;
    END
  END mul_embed[45]
  PIN mul_embed[46]
    DIRECTION OUTPUT ;
    USE SIGNAL ;
    PORT
      LAYER M3 ;
        RECT  33.768 34.416 33.786 34.56 ;
    END
  END mul_embed[46]
  PIN mul_embed[47]
    DIRECTION OUTPUT ;
    USE SIGNAL ;
    PORT
      LAYER M5 ;
        RECT  33.072 34.368 33.096 34.56 ;
    END
  END mul_embed[47]
  PIN mul_embed[48]
    DIRECTION OUTPUT ;
    USE SIGNAL ;
    PORT
      LAYER M3 ;
        RECT  33.912 34.416 33.93 34.56 ;
    END
  END mul_embed[48]
  PIN mul_embed[49]
    DIRECTION OUTPUT ;
    USE SIGNAL ;
    PORT
      LAYER M5 ;
        RECT  33.216 34.368 33.24 34.56 ;
    END
  END mul_embed[49]
  PIN mul_embed[4]
    DIRECTION OUTPUT ;
    USE SIGNAL ;
    PORT
      LAYER M3 ;
        RECT  30.744 34.416 30.762 34.56 ;
    END
  END mul_embed[4]
  PIN mul_embed[50]
    DIRECTION OUTPUT ;
    USE SIGNAL ;
    PORT
      LAYER M3 ;
        RECT  34.056 34.416 34.074 34.56 ;
    END
  END mul_embed[50]
  PIN mul_embed[51]
    DIRECTION OUTPUT ;
    USE SIGNAL ;
    PORT
      LAYER M5 ;
        RECT  33.36 34.368 33.384 34.56 ;
    END
  END mul_embed[51]
  PIN mul_embed[52]
    DIRECTION OUTPUT ;
    USE SIGNAL ;
    PORT
      LAYER M3 ;
        RECT  34.2 34.416 34.218 34.56 ;
    END
  END mul_embed[52]
  PIN mul_embed[53]
    DIRECTION OUTPUT ;
    USE SIGNAL ;
    PORT
      LAYER M5 ;
        RECT  33.504 34.368 33.528 34.56 ;
    END
  END mul_embed[53]
  PIN mul_embed[54]
    DIRECTION OUTPUT ;
    USE SIGNAL ;
    PORT
      LAYER M3 ;
        RECT  34.344 34.416 34.362 34.56 ;
    END
  END mul_embed[54]
  PIN mul_embed[55]
    DIRECTION OUTPUT ;
    USE SIGNAL ;
    PORT
      LAYER M5 ;
        RECT  33.648 34.368 33.672 34.56 ;
    END
  END mul_embed[55]
  PIN mul_embed[56]
    DIRECTION OUTPUT ;
    USE SIGNAL ;
    PORT
      LAYER M3 ;
        RECT  34.488 34.416 34.506 34.56 ;
    END
  END mul_embed[56]
  PIN mul_embed[57]
    DIRECTION OUTPUT ;
    USE SIGNAL ;
    PORT
      LAYER M5 ;
        RECT  33.792 34.368 33.816 34.56 ;
    END
  END mul_embed[57]
  PIN mul_embed[58]
    DIRECTION OUTPUT ;
    USE SIGNAL ;
    PORT
      LAYER M3 ;
        RECT  34.632 34.416 34.65 34.56 ;
    END
  END mul_embed[58]
  PIN mul_embed[59]
    DIRECTION OUTPUT ;
    USE SIGNAL ;
    PORT
      LAYER M5 ;
        RECT  33.936 34.368 33.96 34.56 ;
    END
  END mul_embed[59]
  PIN mul_embed[5]
    DIRECTION OUTPUT ;
    USE SIGNAL ;
    PORT
      LAYER M5 ;
        RECT  30.048 34.368 30.072 34.56 ;
    END
  END mul_embed[5]
  PIN mul_embed[60]
    DIRECTION OUTPUT ;
    USE SIGNAL ;
    PORT
      LAYER M3 ;
        RECT  34.776 34.416 34.794 34.56 ;
    END
  END mul_embed[60]
  PIN mul_embed[61]
    DIRECTION OUTPUT ;
    USE SIGNAL ;
    PORT
      LAYER M5 ;
        RECT  34.08 34.368 34.104 34.56 ;
    END
  END mul_embed[61]
  PIN mul_embed[62]
    DIRECTION OUTPUT ;
    USE SIGNAL ;
    PORT
      LAYER M3 ;
        RECT  34.92 34.416 34.938 34.56 ;
    END
  END mul_embed[62]
  PIN mul_embed[63]
    DIRECTION OUTPUT ;
    USE SIGNAL ;
    PORT
      LAYER M5 ;
        RECT  34.224 34.368 34.248 34.56 ;
    END
  END mul_embed[63]
  PIN mul_embed[64]
    DIRECTION OUTPUT ;
    USE SIGNAL ;
    PORT
      LAYER M3 ;
        RECT  35.064 34.416 35.082 34.56 ;
    END
  END mul_embed[64]
  PIN mul_embed[65]
    DIRECTION OUTPUT ;
    USE SIGNAL ;
    PORT
      LAYER M5 ;
        RECT  34.368 34.368 34.392 34.56 ;
    END
  END mul_embed[65]
  PIN mul_embed[66]
    DIRECTION OUTPUT ;
    USE SIGNAL ;
    PORT
      LAYER M3 ;
        RECT  35.208 34.416 35.226 34.56 ;
    END
  END mul_embed[66]
  PIN mul_embed[67]
    DIRECTION OUTPUT ;
    USE SIGNAL ;
    PORT
      LAYER M5 ;
        RECT  34.512 34.368 34.536 34.56 ;
    END
  END mul_embed[67]
  PIN mul_embed[68]
    DIRECTION OUTPUT ;
    USE SIGNAL ;
    PORT
      LAYER M3 ;
        RECT  35.352 34.416 35.37 34.56 ;
    END
  END mul_embed[68]
  PIN mul_embed[69]
    DIRECTION OUTPUT ;
    USE SIGNAL ;
    PORT
      LAYER M5 ;
        RECT  34.656 34.368 34.68 34.56 ;
    END
  END mul_embed[69]
  PIN mul_embed[6]
    DIRECTION OUTPUT ;
    USE SIGNAL ;
    PORT
      LAYER M3 ;
        RECT  30.888 34.416 30.906 34.56 ;
    END
  END mul_embed[6]
  PIN mul_embed[70]
    DIRECTION OUTPUT ;
    USE SIGNAL ;
    PORT
      LAYER M3 ;
        RECT  35.496 34.416 35.514 34.56 ;
    END
  END mul_embed[70]
  PIN mul_embed[71]
    DIRECTION OUTPUT ;
    USE SIGNAL ;
    PORT
      LAYER M5 ;
        RECT  34.8 34.368 34.824 34.56 ;
    END
  END mul_embed[71]
  PIN mul_embed[72]
    DIRECTION OUTPUT ;
    USE SIGNAL ;
    PORT
      LAYER M3 ;
        RECT  35.64 34.416 35.658 34.56 ;
    END
  END mul_embed[72]
  PIN mul_embed[73]
    DIRECTION OUTPUT ;
    USE SIGNAL ;
    PORT
      LAYER M5 ;
        RECT  34.944 34.368 34.968 34.56 ;
    END
  END mul_embed[73]
  PIN mul_embed[74]
    DIRECTION OUTPUT ;
    USE SIGNAL ;
    PORT
      LAYER M3 ;
        RECT  35.784 34.416 35.802 34.56 ;
    END
  END mul_embed[74]
  PIN mul_embed[75]
    DIRECTION OUTPUT ;
    USE SIGNAL ;
    PORT
      LAYER M5 ;
        RECT  35.088 34.368 35.112 34.56 ;
    END
  END mul_embed[75]
  PIN mul_embed[76]
    DIRECTION OUTPUT ;
    USE SIGNAL ;
    PORT
      LAYER M3 ;
        RECT  35.928 34.416 35.946 34.56 ;
    END
  END mul_embed[76]
  PIN mul_embed[77]
    DIRECTION OUTPUT ;
    USE SIGNAL ;
    PORT
      LAYER M5 ;
        RECT  35.232 34.368 35.256 34.56 ;
    END
  END mul_embed[77]
  PIN mul_embed[78]
    DIRECTION OUTPUT ;
    USE SIGNAL ;
    PORT
      LAYER M3 ;
        RECT  36.072 34.416 36.09 34.56 ;
    END
  END mul_embed[78]
  PIN mul_embed[79]
    DIRECTION OUTPUT ;
    USE SIGNAL ;
    PORT
      LAYER M5 ;
        RECT  35.376 34.368 35.4 34.56 ;
    END
  END mul_embed[79]
  PIN mul_embed[7]
    DIRECTION OUTPUT ;
    USE SIGNAL ;
    PORT
      LAYER M5 ;
        RECT  30.192 34.368 30.216 34.56 ;
    END
  END mul_embed[7]
  PIN mul_embed[80]
    DIRECTION OUTPUT ;
    USE SIGNAL ;
    PORT
      LAYER M3 ;
        RECT  36.216 34.416 36.234 34.56 ;
    END
  END mul_embed[80]
  PIN mul_embed[81]
    DIRECTION OUTPUT ;
    USE SIGNAL ;
    PORT
      LAYER M5 ;
        RECT  35.52 34.368 35.544 34.56 ;
    END
  END mul_embed[81]
  PIN mul_embed[82]
    DIRECTION OUTPUT ;
    USE SIGNAL ;
    PORT
      LAYER M3 ;
        RECT  36.36 34.416 36.378 34.56 ;
    END
  END mul_embed[82]
  PIN mul_embed[83]
    DIRECTION OUTPUT ;
    USE SIGNAL ;
    PORT
      LAYER M5 ;
        RECT  35.664 34.368 35.688 34.56 ;
    END
  END mul_embed[83]
  PIN mul_embed[84]
    DIRECTION OUTPUT ;
    USE SIGNAL ;
    PORT
      LAYER M3 ;
        RECT  36.504 34.416 36.522 34.56 ;
    END
  END mul_embed[84]
  PIN mul_embed[85]
    DIRECTION OUTPUT ;
    USE SIGNAL ;
    PORT
      LAYER M5 ;
        RECT  35.808 34.368 35.832 34.56 ;
    END
  END mul_embed[85]
  PIN mul_embed[86]
    DIRECTION OUTPUT ;
    USE SIGNAL ;
    PORT
      LAYER M3 ;
        RECT  36.648 34.416 36.666 34.56 ;
    END
  END mul_embed[86]
  PIN mul_embed[87]
    DIRECTION OUTPUT ;
    USE SIGNAL ;
    PORT
      LAYER M5 ;
        RECT  35.952 34.368 35.976 34.56 ;
    END
  END mul_embed[87]
  PIN mul_embed[88]
    DIRECTION OUTPUT ;
    USE SIGNAL ;
    PORT
      LAYER M3 ;
        RECT  36.792 34.416 36.81 34.56 ;
    END
  END mul_embed[88]
  PIN mul_embed[89]
    DIRECTION OUTPUT ;
    USE SIGNAL ;
    PORT
      LAYER M5 ;
        RECT  36.096 34.368 36.12 34.56 ;
    END
  END mul_embed[89]
  PIN mul_embed[8]
    DIRECTION OUTPUT ;
    USE SIGNAL ;
    PORT
      LAYER M3 ;
        RECT  31.032 34.416 31.05 34.56 ;
    END
  END mul_embed[8]
  PIN mul_embed[90]
    DIRECTION OUTPUT ;
    USE SIGNAL ;
    PORT
      LAYER M3 ;
        RECT  36.936 34.416 36.954 34.56 ;
    END
  END mul_embed[90]
  PIN mul_embed[91]
    DIRECTION OUTPUT ;
    USE SIGNAL ;
    PORT
      LAYER M5 ;
        RECT  36.24 34.368 36.264 34.56 ;
    END
  END mul_embed[91]
  PIN mul_embed[92]
    DIRECTION OUTPUT ;
    USE SIGNAL ;
    PORT
      LAYER M3 ;
        RECT  37.08 34.416 37.098 34.56 ;
    END
  END mul_embed[92]
  PIN mul_embed[93]
    DIRECTION OUTPUT ;
    USE SIGNAL ;
    PORT
      LAYER M5 ;
        RECT  36.384 34.368 36.408 34.56 ;
    END
  END mul_embed[93]
  PIN mul_embed[94]
    DIRECTION OUTPUT ;
    USE SIGNAL ;
    PORT
      LAYER M3 ;
        RECT  37.224 34.416 37.242 34.56 ;
    END
  END mul_embed[94]
  PIN mul_embed[95]
    DIRECTION OUTPUT ;
    USE SIGNAL ;
    PORT
      LAYER M5 ;
        RECT  36.528 34.368 36.552 34.56 ;
    END
  END mul_embed[95]
  PIN mul_embed[96]
    DIRECTION OUTPUT ;
    USE SIGNAL ;
    PORT
      LAYER M3 ;
        RECT  37.368 34.416 37.386 34.56 ;
    END
  END mul_embed[96]
  PIN mul_embed[97]
    DIRECTION OUTPUT ;
    USE SIGNAL ;
    PORT
      LAYER M5 ;
        RECT  36.672 34.368 36.696 34.56 ;
    END
  END mul_embed[97]
  PIN mul_embed[98]
    DIRECTION OUTPUT ;
    USE SIGNAL ;
    PORT
      LAYER M3 ;
        RECT  37.512 34.416 37.53 34.56 ;
    END
  END mul_embed[98]
  PIN mul_embed[99]
    DIRECTION OUTPUT ;
    USE SIGNAL ;
    PORT
      LAYER M5 ;
        RECT  36.816 34.368 36.84 34.56 ;
    END
  END mul_embed[99]
  PIN mul_embed[9]
    DIRECTION OUTPUT ;
    USE SIGNAL ;
    PORT
      LAYER M5 ;
        RECT  30.336 34.368 30.36 34.56 ;
    END
  END mul_embed[9]
  PIN mul_fire
    DIRECTION OUTPUT ;
    USE SIGNAL ;
    PORT
      LAYER M3 ;
        RECT  11.88 34.416 11.898 34.56 ;
    END
  END mul_fire
  PIN mul_weight[0]
    DIRECTION OUTPUT ;
    USE SIGNAL ;
    PORT
      LAYER M3 ;
        RECT  12.024 34.416 12.042 34.56 ;
    END
  END mul_weight[0]
  PIN mul_weight[100]
    DIRECTION OUTPUT ;
    USE SIGNAL ;
    PORT
      LAYER M3 ;
        RECT  19.224 34.416 19.242 34.56 ;
    END
  END mul_weight[100]
  PIN mul_weight[101]
    DIRECTION OUTPUT ;
    USE SIGNAL ;
    PORT
      LAYER M5 ;
        RECT  18.528 34.368 18.552 34.56 ;
    END
  END mul_weight[101]
  PIN mul_weight[102]
    DIRECTION OUTPUT ;
    USE SIGNAL ;
    PORT
      LAYER M3 ;
        RECT  19.368 34.416 19.386 34.56 ;
    END
  END mul_weight[102]
  PIN mul_weight[103]
    DIRECTION OUTPUT ;
    USE SIGNAL ;
    PORT
      LAYER M5 ;
        RECT  18.672 34.368 18.696 34.56 ;
    END
  END mul_weight[103]
  PIN mul_weight[104]
    DIRECTION OUTPUT ;
    USE SIGNAL ;
    PORT
      LAYER M3 ;
        RECT  19.512 34.416 19.53 34.56 ;
    END
  END mul_weight[104]
  PIN mul_weight[105]
    DIRECTION OUTPUT ;
    USE SIGNAL ;
    PORT
      LAYER M5 ;
        RECT  18.816 34.368 18.84 34.56 ;
    END
  END mul_weight[105]
  PIN mul_weight[106]
    DIRECTION OUTPUT ;
    USE SIGNAL ;
    PORT
      LAYER M3 ;
        RECT  19.656 34.416 19.674 34.56 ;
    END
  END mul_weight[106]
  PIN mul_weight[107]
    DIRECTION OUTPUT ;
    USE SIGNAL ;
    PORT
      LAYER M5 ;
        RECT  18.96 34.368 18.984 34.56 ;
    END
  END mul_weight[107]
  PIN mul_weight[108]
    DIRECTION OUTPUT ;
    USE SIGNAL ;
    PORT
      LAYER M3 ;
        RECT  19.8 34.416 19.818 34.56 ;
    END
  END mul_weight[108]
  PIN mul_weight[109]
    DIRECTION OUTPUT ;
    USE SIGNAL ;
    PORT
      LAYER M5 ;
        RECT  19.104 34.368 19.128 34.56 ;
    END
  END mul_weight[109]
  PIN mul_weight[10]
    DIRECTION OUTPUT ;
    USE SIGNAL ;
    PORT
      LAYER M3 ;
        RECT  12.744 34.416 12.762 34.56 ;
    END
  END mul_weight[10]
  PIN mul_weight[110]
    DIRECTION OUTPUT ;
    USE SIGNAL ;
    PORT
      LAYER M3 ;
        RECT  19.944 34.416 19.962 34.56 ;
    END
  END mul_weight[110]
  PIN mul_weight[111]
    DIRECTION OUTPUT ;
    USE SIGNAL ;
    PORT
      LAYER M5 ;
        RECT  19.248 34.368 19.272 34.56 ;
    END
  END mul_weight[111]
  PIN mul_weight[112]
    DIRECTION OUTPUT ;
    USE SIGNAL ;
    PORT
      LAYER M3 ;
        RECT  20.088 34.416 20.106 34.56 ;
    END
  END mul_weight[112]
  PIN mul_weight[113]
    DIRECTION OUTPUT ;
    USE SIGNAL ;
    PORT
      LAYER M5 ;
        RECT  19.392 34.368 19.416 34.56 ;
    END
  END mul_weight[113]
  PIN mul_weight[114]
    DIRECTION OUTPUT ;
    USE SIGNAL ;
    PORT
      LAYER M3 ;
        RECT  20.232 34.416 20.25 34.56 ;
    END
  END mul_weight[114]
  PIN mul_weight[115]
    DIRECTION OUTPUT ;
    USE SIGNAL ;
    PORT
      LAYER M5 ;
        RECT  19.536 34.368 19.56 34.56 ;
    END
  END mul_weight[115]
  PIN mul_weight[116]
    DIRECTION OUTPUT ;
    USE SIGNAL ;
    PORT
      LAYER M3 ;
        RECT  20.376 34.416 20.394 34.56 ;
    END
  END mul_weight[116]
  PIN mul_weight[117]
    DIRECTION OUTPUT ;
    USE SIGNAL ;
    PORT
      LAYER M5 ;
        RECT  19.68 34.368 19.704 34.56 ;
    END
  END mul_weight[117]
  PIN mul_weight[118]
    DIRECTION OUTPUT ;
    USE SIGNAL ;
    PORT
      LAYER M3 ;
        RECT  20.52 34.416 20.538 34.56 ;
    END
  END mul_weight[118]
  PIN mul_weight[119]
    DIRECTION OUTPUT ;
    USE SIGNAL ;
    PORT
      LAYER M5 ;
        RECT  19.824 34.368 19.848 34.56 ;
    END
  END mul_weight[119]
  PIN mul_weight[11]
    DIRECTION OUTPUT ;
    USE SIGNAL ;
    PORT
      LAYER M5 ;
        RECT  12.048 34.368 12.072 34.56 ;
    END
  END mul_weight[11]
  PIN mul_weight[120]
    DIRECTION OUTPUT ;
    USE SIGNAL ;
    PORT
      LAYER M3 ;
        RECT  20.664 34.416 20.682 34.56 ;
    END
  END mul_weight[120]
  PIN mul_weight[121]
    DIRECTION OUTPUT ;
    USE SIGNAL ;
    PORT
      LAYER M5 ;
        RECT  19.968 34.368 19.992 34.56 ;
    END
  END mul_weight[121]
  PIN mul_weight[122]
    DIRECTION OUTPUT ;
    USE SIGNAL ;
    PORT
      LAYER M3 ;
        RECT  20.808 34.416 20.826 34.56 ;
    END
  END mul_weight[122]
  PIN mul_weight[123]
    DIRECTION OUTPUT ;
    USE SIGNAL ;
    PORT
      LAYER M5 ;
        RECT  20.112 34.368 20.136 34.56 ;
    END
  END mul_weight[123]
  PIN mul_weight[124]
    DIRECTION OUTPUT ;
    USE SIGNAL ;
    PORT
      LAYER M3 ;
        RECT  20.952 34.416 20.97 34.56 ;
    END
  END mul_weight[124]
  PIN mul_weight[125]
    DIRECTION OUTPUT ;
    USE SIGNAL ;
    PORT
      LAYER M5 ;
        RECT  20.256 34.368 20.28 34.56 ;
    END
  END mul_weight[125]
  PIN mul_weight[126]
    DIRECTION OUTPUT ;
    USE SIGNAL ;
    PORT
      LAYER M3 ;
        RECT  21.096 34.416 21.114 34.56 ;
    END
  END mul_weight[126]
  PIN mul_weight[127]
    DIRECTION OUTPUT ;
    USE SIGNAL ;
    PORT
      LAYER M5 ;
        RECT  20.4 34.368 20.424 34.56 ;
    END
  END mul_weight[127]
  PIN mul_weight[128]
    DIRECTION OUTPUT ;
    USE SIGNAL ;
    PORT
      LAYER M3 ;
        RECT  21.24 34.416 21.258 34.56 ;
    END
  END mul_weight[128]
  PIN mul_weight[129]
    DIRECTION OUTPUT ;
    USE SIGNAL ;
    PORT
      LAYER M5 ;
        RECT  20.544 34.368 20.568 34.56 ;
    END
  END mul_weight[129]
  PIN mul_weight[12]
    DIRECTION OUTPUT ;
    USE SIGNAL ;
    PORT
      LAYER M3 ;
        RECT  12.888 34.416 12.906 34.56 ;
    END
  END mul_weight[12]
  PIN mul_weight[130]
    DIRECTION OUTPUT ;
    USE SIGNAL ;
    PORT
      LAYER M3 ;
        RECT  21.384 34.416 21.402 34.56 ;
    END
  END mul_weight[130]
  PIN mul_weight[131]
    DIRECTION OUTPUT ;
    USE SIGNAL ;
    PORT
      LAYER M5 ;
        RECT  20.688 34.368 20.712 34.56 ;
    END
  END mul_weight[131]
  PIN mul_weight[132]
    DIRECTION OUTPUT ;
    USE SIGNAL ;
    PORT
      LAYER M3 ;
        RECT  21.528 34.416 21.546 34.56 ;
    END
  END mul_weight[132]
  PIN mul_weight[133]
    DIRECTION OUTPUT ;
    USE SIGNAL ;
    PORT
      LAYER M5 ;
        RECT  20.832 34.368 20.856 34.56 ;
    END
  END mul_weight[133]
  PIN mul_weight[134]
    DIRECTION OUTPUT ;
    USE SIGNAL ;
    PORT
      LAYER M3 ;
        RECT  21.672 34.416 21.69 34.56 ;
    END
  END mul_weight[134]
  PIN mul_weight[135]
    DIRECTION OUTPUT ;
    USE SIGNAL ;
    PORT
      LAYER M5 ;
        RECT  20.976 34.368 21 34.56 ;
    END
  END mul_weight[135]
  PIN mul_weight[136]
    DIRECTION OUTPUT ;
    USE SIGNAL ;
    PORT
      LAYER M3 ;
        RECT  21.816 34.416 21.834 34.56 ;
    END
  END mul_weight[136]
  PIN mul_weight[137]
    DIRECTION OUTPUT ;
    USE SIGNAL ;
    PORT
      LAYER M5 ;
        RECT  21.12 34.368 21.144 34.56 ;
    END
  END mul_weight[137]
  PIN mul_weight[138]
    DIRECTION OUTPUT ;
    USE SIGNAL ;
    PORT
      LAYER M3 ;
        RECT  21.96 34.416 21.978 34.56 ;
    END
  END mul_weight[138]
  PIN mul_weight[139]
    DIRECTION OUTPUT ;
    USE SIGNAL ;
    PORT
      LAYER M5 ;
        RECT  21.264 34.368 21.288 34.56 ;
    END
  END mul_weight[139]
  PIN mul_weight[13]
    DIRECTION OUTPUT ;
    USE SIGNAL ;
    PORT
      LAYER M5 ;
        RECT  12.192 34.368 12.216 34.56 ;
    END
  END mul_weight[13]
  PIN mul_weight[140]
    DIRECTION OUTPUT ;
    USE SIGNAL ;
    PORT
      LAYER M3 ;
        RECT  22.104 34.416 22.122 34.56 ;
    END
  END mul_weight[140]
  PIN mul_weight[141]
    DIRECTION OUTPUT ;
    USE SIGNAL ;
    PORT
      LAYER M5 ;
        RECT  21.408 34.368 21.432 34.56 ;
    END
  END mul_weight[141]
  PIN mul_weight[142]
    DIRECTION OUTPUT ;
    USE SIGNAL ;
    PORT
      LAYER M3 ;
        RECT  22.248 34.416 22.266 34.56 ;
    END
  END mul_weight[142]
  PIN mul_weight[143]
    DIRECTION OUTPUT ;
    USE SIGNAL ;
    PORT
      LAYER M5 ;
        RECT  21.552 34.368 21.576 34.56 ;
    END
  END mul_weight[143]
  PIN mul_weight[144]
    DIRECTION OUTPUT ;
    USE SIGNAL ;
    PORT
      LAYER M3 ;
        RECT  22.392 34.416 22.41 34.56 ;
    END
  END mul_weight[144]
  PIN mul_weight[145]
    DIRECTION OUTPUT ;
    USE SIGNAL ;
    PORT
      LAYER M5 ;
        RECT  21.696 34.368 21.72 34.56 ;
    END
  END mul_weight[145]
  PIN mul_weight[146]
    DIRECTION OUTPUT ;
    USE SIGNAL ;
    PORT
      LAYER M3 ;
        RECT  22.536 34.416 22.554 34.56 ;
    END
  END mul_weight[146]
  PIN mul_weight[147]
    DIRECTION OUTPUT ;
    USE SIGNAL ;
    PORT
      LAYER M5 ;
        RECT  21.84 34.368 21.864 34.56 ;
    END
  END mul_weight[147]
  PIN mul_weight[148]
    DIRECTION OUTPUT ;
    USE SIGNAL ;
    PORT
      LAYER M3 ;
        RECT  22.68 34.416 22.698 34.56 ;
    END
  END mul_weight[148]
  PIN mul_weight[149]
    DIRECTION OUTPUT ;
    USE SIGNAL ;
    PORT
      LAYER M5 ;
        RECT  21.984 34.368 22.008 34.56 ;
    END
  END mul_weight[149]
  PIN mul_weight[14]
    DIRECTION OUTPUT ;
    USE SIGNAL ;
    PORT
      LAYER M3 ;
        RECT  13.032 34.416 13.05 34.56 ;
    END
  END mul_weight[14]
  PIN mul_weight[150]
    DIRECTION OUTPUT ;
    USE SIGNAL ;
    PORT
      LAYER M3 ;
        RECT  22.824 34.416 22.842 34.56 ;
    END
  END mul_weight[150]
  PIN mul_weight[151]
    DIRECTION OUTPUT ;
    USE SIGNAL ;
    PORT
      LAYER M5 ;
        RECT  22.128 34.368 22.152 34.56 ;
    END
  END mul_weight[151]
  PIN mul_weight[152]
    DIRECTION OUTPUT ;
    USE SIGNAL ;
    PORT
      LAYER M3 ;
        RECT  22.968 34.416 22.986 34.56 ;
    END
  END mul_weight[152]
  PIN mul_weight[153]
    DIRECTION OUTPUT ;
    USE SIGNAL ;
    PORT
      LAYER M5 ;
        RECT  22.272 34.368 22.296 34.56 ;
    END
  END mul_weight[153]
  PIN mul_weight[154]
    DIRECTION OUTPUT ;
    USE SIGNAL ;
    PORT
      LAYER M3 ;
        RECT  23.112 34.416 23.13 34.56 ;
    END
  END mul_weight[154]
  PIN mul_weight[155]
    DIRECTION OUTPUT ;
    USE SIGNAL ;
    PORT
      LAYER M5 ;
        RECT  22.416 34.368 22.44 34.56 ;
    END
  END mul_weight[155]
  PIN mul_weight[156]
    DIRECTION OUTPUT ;
    USE SIGNAL ;
    PORT
      LAYER M3 ;
        RECT  23.256 34.416 23.274 34.56 ;
    END
  END mul_weight[156]
  PIN mul_weight[157]
    DIRECTION OUTPUT ;
    USE SIGNAL ;
    PORT
      LAYER M5 ;
        RECT  22.56 34.368 22.584 34.56 ;
    END
  END mul_weight[157]
  PIN mul_weight[158]
    DIRECTION OUTPUT ;
    USE SIGNAL ;
    PORT
      LAYER M3 ;
        RECT  23.4 34.416 23.418 34.56 ;
    END
  END mul_weight[158]
  PIN mul_weight[159]
    DIRECTION OUTPUT ;
    USE SIGNAL ;
    PORT
      LAYER M5 ;
        RECT  22.704 34.368 22.728 34.56 ;
    END
  END mul_weight[159]
  PIN mul_weight[15]
    DIRECTION OUTPUT ;
    USE SIGNAL ;
    PORT
      LAYER M5 ;
        RECT  12.336 34.368 12.36 34.56 ;
    END
  END mul_weight[15]
  PIN mul_weight[160]
    DIRECTION OUTPUT ;
    USE SIGNAL ;
    PORT
      LAYER M3 ;
        RECT  23.544 34.416 23.562 34.56 ;
    END
  END mul_weight[160]
  PIN mul_weight[161]
    DIRECTION OUTPUT ;
    USE SIGNAL ;
    PORT
      LAYER M5 ;
        RECT  22.848 34.368 22.872 34.56 ;
    END
  END mul_weight[161]
  PIN mul_weight[162]
    DIRECTION OUTPUT ;
    USE SIGNAL ;
    PORT
      LAYER M3 ;
        RECT  23.688 34.416 23.706 34.56 ;
    END
  END mul_weight[162]
  PIN mul_weight[163]
    DIRECTION OUTPUT ;
    USE SIGNAL ;
    PORT
      LAYER M5 ;
        RECT  22.992 34.368 23.016 34.56 ;
    END
  END mul_weight[163]
  PIN mul_weight[164]
    DIRECTION OUTPUT ;
    USE SIGNAL ;
    PORT
      LAYER M3 ;
        RECT  23.832 34.416 23.85 34.56 ;
    END
  END mul_weight[164]
  PIN mul_weight[165]
    DIRECTION OUTPUT ;
    USE SIGNAL ;
    PORT
      LAYER M5 ;
        RECT  23.136 34.368 23.16 34.56 ;
    END
  END mul_weight[165]
  PIN mul_weight[166]
    DIRECTION OUTPUT ;
    USE SIGNAL ;
    PORT
      LAYER M3 ;
        RECT  23.976 34.416 23.994 34.56 ;
    END
  END mul_weight[166]
  PIN mul_weight[167]
    DIRECTION OUTPUT ;
    USE SIGNAL ;
    PORT
      LAYER M5 ;
        RECT  23.28 34.368 23.304 34.56 ;
    END
  END mul_weight[167]
  PIN mul_weight[168]
    DIRECTION OUTPUT ;
    USE SIGNAL ;
    PORT
      LAYER M3 ;
        RECT  24.12 34.416 24.138 34.56 ;
    END
  END mul_weight[168]
  PIN mul_weight[169]
    DIRECTION OUTPUT ;
    USE SIGNAL ;
    PORT
      LAYER M5 ;
        RECT  23.424 34.368 23.448 34.56 ;
    END
  END mul_weight[169]
  PIN mul_weight[16]
    DIRECTION OUTPUT ;
    USE SIGNAL ;
    PORT
      LAYER M3 ;
        RECT  13.176 34.416 13.194 34.56 ;
    END
  END mul_weight[16]
  PIN mul_weight[170]
    DIRECTION OUTPUT ;
    USE SIGNAL ;
    PORT
      LAYER M3 ;
        RECT  24.264 34.416 24.282 34.56 ;
    END
  END mul_weight[170]
  PIN mul_weight[171]
    DIRECTION OUTPUT ;
    USE SIGNAL ;
    PORT
      LAYER M5 ;
        RECT  23.568 34.368 23.592 34.56 ;
    END
  END mul_weight[171]
  PIN mul_weight[172]
    DIRECTION OUTPUT ;
    USE SIGNAL ;
    PORT
      LAYER M3 ;
        RECT  24.408 34.416 24.426 34.56 ;
    END
  END mul_weight[172]
  PIN mul_weight[173]
    DIRECTION OUTPUT ;
    USE SIGNAL ;
    PORT
      LAYER M5 ;
        RECT  23.712 34.368 23.736 34.56 ;
    END
  END mul_weight[173]
  PIN mul_weight[174]
    DIRECTION OUTPUT ;
    USE SIGNAL ;
    PORT
      LAYER M3 ;
        RECT  24.552 34.416 24.57 34.56 ;
    END
  END mul_weight[174]
  PIN mul_weight[175]
    DIRECTION OUTPUT ;
    USE SIGNAL ;
    PORT
      LAYER M5 ;
        RECT  23.856 34.368 23.88 34.56 ;
    END
  END mul_weight[175]
  PIN mul_weight[176]
    DIRECTION OUTPUT ;
    USE SIGNAL ;
    PORT
      LAYER M3 ;
        RECT  24.696 34.416 24.714 34.56 ;
    END
  END mul_weight[176]
  PIN mul_weight[177]
    DIRECTION OUTPUT ;
    USE SIGNAL ;
    PORT
      LAYER M5 ;
        RECT  24 34.368 24.024 34.56 ;
    END
  END mul_weight[177]
  PIN mul_weight[178]
    DIRECTION OUTPUT ;
    USE SIGNAL ;
    PORT
      LAYER M3 ;
        RECT  24.84 34.416 24.858 34.56 ;
    END
  END mul_weight[178]
  PIN mul_weight[179]
    DIRECTION OUTPUT ;
    USE SIGNAL ;
    PORT
      LAYER M5 ;
        RECT  24.144 34.368 24.168 34.56 ;
    END
  END mul_weight[179]
  PIN mul_weight[17]
    DIRECTION OUTPUT ;
    USE SIGNAL ;
    PORT
      LAYER M5 ;
        RECT  12.48 34.368 12.504 34.56 ;
    END
  END mul_weight[17]
  PIN mul_weight[180]
    DIRECTION OUTPUT ;
    USE SIGNAL ;
    PORT
      LAYER M3 ;
        RECT  24.984 34.416 25.002 34.56 ;
    END
  END mul_weight[180]
  PIN mul_weight[181]
    DIRECTION OUTPUT ;
    USE SIGNAL ;
    PORT
      LAYER M5 ;
        RECT  24.288 34.368 24.312 34.56 ;
    END
  END mul_weight[181]
  PIN mul_weight[182]
    DIRECTION OUTPUT ;
    USE SIGNAL ;
    PORT
      LAYER M3 ;
        RECT  25.128 34.416 25.146 34.56 ;
    END
  END mul_weight[182]
  PIN mul_weight[183]
    DIRECTION OUTPUT ;
    USE SIGNAL ;
    PORT
      LAYER M5 ;
        RECT  24.432 34.368 24.456 34.56 ;
    END
  END mul_weight[183]
  PIN mul_weight[184]
    DIRECTION OUTPUT ;
    USE SIGNAL ;
    PORT
      LAYER M3 ;
        RECT  25.272 34.416 25.29 34.56 ;
    END
  END mul_weight[184]
  PIN mul_weight[185]
    DIRECTION OUTPUT ;
    USE SIGNAL ;
    PORT
      LAYER M5 ;
        RECT  24.576 34.368 24.6 34.56 ;
    END
  END mul_weight[185]
  PIN mul_weight[186]
    DIRECTION OUTPUT ;
    USE SIGNAL ;
    PORT
      LAYER M3 ;
        RECT  25.416 34.416 25.434 34.56 ;
    END
  END mul_weight[186]
  PIN mul_weight[187]
    DIRECTION OUTPUT ;
    USE SIGNAL ;
    PORT
      LAYER M5 ;
        RECT  24.72 34.368 24.744 34.56 ;
    END
  END mul_weight[187]
  PIN mul_weight[188]
    DIRECTION OUTPUT ;
    USE SIGNAL ;
    PORT
      LAYER M3 ;
        RECT  25.56 34.416 25.578 34.56 ;
    END
  END mul_weight[188]
  PIN mul_weight[189]
    DIRECTION OUTPUT ;
    USE SIGNAL ;
    PORT
      LAYER M5 ;
        RECT  24.864 34.368 24.888 34.56 ;
    END
  END mul_weight[189]
  PIN mul_weight[18]
    DIRECTION OUTPUT ;
    USE SIGNAL ;
    PORT
      LAYER M3 ;
        RECT  13.32 34.416 13.338 34.56 ;
    END
  END mul_weight[18]
  PIN mul_weight[190]
    DIRECTION OUTPUT ;
    USE SIGNAL ;
    PORT
      LAYER M3 ;
        RECT  25.704 34.416 25.722 34.56 ;
    END
  END mul_weight[190]
  PIN mul_weight[191]
    DIRECTION OUTPUT ;
    USE SIGNAL ;
    PORT
      LAYER M5 ;
        RECT  25.008 34.368 25.032 34.56 ;
    END
  END mul_weight[191]
  PIN mul_weight[192]
    DIRECTION OUTPUT ;
    USE SIGNAL ;
    PORT
      LAYER M3 ;
        RECT  25.848 34.416 25.866 34.56 ;
    END
  END mul_weight[192]
  PIN mul_weight[193]
    DIRECTION OUTPUT ;
    USE SIGNAL ;
    PORT
      LAYER M5 ;
        RECT  25.152 34.368 25.176 34.56 ;
    END
  END mul_weight[193]
  PIN mul_weight[194]
    DIRECTION OUTPUT ;
    USE SIGNAL ;
    PORT
      LAYER M3 ;
        RECT  25.992 34.416 26.01 34.56 ;
    END
  END mul_weight[194]
  PIN mul_weight[195]
    DIRECTION OUTPUT ;
    USE SIGNAL ;
    PORT
      LAYER M5 ;
        RECT  25.296 34.368 25.32 34.56 ;
    END
  END mul_weight[195]
  PIN mul_weight[196]
    DIRECTION OUTPUT ;
    USE SIGNAL ;
    PORT
      LAYER M3 ;
        RECT  26.136 34.416 26.154 34.56 ;
    END
  END mul_weight[196]
  PIN mul_weight[197]
    DIRECTION OUTPUT ;
    USE SIGNAL ;
    PORT
      LAYER M5 ;
        RECT  25.44 34.368 25.464 34.56 ;
    END
  END mul_weight[197]
  PIN mul_weight[198]
    DIRECTION OUTPUT ;
    USE SIGNAL ;
    PORT
      LAYER M3 ;
        RECT  26.28 34.416 26.298 34.56 ;
    END
  END mul_weight[198]
  PIN mul_weight[199]
    DIRECTION OUTPUT ;
    USE SIGNAL ;
    PORT
      LAYER M5 ;
        RECT  25.584 34.368 25.608 34.56 ;
    END
  END mul_weight[199]
  PIN mul_weight[19]
    DIRECTION OUTPUT ;
    USE SIGNAL ;
    PORT
      LAYER M5 ;
        RECT  12.624 34.368 12.648 34.56 ;
    END
  END mul_weight[19]
  PIN mul_weight[1]
    DIRECTION OUTPUT ;
    USE SIGNAL ;
    PORT
      LAYER M5 ;
        RECT  11.328 34.368 11.352 34.56 ;
    END
  END mul_weight[1]
  PIN mul_weight[200]
    DIRECTION OUTPUT ;
    USE SIGNAL ;
    PORT
      LAYER M3 ;
        RECT  26.424 34.416 26.442 34.56 ;
    END
  END mul_weight[200]
  PIN mul_weight[201]
    DIRECTION OUTPUT ;
    USE SIGNAL ;
    PORT
      LAYER M5 ;
        RECT  25.728 34.368 25.752 34.56 ;
    END
  END mul_weight[201]
  PIN mul_weight[202]
    DIRECTION OUTPUT ;
    USE SIGNAL ;
    PORT
      LAYER M3 ;
        RECT  26.568 34.416 26.586 34.56 ;
    END
  END mul_weight[202]
  PIN mul_weight[203]
    DIRECTION OUTPUT ;
    USE SIGNAL ;
    PORT
      LAYER M5 ;
        RECT  25.872 34.368 25.896 34.56 ;
    END
  END mul_weight[203]
  PIN mul_weight[204]
    DIRECTION OUTPUT ;
    USE SIGNAL ;
    PORT
      LAYER M3 ;
        RECT  26.712 34.416 26.73 34.56 ;
    END
  END mul_weight[204]
  PIN mul_weight[205]
    DIRECTION OUTPUT ;
    USE SIGNAL ;
    PORT
      LAYER M5 ;
        RECT  26.016 34.368 26.04 34.56 ;
    END
  END mul_weight[205]
  PIN mul_weight[206]
    DIRECTION OUTPUT ;
    USE SIGNAL ;
    PORT
      LAYER M3 ;
        RECT  26.856 34.416 26.874 34.56 ;
    END
  END mul_weight[206]
  PIN mul_weight[207]
    DIRECTION OUTPUT ;
    USE SIGNAL ;
    PORT
      LAYER M5 ;
        RECT  26.16 34.368 26.184 34.56 ;
    END
  END mul_weight[207]
  PIN mul_weight[208]
    DIRECTION OUTPUT ;
    USE SIGNAL ;
    PORT
      LAYER M3 ;
        RECT  27 34.416 27.018 34.56 ;
    END
  END mul_weight[208]
  PIN mul_weight[209]
    DIRECTION OUTPUT ;
    USE SIGNAL ;
    PORT
      LAYER M5 ;
        RECT  26.304 34.368 26.328 34.56 ;
    END
  END mul_weight[209]
  PIN mul_weight[20]
    DIRECTION OUTPUT ;
    USE SIGNAL ;
    PORT
      LAYER M3 ;
        RECT  13.464 34.416 13.482 34.56 ;
    END
  END mul_weight[20]
  PIN mul_weight[210]
    DIRECTION OUTPUT ;
    USE SIGNAL ;
    PORT
      LAYER M3 ;
        RECT  27.144 34.416 27.162 34.56 ;
    END
  END mul_weight[210]
  PIN mul_weight[211]
    DIRECTION OUTPUT ;
    USE SIGNAL ;
    PORT
      LAYER M5 ;
        RECT  26.448 34.368 26.472 34.56 ;
    END
  END mul_weight[211]
  PIN mul_weight[212]
    DIRECTION OUTPUT ;
    USE SIGNAL ;
    PORT
      LAYER M3 ;
        RECT  27.288 34.416 27.306 34.56 ;
    END
  END mul_weight[212]
  PIN mul_weight[213]
    DIRECTION OUTPUT ;
    USE SIGNAL ;
    PORT
      LAYER M5 ;
        RECT  26.592 34.368 26.616 34.56 ;
    END
  END mul_weight[213]
  PIN mul_weight[214]
    DIRECTION OUTPUT ;
    USE SIGNAL ;
    PORT
      LAYER M3 ;
        RECT  27.432 34.416 27.45 34.56 ;
    END
  END mul_weight[214]
  PIN mul_weight[215]
    DIRECTION OUTPUT ;
    USE SIGNAL ;
    PORT
      LAYER M5 ;
        RECT  26.736 34.368 26.76 34.56 ;
    END
  END mul_weight[215]
  PIN mul_weight[216]
    DIRECTION OUTPUT ;
    USE SIGNAL ;
    PORT
      LAYER M3 ;
        RECT  27.576 34.416 27.594 34.56 ;
    END
  END mul_weight[216]
  PIN mul_weight[217]
    DIRECTION OUTPUT ;
    USE SIGNAL ;
    PORT
      LAYER M5 ;
        RECT  26.88 34.368 26.904 34.56 ;
    END
  END mul_weight[217]
  PIN mul_weight[218]
    DIRECTION OUTPUT ;
    USE SIGNAL ;
    PORT
      LAYER M3 ;
        RECT  27.72 34.416 27.738 34.56 ;
    END
  END mul_weight[218]
  PIN mul_weight[219]
    DIRECTION OUTPUT ;
    USE SIGNAL ;
    PORT
      LAYER M5 ;
        RECT  27.024 34.368 27.048 34.56 ;
    END
  END mul_weight[219]
  PIN mul_weight[21]
    DIRECTION OUTPUT ;
    USE SIGNAL ;
    PORT
      LAYER M5 ;
        RECT  12.768 34.368 12.792 34.56 ;
    END
  END mul_weight[21]
  PIN mul_weight[220]
    DIRECTION OUTPUT ;
    USE SIGNAL ;
    PORT
      LAYER M3 ;
        RECT  27.864 34.416 27.882 34.56 ;
    END
  END mul_weight[220]
  PIN mul_weight[221]
    DIRECTION OUTPUT ;
    USE SIGNAL ;
    PORT
      LAYER M5 ;
        RECT  27.168 34.368 27.192 34.56 ;
    END
  END mul_weight[221]
  PIN mul_weight[222]
    DIRECTION OUTPUT ;
    USE SIGNAL ;
    PORT
      LAYER M3 ;
        RECT  28.008 34.416 28.026 34.56 ;
    END
  END mul_weight[222]
  PIN mul_weight[223]
    DIRECTION OUTPUT ;
    USE SIGNAL ;
    PORT
      LAYER M5 ;
        RECT  27.312 34.368 27.336 34.56 ;
    END
  END mul_weight[223]
  PIN mul_weight[224]
    DIRECTION OUTPUT ;
    USE SIGNAL ;
    PORT
      LAYER M3 ;
        RECT  28.152 34.416 28.17 34.56 ;
    END
  END mul_weight[224]
  PIN mul_weight[225]
    DIRECTION OUTPUT ;
    USE SIGNAL ;
    PORT
      LAYER M5 ;
        RECT  27.456 34.368 27.48 34.56 ;
    END
  END mul_weight[225]
  PIN mul_weight[226]
    DIRECTION OUTPUT ;
    USE SIGNAL ;
    PORT
      LAYER M3 ;
        RECT  28.296 34.416 28.314 34.56 ;
    END
  END mul_weight[226]
  PIN mul_weight[227]
    DIRECTION OUTPUT ;
    USE SIGNAL ;
    PORT
      LAYER M5 ;
        RECT  27.6 34.368 27.624 34.56 ;
    END
  END mul_weight[227]
  PIN mul_weight[228]
    DIRECTION OUTPUT ;
    USE SIGNAL ;
    PORT
      LAYER M3 ;
        RECT  28.44 34.416 28.458 34.56 ;
    END
  END mul_weight[228]
  PIN mul_weight[229]
    DIRECTION OUTPUT ;
    USE SIGNAL ;
    PORT
      LAYER M5 ;
        RECT  27.744 34.368 27.768 34.56 ;
    END
  END mul_weight[229]
  PIN mul_weight[22]
    DIRECTION OUTPUT ;
    USE SIGNAL ;
    PORT
      LAYER M3 ;
        RECT  13.608 34.416 13.626 34.56 ;
    END
  END mul_weight[22]
  PIN mul_weight[230]
    DIRECTION OUTPUT ;
    USE SIGNAL ;
    PORT
      LAYER M3 ;
        RECT  28.584 34.416 28.602 34.56 ;
    END
  END mul_weight[230]
  PIN mul_weight[231]
    DIRECTION OUTPUT ;
    USE SIGNAL ;
    PORT
      LAYER M5 ;
        RECT  27.888 34.368 27.912 34.56 ;
    END
  END mul_weight[231]
  PIN mul_weight[232]
    DIRECTION OUTPUT ;
    USE SIGNAL ;
    PORT
      LAYER M3 ;
        RECT  28.728 34.416 28.746 34.56 ;
    END
  END mul_weight[232]
  PIN mul_weight[233]
    DIRECTION OUTPUT ;
    USE SIGNAL ;
    PORT
      LAYER M5 ;
        RECT  28.032 34.368 28.056 34.56 ;
    END
  END mul_weight[233]
  PIN mul_weight[234]
    DIRECTION OUTPUT ;
    USE SIGNAL ;
    PORT
      LAYER M3 ;
        RECT  28.872 34.416 28.89 34.56 ;
    END
  END mul_weight[234]
  PIN mul_weight[235]
    DIRECTION OUTPUT ;
    USE SIGNAL ;
    PORT
      LAYER M5 ;
        RECT  28.176 34.368 28.2 34.56 ;
    END
  END mul_weight[235]
  PIN mul_weight[236]
    DIRECTION OUTPUT ;
    USE SIGNAL ;
    PORT
      LAYER M3 ;
        RECT  29.016 34.416 29.034 34.56 ;
    END
  END mul_weight[236]
  PIN mul_weight[237]
    DIRECTION OUTPUT ;
    USE SIGNAL ;
    PORT
      LAYER M5 ;
        RECT  28.32 34.368 28.344 34.56 ;
    END
  END mul_weight[237]
  PIN mul_weight[238]
    DIRECTION OUTPUT ;
    USE SIGNAL ;
    PORT
      LAYER M3 ;
        RECT  29.16 34.416 29.178 34.56 ;
    END
  END mul_weight[238]
  PIN mul_weight[239]
    DIRECTION OUTPUT ;
    USE SIGNAL ;
    PORT
      LAYER M5 ;
        RECT  28.464 34.368 28.488 34.56 ;
    END
  END mul_weight[239]
  PIN mul_weight[23]
    DIRECTION OUTPUT ;
    USE SIGNAL ;
    PORT
      LAYER M5 ;
        RECT  12.912 34.368 12.936 34.56 ;
    END
  END mul_weight[23]
  PIN mul_weight[240]
    DIRECTION OUTPUT ;
    USE SIGNAL ;
    PORT
      LAYER M3 ;
        RECT  29.304 34.416 29.322 34.56 ;
    END
  END mul_weight[240]
  PIN mul_weight[241]
    DIRECTION OUTPUT ;
    USE SIGNAL ;
    PORT
      LAYER M5 ;
        RECT  28.608 34.368 28.632 34.56 ;
    END
  END mul_weight[241]
  PIN mul_weight[242]
    DIRECTION OUTPUT ;
    USE SIGNAL ;
    PORT
      LAYER M3 ;
        RECT  29.448 34.416 29.466 34.56 ;
    END
  END mul_weight[242]
  PIN mul_weight[243]
    DIRECTION OUTPUT ;
    USE SIGNAL ;
    PORT
      LAYER M5 ;
        RECT  28.752 34.368 28.776 34.56 ;
    END
  END mul_weight[243]
  PIN mul_weight[244]
    DIRECTION OUTPUT ;
    USE SIGNAL ;
    PORT
      LAYER M3 ;
        RECT  29.592 34.416 29.61 34.56 ;
    END
  END mul_weight[244]
  PIN mul_weight[245]
    DIRECTION OUTPUT ;
    USE SIGNAL ;
    PORT
      LAYER M5 ;
        RECT  28.896 34.368 28.92 34.56 ;
    END
  END mul_weight[245]
  PIN mul_weight[246]
    DIRECTION OUTPUT ;
    USE SIGNAL ;
    PORT
      LAYER M3 ;
        RECT  29.736 34.416 29.754 34.56 ;
    END
  END mul_weight[246]
  PIN mul_weight[247]
    DIRECTION OUTPUT ;
    USE SIGNAL ;
    PORT
      LAYER M5 ;
        RECT  29.04 34.368 29.064 34.56 ;
    END
  END mul_weight[247]
  PIN mul_weight[248]
    DIRECTION OUTPUT ;
    USE SIGNAL ;
    PORT
      LAYER M3 ;
        RECT  29.88 34.416 29.898 34.56 ;
    END
  END mul_weight[248]
  PIN mul_weight[249]
    DIRECTION OUTPUT ;
    USE SIGNAL ;
    PORT
      LAYER M5 ;
        RECT  29.184 34.368 29.208 34.56 ;
    END
  END mul_weight[249]
  PIN mul_weight[24]
    DIRECTION OUTPUT ;
    USE SIGNAL ;
    PORT
      LAYER M3 ;
        RECT  13.752 34.416 13.77 34.56 ;
    END
  END mul_weight[24]
  PIN mul_weight[250]
    DIRECTION OUTPUT ;
    USE SIGNAL ;
    PORT
      LAYER M3 ;
        RECT  30.024 34.416 30.042 34.56 ;
    END
  END mul_weight[250]
  PIN mul_weight[251]
    DIRECTION OUTPUT ;
    USE SIGNAL ;
    PORT
      LAYER M5 ;
        RECT  29.328 34.368 29.352 34.56 ;
    END
  END mul_weight[251]
  PIN mul_weight[252]
    DIRECTION OUTPUT ;
    USE SIGNAL ;
    PORT
      LAYER M3 ;
        RECT  30.168 34.416 30.186 34.56 ;
    END
  END mul_weight[252]
  PIN mul_weight[253]
    DIRECTION OUTPUT ;
    USE SIGNAL ;
    PORT
      LAYER M5 ;
        RECT  29.472 34.368 29.496 34.56 ;
    END
  END mul_weight[253]
  PIN mul_weight[254]
    DIRECTION OUTPUT ;
    USE SIGNAL ;
    PORT
      LAYER M3 ;
        RECT  30.312 34.416 30.33 34.56 ;
    END
  END mul_weight[254]
  PIN mul_weight[255]
    DIRECTION OUTPUT ;
    USE SIGNAL ;
    PORT
      LAYER M5 ;
        RECT  29.616 34.368 29.64 34.56 ;
    END
  END mul_weight[255]
  PIN mul_weight[25]
    DIRECTION OUTPUT ;
    USE SIGNAL ;
    PORT
      LAYER M5 ;
        RECT  13.056 34.368 13.08 34.56 ;
    END
  END mul_weight[25]
  PIN mul_weight[26]
    DIRECTION OUTPUT ;
    USE SIGNAL ;
    PORT
      LAYER M3 ;
        RECT  13.896 34.416 13.914 34.56 ;
    END
  END mul_weight[26]
  PIN mul_weight[27]
    DIRECTION OUTPUT ;
    USE SIGNAL ;
    PORT
      LAYER M5 ;
        RECT  13.2 34.368 13.224 34.56 ;
    END
  END mul_weight[27]
  PIN mul_weight[28]
    DIRECTION OUTPUT ;
    USE SIGNAL ;
    PORT
      LAYER M3 ;
        RECT  14.04 34.416 14.058 34.56 ;
    END
  END mul_weight[28]
  PIN mul_weight[29]
    DIRECTION OUTPUT ;
    USE SIGNAL ;
    PORT
      LAYER M5 ;
        RECT  13.344 34.368 13.368 34.56 ;
    END
  END mul_weight[29]
  PIN mul_weight[2]
    DIRECTION OUTPUT ;
    USE SIGNAL ;
    PORT
      LAYER M3 ;
        RECT  12.168 34.416 12.186 34.56 ;
    END
  END mul_weight[2]
  PIN mul_weight[30]
    DIRECTION OUTPUT ;
    USE SIGNAL ;
    PORT
      LAYER M3 ;
        RECT  14.184 34.416 14.202 34.56 ;
    END
  END mul_weight[30]
  PIN mul_weight[31]
    DIRECTION OUTPUT ;
    USE SIGNAL ;
    PORT
      LAYER M5 ;
        RECT  13.488 34.368 13.512 34.56 ;
    END
  END mul_weight[31]
  PIN mul_weight[32]
    DIRECTION OUTPUT ;
    USE SIGNAL ;
    PORT
      LAYER M3 ;
        RECT  14.328 34.416 14.346 34.56 ;
    END
  END mul_weight[32]
  PIN mul_weight[33]
    DIRECTION OUTPUT ;
    USE SIGNAL ;
    PORT
      LAYER M5 ;
        RECT  13.632 34.368 13.656 34.56 ;
    END
  END mul_weight[33]
  PIN mul_weight[34]
    DIRECTION OUTPUT ;
    USE SIGNAL ;
    PORT
      LAYER M3 ;
        RECT  14.472 34.416 14.49 34.56 ;
    END
  END mul_weight[34]
  PIN mul_weight[35]
    DIRECTION OUTPUT ;
    USE SIGNAL ;
    PORT
      LAYER M5 ;
        RECT  13.776 34.368 13.8 34.56 ;
    END
  END mul_weight[35]
  PIN mul_weight[36]
    DIRECTION OUTPUT ;
    USE SIGNAL ;
    PORT
      LAYER M3 ;
        RECT  14.616 34.416 14.634 34.56 ;
    END
  END mul_weight[36]
  PIN mul_weight[37]
    DIRECTION OUTPUT ;
    USE SIGNAL ;
    PORT
      LAYER M5 ;
        RECT  13.92 34.368 13.944 34.56 ;
    END
  END mul_weight[37]
  PIN mul_weight[38]
    DIRECTION OUTPUT ;
    USE SIGNAL ;
    PORT
      LAYER M3 ;
        RECT  14.76 34.416 14.778 34.56 ;
    END
  END mul_weight[38]
  PIN mul_weight[39]
    DIRECTION OUTPUT ;
    USE SIGNAL ;
    PORT
      LAYER M5 ;
        RECT  14.064 34.368 14.088 34.56 ;
    END
  END mul_weight[39]
  PIN mul_weight[3]
    DIRECTION OUTPUT ;
    USE SIGNAL ;
    PORT
      LAYER M5 ;
        RECT  11.472 34.368 11.496 34.56 ;
    END
  END mul_weight[3]
  PIN mul_weight[40]
    DIRECTION OUTPUT ;
    USE SIGNAL ;
    PORT
      LAYER M3 ;
        RECT  14.904 34.416 14.922 34.56 ;
    END
  END mul_weight[40]
  PIN mul_weight[41]
    DIRECTION OUTPUT ;
    USE SIGNAL ;
    PORT
      LAYER M5 ;
        RECT  14.208 34.368 14.232 34.56 ;
    END
  END mul_weight[41]
  PIN mul_weight[42]
    DIRECTION OUTPUT ;
    USE SIGNAL ;
    PORT
      LAYER M3 ;
        RECT  15.048 34.416 15.066 34.56 ;
    END
  END mul_weight[42]
  PIN mul_weight[43]
    DIRECTION OUTPUT ;
    USE SIGNAL ;
    PORT
      LAYER M5 ;
        RECT  14.352 34.368 14.376 34.56 ;
    END
  END mul_weight[43]
  PIN mul_weight[44]
    DIRECTION OUTPUT ;
    USE SIGNAL ;
    PORT
      LAYER M3 ;
        RECT  15.192 34.416 15.21 34.56 ;
    END
  END mul_weight[44]
  PIN mul_weight[45]
    DIRECTION OUTPUT ;
    USE SIGNAL ;
    PORT
      LAYER M5 ;
        RECT  14.496 34.368 14.52 34.56 ;
    END
  END mul_weight[45]
  PIN mul_weight[46]
    DIRECTION OUTPUT ;
    USE SIGNAL ;
    PORT
      LAYER M3 ;
        RECT  15.336 34.416 15.354 34.56 ;
    END
  END mul_weight[46]
  PIN mul_weight[47]
    DIRECTION OUTPUT ;
    USE SIGNAL ;
    PORT
      LAYER M5 ;
        RECT  14.64 34.368 14.664 34.56 ;
    END
  END mul_weight[47]
  PIN mul_weight[48]
    DIRECTION OUTPUT ;
    USE SIGNAL ;
    PORT
      LAYER M3 ;
        RECT  15.48 34.416 15.498 34.56 ;
    END
  END mul_weight[48]
  PIN mul_weight[49]
    DIRECTION OUTPUT ;
    USE SIGNAL ;
    PORT
      LAYER M5 ;
        RECT  14.784 34.368 14.808 34.56 ;
    END
  END mul_weight[49]
  PIN mul_weight[4]
    DIRECTION OUTPUT ;
    USE SIGNAL ;
    PORT
      LAYER M3 ;
        RECT  12.312 34.416 12.33 34.56 ;
    END
  END mul_weight[4]
  PIN mul_weight[50]
    DIRECTION OUTPUT ;
    USE SIGNAL ;
    PORT
      LAYER M3 ;
        RECT  15.624 34.416 15.642 34.56 ;
    END
  END mul_weight[50]
  PIN mul_weight[51]
    DIRECTION OUTPUT ;
    USE SIGNAL ;
    PORT
      LAYER M5 ;
        RECT  14.928 34.368 14.952 34.56 ;
    END
  END mul_weight[51]
  PIN mul_weight[52]
    DIRECTION OUTPUT ;
    USE SIGNAL ;
    PORT
      LAYER M3 ;
        RECT  15.768 34.416 15.786 34.56 ;
    END
  END mul_weight[52]
  PIN mul_weight[53]
    DIRECTION OUTPUT ;
    USE SIGNAL ;
    PORT
      LAYER M5 ;
        RECT  15.072 34.368 15.096 34.56 ;
    END
  END mul_weight[53]
  PIN mul_weight[54]
    DIRECTION OUTPUT ;
    USE SIGNAL ;
    PORT
      LAYER M3 ;
        RECT  15.912 34.416 15.93 34.56 ;
    END
  END mul_weight[54]
  PIN mul_weight[55]
    DIRECTION OUTPUT ;
    USE SIGNAL ;
    PORT
      LAYER M5 ;
        RECT  15.216 34.368 15.24 34.56 ;
    END
  END mul_weight[55]
  PIN mul_weight[56]
    DIRECTION OUTPUT ;
    USE SIGNAL ;
    PORT
      LAYER M3 ;
        RECT  16.056 34.416 16.074 34.56 ;
    END
  END mul_weight[56]
  PIN mul_weight[57]
    DIRECTION OUTPUT ;
    USE SIGNAL ;
    PORT
      LAYER M5 ;
        RECT  15.36 34.368 15.384 34.56 ;
    END
  END mul_weight[57]
  PIN mul_weight[58]
    DIRECTION OUTPUT ;
    USE SIGNAL ;
    PORT
      LAYER M3 ;
        RECT  16.2 34.416 16.218 34.56 ;
    END
  END mul_weight[58]
  PIN mul_weight[59]
    DIRECTION OUTPUT ;
    USE SIGNAL ;
    PORT
      LAYER M5 ;
        RECT  15.504 34.368 15.528 34.56 ;
    END
  END mul_weight[59]
  PIN mul_weight[5]
    DIRECTION OUTPUT ;
    USE SIGNAL ;
    PORT
      LAYER M5 ;
        RECT  11.616 34.368 11.64 34.56 ;
    END
  END mul_weight[5]
  PIN mul_weight[60]
    DIRECTION OUTPUT ;
    USE SIGNAL ;
    PORT
      LAYER M3 ;
        RECT  16.344 34.416 16.362 34.56 ;
    END
  END mul_weight[60]
  PIN mul_weight[61]
    DIRECTION OUTPUT ;
    USE SIGNAL ;
    PORT
      LAYER M5 ;
        RECT  15.648 34.368 15.672 34.56 ;
    END
  END mul_weight[61]
  PIN mul_weight[62]
    DIRECTION OUTPUT ;
    USE SIGNAL ;
    PORT
      LAYER M3 ;
        RECT  16.488 34.416 16.506 34.56 ;
    END
  END mul_weight[62]
  PIN mul_weight[63]
    DIRECTION OUTPUT ;
    USE SIGNAL ;
    PORT
      LAYER M5 ;
        RECT  15.792 34.368 15.816 34.56 ;
    END
  END mul_weight[63]
  PIN mul_weight[64]
    DIRECTION OUTPUT ;
    USE SIGNAL ;
    PORT
      LAYER M3 ;
        RECT  16.632 34.416 16.65 34.56 ;
    END
  END mul_weight[64]
  PIN mul_weight[65]
    DIRECTION OUTPUT ;
    USE SIGNAL ;
    PORT
      LAYER M5 ;
        RECT  15.936 34.368 15.96 34.56 ;
    END
  END mul_weight[65]
  PIN mul_weight[66]
    DIRECTION OUTPUT ;
    USE SIGNAL ;
    PORT
      LAYER M3 ;
        RECT  16.776 34.416 16.794 34.56 ;
    END
  END mul_weight[66]
  PIN mul_weight[67]
    DIRECTION OUTPUT ;
    USE SIGNAL ;
    PORT
      LAYER M5 ;
        RECT  16.08 34.368 16.104 34.56 ;
    END
  END mul_weight[67]
  PIN mul_weight[68]
    DIRECTION OUTPUT ;
    USE SIGNAL ;
    PORT
      LAYER M3 ;
        RECT  16.92 34.416 16.938 34.56 ;
    END
  END mul_weight[68]
  PIN mul_weight[69]
    DIRECTION OUTPUT ;
    USE SIGNAL ;
    PORT
      LAYER M5 ;
        RECT  16.224 34.368 16.248 34.56 ;
    END
  END mul_weight[69]
  PIN mul_weight[6]
    DIRECTION OUTPUT ;
    USE SIGNAL ;
    PORT
      LAYER M3 ;
        RECT  12.456 34.416 12.474 34.56 ;
    END
  END mul_weight[6]
  PIN mul_weight[70]
    DIRECTION OUTPUT ;
    USE SIGNAL ;
    PORT
      LAYER M3 ;
        RECT  17.064 34.416 17.082 34.56 ;
    END
  END mul_weight[70]
  PIN mul_weight[71]
    DIRECTION OUTPUT ;
    USE SIGNAL ;
    PORT
      LAYER M5 ;
        RECT  16.368 34.368 16.392 34.56 ;
    END
  END mul_weight[71]
  PIN mul_weight[72]
    DIRECTION OUTPUT ;
    USE SIGNAL ;
    PORT
      LAYER M3 ;
        RECT  17.208 34.416 17.226 34.56 ;
    END
  END mul_weight[72]
  PIN mul_weight[73]
    DIRECTION OUTPUT ;
    USE SIGNAL ;
    PORT
      LAYER M5 ;
        RECT  16.512 34.368 16.536 34.56 ;
    END
  END mul_weight[73]
  PIN mul_weight[74]
    DIRECTION OUTPUT ;
    USE SIGNAL ;
    PORT
      LAYER M3 ;
        RECT  17.352 34.416 17.37 34.56 ;
    END
  END mul_weight[74]
  PIN mul_weight[75]
    DIRECTION OUTPUT ;
    USE SIGNAL ;
    PORT
      LAYER M5 ;
        RECT  16.656 34.368 16.68 34.56 ;
    END
  END mul_weight[75]
  PIN mul_weight[76]
    DIRECTION OUTPUT ;
    USE SIGNAL ;
    PORT
      LAYER M3 ;
        RECT  17.496 34.416 17.514 34.56 ;
    END
  END mul_weight[76]
  PIN mul_weight[77]
    DIRECTION OUTPUT ;
    USE SIGNAL ;
    PORT
      LAYER M5 ;
        RECT  16.8 34.368 16.824 34.56 ;
    END
  END mul_weight[77]
  PIN mul_weight[78]
    DIRECTION OUTPUT ;
    USE SIGNAL ;
    PORT
      LAYER M3 ;
        RECT  17.64 34.416 17.658 34.56 ;
    END
  END mul_weight[78]
  PIN mul_weight[79]
    DIRECTION OUTPUT ;
    USE SIGNAL ;
    PORT
      LAYER M5 ;
        RECT  16.944 34.368 16.968 34.56 ;
    END
  END mul_weight[79]
  PIN mul_weight[7]
    DIRECTION OUTPUT ;
    USE SIGNAL ;
    PORT
      LAYER M5 ;
        RECT  11.76 34.368 11.784 34.56 ;
    END
  END mul_weight[7]
  PIN mul_weight[80]
    DIRECTION OUTPUT ;
    USE SIGNAL ;
    PORT
      LAYER M3 ;
        RECT  17.784 34.416 17.802 34.56 ;
    END
  END mul_weight[80]
  PIN mul_weight[81]
    DIRECTION OUTPUT ;
    USE SIGNAL ;
    PORT
      LAYER M5 ;
        RECT  17.088 34.368 17.112 34.56 ;
    END
  END mul_weight[81]
  PIN mul_weight[82]
    DIRECTION OUTPUT ;
    USE SIGNAL ;
    PORT
      LAYER M3 ;
        RECT  17.928 34.416 17.946 34.56 ;
    END
  END mul_weight[82]
  PIN mul_weight[83]
    DIRECTION OUTPUT ;
    USE SIGNAL ;
    PORT
      LAYER M5 ;
        RECT  17.232 34.368 17.256 34.56 ;
    END
  END mul_weight[83]
  PIN mul_weight[84]
    DIRECTION OUTPUT ;
    USE SIGNAL ;
    PORT
      LAYER M3 ;
        RECT  18.072 34.416 18.09 34.56 ;
    END
  END mul_weight[84]
  PIN mul_weight[85]
    DIRECTION OUTPUT ;
    USE SIGNAL ;
    PORT
      LAYER M5 ;
        RECT  17.376 34.368 17.4 34.56 ;
    END
  END mul_weight[85]
  PIN mul_weight[86]
    DIRECTION OUTPUT ;
    USE SIGNAL ;
    PORT
      LAYER M3 ;
        RECT  18.216 34.416 18.234 34.56 ;
    END
  END mul_weight[86]
  PIN mul_weight[87]
    DIRECTION OUTPUT ;
    USE SIGNAL ;
    PORT
      LAYER M5 ;
        RECT  17.52 34.368 17.544 34.56 ;
    END
  END mul_weight[87]
  PIN mul_weight[88]
    DIRECTION OUTPUT ;
    USE SIGNAL ;
    PORT
      LAYER M3 ;
        RECT  18.36 34.416 18.378 34.56 ;
    END
  END mul_weight[88]
  PIN mul_weight[89]
    DIRECTION OUTPUT ;
    USE SIGNAL ;
    PORT
      LAYER M5 ;
        RECT  17.664 34.368 17.688 34.56 ;
    END
  END mul_weight[89]
  PIN mul_weight[8]
    DIRECTION OUTPUT ;
    USE SIGNAL ;
    PORT
      LAYER M3 ;
        RECT  12.6 34.416 12.618 34.56 ;
    END
  END mul_weight[8]
  PIN mul_weight[90]
    DIRECTION OUTPUT ;
    USE SIGNAL ;
    PORT
      LAYER M3 ;
        RECT  18.504 34.416 18.522 34.56 ;
    END
  END mul_weight[90]
  PIN mul_weight[91]
    DIRECTION OUTPUT ;
    USE SIGNAL ;
    PORT
      LAYER M5 ;
        RECT  17.808 34.368 17.832 34.56 ;
    END
  END mul_weight[91]
  PIN mul_weight[92]
    DIRECTION OUTPUT ;
    USE SIGNAL ;
    PORT
      LAYER M3 ;
        RECT  18.648 34.416 18.666 34.56 ;
    END
  END mul_weight[92]
  PIN mul_weight[93]
    DIRECTION OUTPUT ;
    USE SIGNAL ;
    PORT
      LAYER M5 ;
        RECT  17.952 34.368 17.976 34.56 ;
    END
  END mul_weight[93]
  PIN mul_weight[94]
    DIRECTION OUTPUT ;
    USE SIGNAL ;
    PORT
      LAYER M3 ;
        RECT  18.792 34.416 18.81 34.56 ;
    END
  END mul_weight[94]
  PIN mul_weight[95]
    DIRECTION OUTPUT ;
    USE SIGNAL ;
    PORT
      LAYER M5 ;
        RECT  18.096 34.368 18.12 34.56 ;
    END
  END mul_weight[95]
  PIN mul_weight[96]
    DIRECTION OUTPUT ;
    USE SIGNAL ;
    PORT
      LAYER M3 ;
        RECT  18.936 34.416 18.954 34.56 ;
    END
  END mul_weight[96]
  PIN mul_weight[97]
    DIRECTION OUTPUT ;
    USE SIGNAL ;
    PORT
      LAYER M5 ;
        RECT  18.24 34.368 18.264 34.56 ;
    END
  END mul_weight[97]
  PIN mul_weight[98]
    DIRECTION OUTPUT ;
    USE SIGNAL ;
    PORT
      LAYER M3 ;
        RECT  19.08 34.416 19.098 34.56 ;
    END
  END mul_weight[98]
  PIN mul_weight[99]
    DIRECTION OUTPUT ;
    USE SIGNAL ;
    PORT
      LAYER M5 ;
        RECT  18.384 34.368 18.408 34.56 ;
    END
  END mul_weight[99]
  PIN mul_weight[9]
    DIRECTION OUTPUT ;
    USE SIGNAL ;
    PORT
      LAYER M5 ;
        RECT  11.904 34.368 11.928 34.56 ;
    END
  END mul_weight[9]
  PIN out_bits[0]
    DIRECTION OUTPUT ;
    USE SIGNAL ;
    PORT
      LAYER M4 ;
        RECT  73.248 12.816 73.44 12.84 ;
    END
  END out_bits[0]
  PIN out_bits[10]
    DIRECTION OUTPUT ;
    USE SIGNAL ;
    PORT
      LAYER M4 ;
        RECT  73.248 15.696 73.44 15.72 ;
    END
  END out_bits[10]
  PIN out_bits[11]
    DIRECTION OUTPUT ;
    USE SIGNAL ;
    PORT
      LAYER M4 ;
        RECT  73.248 15.984 73.44 16.008 ;
    END
  END out_bits[11]
  PIN out_bits[12]
    DIRECTION OUTPUT ;
    USE SIGNAL ;
    PORT
      LAYER M4 ;
        RECT  73.248 16.272 73.44 16.296 ;
    END
  END out_bits[12]
  PIN out_bits[13]
    DIRECTION OUTPUT ;
    USE SIGNAL ;
    PORT
      LAYER M4 ;
        RECT  73.248 16.56 73.44 16.584 ;
    END
  END out_bits[13]
  PIN out_bits[14]
    DIRECTION OUTPUT ;
    USE SIGNAL ;
    PORT
      LAYER M4 ;
        RECT  73.248 16.848 73.44 16.872 ;
    END
  END out_bits[14]
  PIN out_bits[15]
    DIRECTION OUTPUT ;
    USE SIGNAL ;
    PORT
      LAYER M4 ;
        RECT  73.248 17.136 73.44 17.16 ;
    END
  END out_bits[15]
  PIN out_bits[16]
    DIRECTION OUTPUT ;
    USE SIGNAL ;
    PORT
      LAYER M4 ;
        RECT  73.248 17.424 73.44 17.448 ;
    END
  END out_bits[16]
  PIN out_bits[17]
    DIRECTION OUTPUT ;
    USE SIGNAL ;
    PORT
      LAYER M4 ;
        RECT  73.248 17.712 73.44 17.736 ;
    END
  END out_bits[17]
  PIN out_bits[18]
    DIRECTION OUTPUT ;
    USE SIGNAL ;
    PORT
      LAYER M4 ;
        RECT  73.248 18 73.44 18.024 ;
    END
  END out_bits[18]
  PIN out_bits[19]
    DIRECTION OUTPUT ;
    USE SIGNAL ;
    PORT
      LAYER M4 ;
        RECT  73.248 18.288 73.44 18.312 ;
    END
  END out_bits[19]
  PIN out_bits[1]
    DIRECTION OUTPUT ;
    USE SIGNAL ;
    PORT
      LAYER M4 ;
        RECT  73.248 13.104 73.44 13.128 ;
    END
  END out_bits[1]
  PIN out_bits[20]
    DIRECTION OUTPUT ;
    USE SIGNAL ;
    PORT
      LAYER M4 ;
        RECT  73.248 18.576 73.44 18.6 ;
    END
  END out_bits[20]
  PIN out_bits[21]
    DIRECTION OUTPUT ;
    USE SIGNAL ;
    PORT
      LAYER M4 ;
        RECT  73.248 18.864 73.44 18.888 ;
    END
  END out_bits[21]
  PIN out_bits[22]
    DIRECTION OUTPUT ;
    USE SIGNAL ;
    PORT
      LAYER M4 ;
        RECT  73.248 19.152 73.44 19.176 ;
    END
  END out_bits[22]
  PIN out_bits[23]
    DIRECTION OUTPUT ;
    USE SIGNAL ;
    PORT
      LAYER M4 ;
        RECT  73.248 19.44 73.44 19.464 ;
    END
  END out_bits[23]
  PIN out_bits[24]
    DIRECTION OUTPUT ;
    USE SIGNAL ;
    PORT
      LAYER M4 ;
        RECT  73.248 19.728 73.44 19.752 ;
    END
  END out_bits[24]
  PIN out_bits[25]
    DIRECTION OUTPUT ;
    USE SIGNAL ;
    PORT
      LAYER M4 ;
        RECT  73.248 20.016 73.44 20.04 ;
    END
  END out_bits[25]
  PIN out_bits[26]
    DIRECTION OUTPUT ;
    USE SIGNAL ;
    PORT
      LAYER M4 ;
        RECT  73.248 20.304 73.44 20.328 ;
    END
  END out_bits[26]
  PIN out_bits[27]
    DIRECTION OUTPUT ;
    USE SIGNAL ;
    PORT
      LAYER M4 ;
        RECT  73.248 20.592 73.44 20.616 ;
    END
  END out_bits[27]
  PIN out_bits[28]
    DIRECTION OUTPUT ;
    USE SIGNAL ;
    PORT
      LAYER M4 ;
        RECT  73.248 20.88 73.44 20.904 ;
    END
  END out_bits[28]
  PIN out_bits[29]
    DIRECTION OUTPUT ;
    USE SIGNAL ;
    PORT
      LAYER M4 ;
        RECT  73.248 21.168 73.44 21.192 ;
    END
  END out_bits[29]
  PIN out_bits[2]
    DIRECTION OUTPUT ;
    USE SIGNAL ;
    PORT
      LAYER M4 ;
        RECT  73.248 13.392 73.44 13.416 ;
    END
  END out_bits[2]
  PIN out_bits[30]
    DIRECTION OUTPUT ;
    USE SIGNAL ;
    PORT
      LAYER M4 ;
        RECT  73.248 21.456 73.44 21.48 ;
    END
  END out_bits[30]
  PIN out_bits[31]
    DIRECTION OUTPUT ;
    USE SIGNAL ;
    PORT
      LAYER M4 ;
        RECT  73.248 21.744 73.44 21.768 ;
    END
  END out_bits[31]
  PIN out_bits[3]
    DIRECTION OUTPUT ;
    USE SIGNAL ;
    PORT
      LAYER M4 ;
        RECT  73.248 13.68 73.44 13.704 ;
    END
  END out_bits[3]
  PIN out_bits[4]
    DIRECTION OUTPUT ;
    USE SIGNAL ;
    PORT
      LAYER M4 ;
        RECT  73.248 13.968 73.44 13.992 ;
    END
  END out_bits[4]
  PIN out_bits[5]
    DIRECTION OUTPUT ;
    USE SIGNAL ;
    PORT
      LAYER M4 ;
        RECT  73.248 14.256 73.44 14.28 ;
    END
  END out_bits[5]
  PIN out_bits[6]
    DIRECTION OUTPUT ;
    USE SIGNAL ;
    PORT
      LAYER M4 ;
        RECT  73.248 14.544 73.44 14.568 ;
    END
  END out_bits[6]
  PIN out_bits[7]
    DIRECTION OUTPUT ;
    USE SIGNAL ;
    PORT
      LAYER M4 ;
        RECT  73.248 14.832 73.44 14.856 ;
    END
  END out_bits[7]
  PIN out_bits[8]
    DIRECTION OUTPUT ;
    USE SIGNAL ;
    PORT
      LAYER M4 ;
        RECT  73.248 15.12 73.44 15.144 ;
    END
  END out_bits[8]
  PIN out_bits[9]
    DIRECTION OUTPUT ;
    USE SIGNAL ;
    PORT
      LAYER M4 ;
        RECT  73.248 15.408 73.44 15.432 ;
    END
  END out_bits[9]
  PIN out_valid
    DIRECTION OUTPUT ;
    USE SIGNAL ;
    PORT
      LAYER M3 ;
        RECT  9.288 34.416 9.306 34.56 ;
    END
    PORT
      LAYER M3 ;
        RECT  9.288 32.071 9.306 34.428 ;
    END
  END out_valid
  PIN pf[0]
    DIRECTION INPUT ;
    USE SIGNAL ;
    PORT
      LAYER M3 ;
        RECT  48.168 0 48.186 0.144 ;
    END
  END pf[0]
  PIN pf[10]
    DIRECTION INPUT ;
    USE SIGNAL ;
    PORT
      LAYER M3 ;
        RECT  48.888 0 48.906 0.144 ;
    END
  END pf[10]
  PIN pf[11]
    DIRECTION INPUT ;
    USE SIGNAL ;
    PORT
      LAYER M5 ;
        RECT  48.912 0 48.936 0.192 ;
    END
  END pf[11]
  PIN pf[12]
    DIRECTION INPUT ;
    USE SIGNAL ;
    PORT
      LAYER M3 ;
        RECT  49.032 0 49.05 0.144 ;
    END
  END pf[12]
  PIN pf[13]
    DIRECTION INPUT ;
    USE SIGNAL ;
    PORT
      LAYER M5 ;
        RECT  49.056 0 49.08 0.192 ;
    END
  END pf[13]
  PIN pf[14]
    DIRECTION INPUT ;
    USE SIGNAL ;
    PORT
      LAYER M3 ;
        RECT  49.176 0 49.194 0.144 ;
    END
  END pf[14]
  PIN pf[15]
    DIRECTION INPUT ;
    USE SIGNAL ;
    PORT
      LAYER M5 ;
        RECT  49.2 0 49.224 0.192 ;
    END
  END pf[15]
  PIN pf[1]
    DIRECTION INPUT ;
    USE SIGNAL ;
    PORT
      LAYER M5 ;
        RECT  48.192 0 48.216 0.192 ;
    END
  END pf[1]
  PIN pf[2]
    DIRECTION INPUT ;
    USE SIGNAL ;
    PORT
      LAYER M3 ;
        RECT  48.312 0 48.33 0.144 ;
    END
  END pf[2]
  PIN pf[3]
    DIRECTION INPUT ;
    USE SIGNAL ;
    PORT
      LAYER M5 ;
        RECT  48.336 0 48.36 0.192 ;
    END
  END pf[3]
  PIN pf[4]
    DIRECTION INPUT ;
    USE SIGNAL ;
    PORT
      LAYER M3 ;
        RECT  48.456 0 48.474 0.144 ;
    END
  END pf[4]
  PIN pf[5]
    DIRECTION INPUT ;
    USE SIGNAL ;
    PORT
      LAYER M5 ;
        RECT  48.48 0 48.504 0.192 ;
    END
  END pf[5]
  PIN pf[6]
    DIRECTION INPUT ;
    USE SIGNAL ;
    PORT
      LAYER M3 ;
        RECT  48.6 0 48.618 0.144 ;
    END
  END pf[6]
  PIN pf[7]
    DIRECTION INPUT ;
    USE SIGNAL ;
    PORT
      LAYER M5 ;
        RECT  48.624 0 48.648 0.192 ;
    END
  END pf[7]
  PIN pf[8]
    DIRECTION INPUT ;
    USE SIGNAL ;
    PORT
      LAYER M3 ;
        RECT  48.744 0 48.762 0.144 ;
    END
  END pf[8]
  PIN pf[9]
    DIRECTION INPUT ;
    USE SIGNAL ;
    PORT
      LAYER M5 ;
        RECT  48.768 0 48.792 0.192 ;
    END
  END pf[9]
  PIN pv_last
    DIRECTION OUTPUT ;
    USE SIGNAL ;
    PORT
      LAYER M3 ;
        RECT  51.192 34.416 51.21 34.56 ;
    END
  END pv_last
  PIN rst_n
    DIRECTION INPUT ;
    USE SIGNAL ;
    PORT
      LAYER M4 ;
        RECT  0 15.024 0.192 15.048 ;
    END
  END rst_n
  PIN start
    DIRECTION INPUT ;
    USE SIGNAL ;
    PORT
      LAYER M4 ;
        RECT  0 15.168 0.192 15.192 ;
    END
  END start
  PIN weight_bf16[0]
    DIRECTION INPUT ;
    USE SIGNAL ;
    PORT
      LAYER M3 ;
        RECT  11.304 0 11.322 0.144 ;
    END
  END weight_bf16[0]
  PIN weight_bf16[100]
    DIRECTION INPUT ;
    USE SIGNAL ;
    PORT
      LAYER M3 ;
        RECT  18.504 0 18.522 0.144 ;
    END
  END weight_bf16[100]
  PIN weight_bf16[101]
    DIRECTION INPUT ;
    USE SIGNAL ;
    PORT
      LAYER M5 ;
        RECT  18.528 0 18.552 0.192 ;
    END
  END weight_bf16[101]
  PIN weight_bf16[102]
    DIRECTION INPUT ;
    USE SIGNAL ;
    PORT
      LAYER M3 ;
        RECT  18.648 0 18.666 0.144 ;
    END
  END weight_bf16[102]
  PIN weight_bf16[103]
    DIRECTION INPUT ;
    USE SIGNAL ;
    PORT
      LAYER M5 ;
        RECT  18.672 0 18.696 0.192 ;
    END
  END weight_bf16[103]
  PIN weight_bf16[104]
    DIRECTION INPUT ;
    USE SIGNAL ;
    PORT
      LAYER M3 ;
        RECT  18.792 0 18.81 0.144 ;
    END
  END weight_bf16[104]
  PIN weight_bf16[105]
    DIRECTION INPUT ;
    USE SIGNAL ;
    PORT
      LAYER M5 ;
        RECT  18.816 0 18.84 0.192 ;
    END
  END weight_bf16[105]
  PIN weight_bf16[106]
    DIRECTION INPUT ;
    USE SIGNAL ;
    PORT
      LAYER M3 ;
        RECT  18.936 0 18.954 0.144 ;
    END
  END weight_bf16[106]
  PIN weight_bf16[107]
    DIRECTION INPUT ;
    USE SIGNAL ;
    PORT
      LAYER M5 ;
        RECT  18.96 0 18.984 0.192 ;
    END
  END weight_bf16[107]
  PIN weight_bf16[108]
    DIRECTION INPUT ;
    USE SIGNAL ;
    PORT
      LAYER M3 ;
        RECT  19.08 0 19.098 0.144 ;
    END
  END weight_bf16[108]
  PIN weight_bf16[109]
    DIRECTION INPUT ;
    USE SIGNAL ;
    PORT
      LAYER M5 ;
        RECT  19.104 0 19.128 0.192 ;
    END
  END weight_bf16[109]
  PIN weight_bf16[10]
    DIRECTION INPUT ;
    USE SIGNAL ;
    PORT
      LAYER M3 ;
        RECT  12.024 0 12.042 0.144 ;
    END
  END weight_bf16[10]
  PIN weight_bf16[110]
    DIRECTION INPUT ;
    USE SIGNAL ;
    PORT
      LAYER M3 ;
        RECT  19.224 0 19.242 0.144 ;
    END
  END weight_bf16[110]
  PIN weight_bf16[111]
    DIRECTION INPUT ;
    USE SIGNAL ;
    PORT
      LAYER M5 ;
        RECT  19.248 0 19.272 0.192 ;
    END
  END weight_bf16[111]
  PIN weight_bf16[112]
    DIRECTION INPUT ;
    USE SIGNAL ;
    PORT
      LAYER M3 ;
        RECT  19.368 0 19.386 0.144 ;
    END
  END weight_bf16[112]
  PIN weight_bf16[113]
    DIRECTION INPUT ;
    USE SIGNAL ;
    PORT
      LAYER M5 ;
        RECT  19.392 0 19.416 0.192 ;
    END
  END weight_bf16[113]
  PIN weight_bf16[114]
    DIRECTION INPUT ;
    USE SIGNAL ;
    PORT
      LAYER M3 ;
        RECT  19.512 0 19.53 0.144 ;
    END
  END weight_bf16[114]
  PIN weight_bf16[115]
    DIRECTION INPUT ;
    USE SIGNAL ;
    PORT
      LAYER M5 ;
        RECT  19.536 0 19.56 0.192 ;
    END
  END weight_bf16[115]
  PIN weight_bf16[116]
    DIRECTION INPUT ;
    USE SIGNAL ;
    PORT
      LAYER M3 ;
        RECT  19.656 0 19.674 0.144 ;
    END
  END weight_bf16[116]
  PIN weight_bf16[117]
    DIRECTION INPUT ;
    USE SIGNAL ;
    PORT
      LAYER M5 ;
        RECT  19.68 0 19.704 0.192 ;
    END
  END weight_bf16[117]
  PIN weight_bf16[118]
    DIRECTION INPUT ;
    USE SIGNAL ;
    PORT
      LAYER M3 ;
        RECT  19.8 0 19.818 0.144 ;
    END
  END weight_bf16[118]
  PIN weight_bf16[119]
    DIRECTION INPUT ;
    USE SIGNAL ;
    PORT
      LAYER M5 ;
        RECT  19.824 0 19.848 0.192 ;
    END
  END weight_bf16[119]
  PIN weight_bf16[11]
    DIRECTION INPUT ;
    USE SIGNAL ;
    PORT
      LAYER M5 ;
        RECT  12.048 0 12.072 0.192 ;
    END
  END weight_bf16[11]
  PIN weight_bf16[120]
    DIRECTION INPUT ;
    USE SIGNAL ;
    PORT
      LAYER M3 ;
        RECT  19.944 0 19.962 0.144 ;
    END
  END weight_bf16[120]
  PIN weight_bf16[121]
    DIRECTION INPUT ;
    USE SIGNAL ;
    PORT
      LAYER M5 ;
        RECT  19.968 0 19.992 0.192 ;
    END
  END weight_bf16[121]
  PIN weight_bf16[122]
    DIRECTION INPUT ;
    USE SIGNAL ;
    PORT
      LAYER M3 ;
        RECT  20.088 0 20.106 0.144 ;
    END
  END weight_bf16[122]
  PIN weight_bf16[123]
    DIRECTION INPUT ;
    USE SIGNAL ;
    PORT
      LAYER M5 ;
        RECT  20.112 0 20.136 0.192 ;
    END
  END weight_bf16[123]
  PIN weight_bf16[124]
    DIRECTION INPUT ;
    USE SIGNAL ;
    PORT
      LAYER M3 ;
        RECT  20.232 0 20.25 0.144 ;
    END
  END weight_bf16[124]
  PIN weight_bf16[125]
    DIRECTION INPUT ;
    USE SIGNAL ;
    PORT
      LAYER M5 ;
        RECT  20.256 0 20.28 0.192 ;
    END
  END weight_bf16[125]
  PIN weight_bf16[126]
    DIRECTION INPUT ;
    USE SIGNAL ;
    PORT
      LAYER M3 ;
        RECT  20.376 0 20.394 0.144 ;
    END
  END weight_bf16[126]
  PIN weight_bf16[127]
    DIRECTION INPUT ;
    USE SIGNAL ;
    PORT
      LAYER M5 ;
        RECT  20.4 0 20.424 0.192 ;
    END
  END weight_bf16[127]
  PIN weight_bf16[128]
    DIRECTION INPUT ;
    USE SIGNAL ;
    PORT
      LAYER M3 ;
        RECT  20.52 0 20.538 0.144 ;
    END
  END weight_bf16[128]
  PIN weight_bf16[129]
    DIRECTION INPUT ;
    USE SIGNAL ;
    PORT
      LAYER M5 ;
        RECT  20.544 0 20.568 0.192 ;
    END
  END weight_bf16[129]
  PIN weight_bf16[12]
    DIRECTION INPUT ;
    USE SIGNAL ;
    PORT
      LAYER M3 ;
        RECT  12.168 0 12.186 0.144 ;
    END
  END weight_bf16[12]
  PIN weight_bf16[130]
    DIRECTION INPUT ;
    USE SIGNAL ;
    PORT
      LAYER M3 ;
        RECT  20.664 0 20.682 0.144 ;
    END
  END weight_bf16[130]
  PIN weight_bf16[131]
    DIRECTION INPUT ;
    USE SIGNAL ;
    PORT
      LAYER M5 ;
        RECT  20.688 0 20.712 0.192 ;
    END
  END weight_bf16[131]
  PIN weight_bf16[132]
    DIRECTION INPUT ;
    USE SIGNAL ;
    PORT
      LAYER M3 ;
        RECT  20.808 0 20.826 0.144 ;
    END
  END weight_bf16[132]
  PIN weight_bf16[133]
    DIRECTION INPUT ;
    USE SIGNAL ;
    PORT
      LAYER M5 ;
        RECT  20.832 0 20.856 0.192 ;
    END
  END weight_bf16[133]
  PIN weight_bf16[134]
    DIRECTION INPUT ;
    USE SIGNAL ;
    PORT
      LAYER M3 ;
        RECT  20.952 0 20.97 0.144 ;
    END
  END weight_bf16[134]
  PIN weight_bf16[135]
    DIRECTION INPUT ;
    USE SIGNAL ;
    PORT
      LAYER M5 ;
        RECT  20.976 0 21 0.192 ;
    END
  END weight_bf16[135]
  PIN weight_bf16[136]
    DIRECTION INPUT ;
    USE SIGNAL ;
    PORT
      LAYER M3 ;
        RECT  21.096 0 21.114 0.144 ;
    END
  END weight_bf16[136]
  PIN weight_bf16[137]
    DIRECTION INPUT ;
    USE SIGNAL ;
    PORT
      LAYER M5 ;
        RECT  21.12 0 21.144 0.192 ;
    END
  END weight_bf16[137]
  PIN weight_bf16[138]
    DIRECTION INPUT ;
    USE SIGNAL ;
    PORT
      LAYER M3 ;
        RECT  21.24 0 21.258 0.144 ;
    END
  END weight_bf16[138]
  PIN weight_bf16[139]
    DIRECTION INPUT ;
    USE SIGNAL ;
    PORT
      LAYER M5 ;
        RECT  21.264 0 21.288 0.192 ;
    END
  END weight_bf16[139]
  PIN weight_bf16[13]
    DIRECTION INPUT ;
    USE SIGNAL ;
    PORT
      LAYER M5 ;
        RECT  12.192 0 12.216 0.192 ;
    END
  END weight_bf16[13]
  PIN weight_bf16[140]
    DIRECTION INPUT ;
    USE SIGNAL ;
    PORT
      LAYER M3 ;
        RECT  21.384 0 21.402 0.144 ;
    END
  END weight_bf16[140]
  PIN weight_bf16[141]
    DIRECTION INPUT ;
    USE SIGNAL ;
    PORT
      LAYER M5 ;
        RECT  21.408 0 21.432 0.192 ;
    END
  END weight_bf16[141]
  PIN weight_bf16[142]
    DIRECTION INPUT ;
    USE SIGNAL ;
    PORT
      LAYER M3 ;
        RECT  21.528 0 21.546 0.144 ;
    END
  END weight_bf16[142]
  PIN weight_bf16[143]
    DIRECTION INPUT ;
    USE SIGNAL ;
    PORT
      LAYER M5 ;
        RECT  21.552 0 21.576 0.192 ;
    END
  END weight_bf16[143]
  PIN weight_bf16[144]
    DIRECTION INPUT ;
    USE SIGNAL ;
    PORT
      LAYER M3 ;
        RECT  21.672 0 21.69 0.144 ;
    END
  END weight_bf16[144]
  PIN weight_bf16[145]
    DIRECTION INPUT ;
    USE SIGNAL ;
    PORT
      LAYER M5 ;
        RECT  21.696 0 21.72 0.192 ;
    END
  END weight_bf16[145]
  PIN weight_bf16[146]
    DIRECTION INPUT ;
    USE SIGNAL ;
    PORT
      LAYER M3 ;
        RECT  21.816 0 21.834 0.144 ;
    END
  END weight_bf16[146]
  PIN weight_bf16[147]
    DIRECTION INPUT ;
    USE SIGNAL ;
    PORT
      LAYER M5 ;
        RECT  21.84 0 21.864 0.192 ;
    END
  END weight_bf16[147]
  PIN weight_bf16[148]
    DIRECTION INPUT ;
    USE SIGNAL ;
    PORT
      LAYER M3 ;
        RECT  21.96 0 21.978 0.144 ;
    END
  END weight_bf16[148]
  PIN weight_bf16[149]
    DIRECTION INPUT ;
    USE SIGNAL ;
    PORT
      LAYER M5 ;
        RECT  21.984 0 22.008 0.192 ;
    END
  END weight_bf16[149]
  PIN weight_bf16[14]
    DIRECTION INPUT ;
    USE SIGNAL ;
    PORT
      LAYER M3 ;
        RECT  12.312 0 12.33 0.144 ;
    END
  END weight_bf16[14]
  PIN weight_bf16[150]
    DIRECTION INPUT ;
    USE SIGNAL ;
    PORT
      LAYER M3 ;
        RECT  22.104 0 22.122 0.144 ;
    END
  END weight_bf16[150]
  PIN weight_bf16[151]
    DIRECTION INPUT ;
    USE SIGNAL ;
    PORT
      LAYER M5 ;
        RECT  22.128 0 22.152 0.192 ;
    END
  END weight_bf16[151]
  PIN weight_bf16[152]
    DIRECTION INPUT ;
    USE SIGNAL ;
    PORT
      LAYER M3 ;
        RECT  22.248 0 22.266 0.144 ;
    END
  END weight_bf16[152]
  PIN weight_bf16[153]
    DIRECTION INPUT ;
    USE SIGNAL ;
    PORT
      LAYER M5 ;
        RECT  22.272 0 22.296 0.192 ;
    END
  END weight_bf16[153]
  PIN weight_bf16[154]
    DIRECTION INPUT ;
    USE SIGNAL ;
    PORT
      LAYER M3 ;
        RECT  22.392 0 22.41 0.144 ;
    END
  END weight_bf16[154]
  PIN weight_bf16[155]
    DIRECTION INPUT ;
    USE SIGNAL ;
    PORT
      LAYER M5 ;
        RECT  22.416 0 22.44 0.192 ;
    END
  END weight_bf16[155]
  PIN weight_bf16[156]
    DIRECTION INPUT ;
    USE SIGNAL ;
    PORT
      LAYER M3 ;
        RECT  22.536 0 22.554 0.144 ;
    END
  END weight_bf16[156]
  PIN weight_bf16[157]
    DIRECTION INPUT ;
    USE SIGNAL ;
    PORT
      LAYER M5 ;
        RECT  22.56 0 22.584 0.192 ;
    END
  END weight_bf16[157]
  PIN weight_bf16[158]
    DIRECTION INPUT ;
    USE SIGNAL ;
    PORT
      LAYER M3 ;
        RECT  22.68 0 22.698 0.144 ;
    END
  END weight_bf16[158]
  PIN weight_bf16[159]
    DIRECTION INPUT ;
    USE SIGNAL ;
    PORT
      LAYER M5 ;
        RECT  22.704 0 22.728 0.192 ;
    END
  END weight_bf16[159]
  PIN weight_bf16[15]
    DIRECTION INPUT ;
    USE SIGNAL ;
    PORT
      LAYER M5 ;
        RECT  12.336 0 12.36 0.192 ;
    END
  END weight_bf16[15]
  PIN weight_bf16[160]
    DIRECTION INPUT ;
    USE SIGNAL ;
    PORT
      LAYER M3 ;
        RECT  22.824 0 22.842 0.144 ;
    END
  END weight_bf16[160]
  PIN weight_bf16[161]
    DIRECTION INPUT ;
    USE SIGNAL ;
    PORT
      LAYER M5 ;
        RECT  22.848 0 22.872 0.192 ;
    END
  END weight_bf16[161]
  PIN weight_bf16[162]
    DIRECTION INPUT ;
    USE SIGNAL ;
    PORT
      LAYER M3 ;
        RECT  22.968 0 22.986 0.144 ;
    END
  END weight_bf16[162]
  PIN weight_bf16[163]
    DIRECTION INPUT ;
    USE SIGNAL ;
    PORT
      LAYER M5 ;
        RECT  22.992 0 23.016 0.192 ;
    END
  END weight_bf16[163]
  PIN weight_bf16[164]
    DIRECTION INPUT ;
    USE SIGNAL ;
    PORT
      LAYER M3 ;
        RECT  23.112 0 23.13 0.144 ;
    END
  END weight_bf16[164]
  PIN weight_bf16[165]
    DIRECTION INPUT ;
    USE SIGNAL ;
    PORT
      LAYER M5 ;
        RECT  23.136 0 23.16 0.192 ;
    END
  END weight_bf16[165]
  PIN weight_bf16[166]
    DIRECTION INPUT ;
    USE SIGNAL ;
    PORT
      LAYER M3 ;
        RECT  23.256 0 23.274 0.144 ;
    END
  END weight_bf16[166]
  PIN weight_bf16[167]
    DIRECTION INPUT ;
    USE SIGNAL ;
    PORT
      LAYER M5 ;
        RECT  23.28 0 23.304 0.192 ;
    END
  END weight_bf16[167]
  PIN weight_bf16[168]
    DIRECTION INPUT ;
    USE SIGNAL ;
    PORT
      LAYER M3 ;
        RECT  23.4 0 23.418 0.144 ;
    END
  END weight_bf16[168]
  PIN weight_bf16[169]
    DIRECTION INPUT ;
    USE SIGNAL ;
    PORT
      LAYER M5 ;
        RECT  23.424 0 23.448 0.192 ;
    END
  END weight_bf16[169]
  PIN weight_bf16[16]
    DIRECTION INPUT ;
    USE SIGNAL ;
    PORT
      LAYER M3 ;
        RECT  12.456 0 12.474 0.144 ;
    END
  END weight_bf16[16]
  PIN weight_bf16[170]
    DIRECTION INPUT ;
    USE SIGNAL ;
    PORT
      LAYER M3 ;
        RECT  23.544 0 23.562 0.144 ;
    END
  END weight_bf16[170]
  PIN weight_bf16[171]
    DIRECTION INPUT ;
    USE SIGNAL ;
    PORT
      LAYER M5 ;
        RECT  23.568 0 23.592 0.192 ;
    END
  END weight_bf16[171]
  PIN weight_bf16[172]
    DIRECTION INPUT ;
    USE SIGNAL ;
    PORT
      LAYER M3 ;
        RECT  23.688 0 23.706 0.144 ;
    END
  END weight_bf16[172]
  PIN weight_bf16[173]
    DIRECTION INPUT ;
    USE SIGNAL ;
    PORT
      LAYER M5 ;
        RECT  23.712 0 23.736 0.192 ;
    END
  END weight_bf16[173]
  PIN weight_bf16[174]
    DIRECTION INPUT ;
    USE SIGNAL ;
    PORT
      LAYER M3 ;
        RECT  23.832 0 23.85 0.144 ;
    END
  END weight_bf16[174]
  PIN weight_bf16[175]
    DIRECTION INPUT ;
    USE SIGNAL ;
    PORT
      LAYER M5 ;
        RECT  23.856 0 23.88 0.192 ;
    END
  END weight_bf16[175]
  PIN weight_bf16[176]
    DIRECTION INPUT ;
    USE SIGNAL ;
    PORT
      LAYER M3 ;
        RECT  23.976 0 23.994 0.144 ;
    END
  END weight_bf16[176]
  PIN weight_bf16[177]
    DIRECTION INPUT ;
    USE SIGNAL ;
    PORT
      LAYER M5 ;
        RECT  24 0 24.024 0.192 ;
    END
  END weight_bf16[177]
  PIN weight_bf16[178]
    DIRECTION INPUT ;
    USE SIGNAL ;
    PORT
      LAYER M3 ;
        RECT  24.12 0 24.138 0.144 ;
    END
  END weight_bf16[178]
  PIN weight_bf16[179]
    DIRECTION INPUT ;
    USE SIGNAL ;
    PORT
      LAYER M5 ;
        RECT  24.144 0 24.168 0.192 ;
    END
  END weight_bf16[179]
  PIN weight_bf16[17]
    DIRECTION INPUT ;
    USE SIGNAL ;
    PORT
      LAYER M5 ;
        RECT  12.48 0 12.504 0.192 ;
    END
  END weight_bf16[17]
  PIN weight_bf16[180]
    DIRECTION INPUT ;
    USE SIGNAL ;
    PORT
      LAYER M3 ;
        RECT  24.264 0 24.282 0.144 ;
    END
  END weight_bf16[180]
  PIN weight_bf16[181]
    DIRECTION INPUT ;
    USE SIGNAL ;
    PORT
      LAYER M5 ;
        RECT  24.288 0 24.312 0.192 ;
    END
  END weight_bf16[181]
  PIN weight_bf16[182]
    DIRECTION INPUT ;
    USE SIGNAL ;
    PORT
      LAYER M3 ;
        RECT  24.408 0 24.426 0.144 ;
    END
  END weight_bf16[182]
  PIN weight_bf16[183]
    DIRECTION INPUT ;
    USE SIGNAL ;
    PORT
      LAYER M5 ;
        RECT  24.432 0 24.456 0.192 ;
    END
  END weight_bf16[183]
  PIN weight_bf16[184]
    DIRECTION INPUT ;
    USE SIGNAL ;
    PORT
      LAYER M3 ;
        RECT  24.552 0 24.57 0.144 ;
    END
  END weight_bf16[184]
  PIN weight_bf16[185]
    DIRECTION INPUT ;
    USE SIGNAL ;
    PORT
      LAYER M5 ;
        RECT  24.576 0 24.6 0.192 ;
    END
  END weight_bf16[185]
  PIN weight_bf16[186]
    DIRECTION INPUT ;
    USE SIGNAL ;
    PORT
      LAYER M3 ;
        RECT  24.696 0 24.714 0.144 ;
    END
  END weight_bf16[186]
  PIN weight_bf16[187]
    DIRECTION INPUT ;
    USE SIGNAL ;
    PORT
      LAYER M5 ;
        RECT  24.72 0 24.744 0.192 ;
    END
  END weight_bf16[187]
  PIN weight_bf16[188]
    DIRECTION INPUT ;
    USE SIGNAL ;
    PORT
      LAYER M3 ;
        RECT  24.84 0 24.858 0.144 ;
    END
  END weight_bf16[188]
  PIN weight_bf16[189]
    DIRECTION INPUT ;
    USE SIGNAL ;
    PORT
      LAYER M5 ;
        RECT  24.864 0 24.888 0.192 ;
    END
  END weight_bf16[189]
  PIN weight_bf16[18]
    DIRECTION INPUT ;
    USE SIGNAL ;
    PORT
      LAYER M3 ;
        RECT  12.6 0 12.618 0.144 ;
    END
  END weight_bf16[18]
  PIN weight_bf16[190]
    DIRECTION INPUT ;
    USE SIGNAL ;
    PORT
      LAYER M3 ;
        RECT  24.984 0 25.002 0.144 ;
    END
  END weight_bf16[190]
  PIN weight_bf16[191]
    DIRECTION INPUT ;
    USE SIGNAL ;
    PORT
      LAYER M5 ;
        RECT  25.008 0 25.032 0.192 ;
    END
  END weight_bf16[191]
  PIN weight_bf16[192]
    DIRECTION INPUT ;
    USE SIGNAL ;
    PORT
      LAYER M3 ;
        RECT  25.128 0 25.146 0.144 ;
    END
  END weight_bf16[192]
  PIN weight_bf16[193]
    DIRECTION INPUT ;
    USE SIGNAL ;
    PORT
      LAYER M5 ;
        RECT  25.152 0 25.176 0.192 ;
    END
  END weight_bf16[193]
  PIN weight_bf16[194]
    DIRECTION INPUT ;
    USE SIGNAL ;
    PORT
      LAYER M3 ;
        RECT  25.272 0 25.29 0.144 ;
    END
  END weight_bf16[194]
  PIN weight_bf16[195]
    DIRECTION INPUT ;
    USE SIGNAL ;
    PORT
      LAYER M5 ;
        RECT  25.296 0 25.32 0.192 ;
    END
  END weight_bf16[195]
  PIN weight_bf16[196]
    DIRECTION INPUT ;
    USE SIGNAL ;
    PORT
      LAYER M3 ;
        RECT  25.416 0 25.434 0.144 ;
    END
  END weight_bf16[196]
  PIN weight_bf16[197]
    DIRECTION INPUT ;
    USE SIGNAL ;
    PORT
      LAYER M5 ;
        RECT  25.44 0 25.464 0.192 ;
    END
  END weight_bf16[197]
  PIN weight_bf16[198]
    DIRECTION INPUT ;
    USE SIGNAL ;
    PORT
      LAYER M3 ;
        RECT  25.56 0 25.578 0.144 ;
    END
  END weight_bf16[198]
  PIN weight_bf16[199]
    DIRECTION INPUT ;
    USE SIGNAL ;
    PORT
      LAYER M5 ;
        RECT  25.584 0 25.608 0.192 ;
    END
  END weight_bf16[199]
  PIN weight_bf16[19]
    DIRECTION INPUT ;
    USE SIGNAL ;
    PORT
      LAYER M5 ;
        RECT  12.624 0 12.648 0.192 ;
    END
  END weight_bf16[19]
  PIN weight_bf16[1]
    DIRECTION INPUT ;
    USE SIGNAL ;
    PORT
      LAYER M5 ;
        RECT  11.328 0 11.352 0.192 ;
    END
  END weight_bf16[1]
  PIN weight_bf16[200]
    DIRECTION INPUT ;
    USE SIGNAL ;
    PORT
      LAYER M3 ;
        RECT  25.704 0 25.722 0.144 ;
    END
  END weight_bf16[200]
  PIN weight_bf16[201]
    DIRECTION INPUT ;
    USE SIGNAL ;
    PORT
      LAYER M5 ;
        RECT  25.728 0 25.752 0.192 ;
    END
  END weight_bf16[201]
  PIN weight_bf16[202]
    DIRECTION INPUT ;
    USE SIGNAL ;
    PORT
      LAYER M3 ;
        RECT  25.848 0 25.866 0.144 ;
    END
  END weight_bf16[202]
  PIN weight_bf16[203]
    DIRECTION INPUT ;
    USE SIGNAL ;
    PORT
      LAYER M5 ;
        RECT  25.872 0 25.896 0.192 ;
    END
  END weight_bf16[203]
  PIN weight_bf16[204]
    DIRECTION INPUT ;
    USE SIGNAL ;
    PORT
      LAYER M3 ;
        RECT  25.992 0 26.01 0.144 ;
    END
  END weight_bf16[204]
  PIN weight_bf16[205]
    DIRECTION INPUT ;
    USE SIGNAL ;
    PORT
      LAYER M5 ;
        RECT  26.016 0 26.04 0.192 ;
    END
  END weight_bf16[205]
  PIN weight_bf16[206]
    DIRECTION INPUT ;
    USE SIGNAL ;
    PORT
      LAYER M3 ;
        RECT  26.136 0 26.154 0.144 ;
    END
  END weight_bf16[206]
  PIN weight_bf16[207]
    DIRECTION INPUT ;
    USE SIGNAL ;
    PORT
      LAYER M5 ;
        RECT  26.16 0 26.184 0.192 ;
    END
  END weight_bf16[207]
  PIN weight_bf16[208]
    DIRECTION INPUT ;
    USE SIGNAL ;
    PORT
      LAYER M3 ;
        RECT  26.28 0 26.298 0.144 ;
    END
  END weight_bf16[208]
  PIN weight_bf16[209]
    DIRECTION INPUT ;
    USE SIGNAL ;
    PORT
      LAYER M5 ;
        RECT  26.304 0 26.328 0.192 ;
    END
  END weight_bf16[209]
  PIN weight_bf16[20]
    DIRECTION INPUT ;
    USE SIGNAL ;
    PORT
      LAYER M3 ;
        RECT  12.744 0 12.762 0.144 ;
    END
  END weight_bf16[20]
  PIN weight_bf16[210]
    DIRECTION INPUT ;
    USE SIGNAL ;
    PORT
      LAYER M3 ;
        RECT  26.424 0 26.442 0.144 ;
    END
  END weight_bf16[210]
  PIN weight_bf16[211]
    DIRECTION INPUT ;
    USE SIGNAL ;
    PORT
      LAYER M5 ;
        RECT  26.448 0 26.472 0.192 ;
    END
  END weight_bf16[211]
  PIN weight_bf16[212]
    DIRECTION INPUT ;
    USE SIGNAL ;
    PORT
      LAYER M3 ;
        RECT  26.568 0 26.586 0.144 ;
    END
  END weight_bf16[212]
  PIN weight_bf16[213]
    DIRECTION INPUT ;
    USE SIGNAL ;
    PORT
      LAYER M5 ;
        RECT  26.592 0 26.616 0.192 ;
    END
  END weight_bf16[213]
  PIN weight_bf16[214]
    DIRECTION INPUT ;
    USE SIGNAL ;
    PORT
      LAYER M3 ;
        RECT  26.712 0 26.73 0.144 ;
    END
  END weight_bf16[214]
  PIN weight_bf16[215]
    DIRECTION INPUT ;
    USE SIGNAL ;
    PORT
      LAYER M5 ;
        RECT  26.736 0 26.76 0.192 ;
    END
  END weight_bf16[215]
  PIN weight_bf16[216]
    DIRECTION INPUT ;
    USE SIGNAL ;
    PORT
      LAYER M3 ;
        RECT  26.856 0 26.874 0.144 ;
    END
  END weight_bf16[216]
  PIN weight_bf16[217]
    DIRECTION INPUT ;
    USE SIGNAL ;
    PORT
      LAYER M5 ;
        RECT  26.88 0 26.904 0.192 ;
    END
  END weight_bf16[217]
  PIN weight_bf16[218]
    DIRECTION INPUT ;
    USE SIGNAL ;
    PORT
      LAYER M3 ;
        RECT  27 0 27.018 0.144 ;
    END
  END weight_bf16[218]
  PIN weight_bf16[219]
    DIRECTION INPUT ;
    USE SIGNAL ;
    PORT
      LAYER M5 ;
        RECT  27.024 0 27.048 0.192 ;
    END
  END weight_bf16[219]
  PIN weight_bf16[21]
    DIRECTION INPUT ;
    USE SIGNAL ;
    PORT
      LAYER M5 ;
        RECT  12.768 0 12.792 0.192 ;
    END
  END weight_bf16[21]
  PIN weight_bf16[220]
    DIRECTION INPUT ;
    USE SIGNAL ;
    PORT
      LAYER M3 ;
        RECT  27.144 0 27.162 0.144 ;
    END
  END weight_bf16[220]
  PIN weight_bf16[221]
    DIRECTION INPUT ;
    USE SIGNAL ;
    PORT
      LAYER M5 ;
        RECT  27.168 0 27.192 0.192 ;
    END
  END weight_bf16[221]
  PIN weight_bf16[222]
    DIRECTION INPUT ;
    USE SIGNAL ;
    PORT
      LAYER M3 ;
        RECT  27.288 0 27.306 0.144 ;
    END
  END weight_bf16[222]
  PIN weight_bf16[223]
    DIRECTION INPUT ;
    USE SIGNAL ;
    PORT
      LAYER M5 ;
        RECT  27.312 0 27.336 0.192 ;
    END
  END weight_bf16[223]
  PIN weight_bf16[224]
    DIRECTION INPUT ;
    USE SIGNAL ;
    PORT
      LAYER M3 ;
        RECT  27.432 0 27.45 0.144 ;
    END
  END weight_bf16[224]
  PIN weight_bf16[225]
    DIRECTION INPUT ;
    USE SIGNAL ;
    PORT
      LAYER M5 ;
        RECT  27.456 0 27.48 0.192 ;
    END
  END weight_bf16[225]
  PIN weight_bf16[226]
    DIRECTION INPUT ;
    USE SIGNAL ;
    PORT
      LAYER M3 ;
        RECT  27.576 0 27.594 0.144 ;
    END
  END weight_bf16[226]
  PIN weight_bf16[227]
    DIRECTION INPUT ;
    USE SIGNAL ;
    PORT
      LAYER M5 ;
        RECT  27.6 0 27.624 0.192 ;
    END
  END weight_bf16[227]
  PIN weight_bf16[228]
    DIRECTION INPUT ;
    USE SIGNAL ;
    PORT
      LAYER M3 ;
        RECT  27.72 0 27.738 0.144 ;
    END
  END weight_bf16[228]
  PIN weight_bf16[229]
    DIRECTION INPUT ;
    USE SIGNAL ;
    PORT
      LAYER M5 ;
        RECT  27.744 0 27.768 0.192 ;
    END
  END weight_bf16[229]
  PIN weight_bf16[22]
    DIRECTION INPUT ;
    USE SIGNAL ;
    PORT
      LAYER M3 ;
        RECT  12.888 0 12.906 0.144 ;
    END
  END weight_bf16[22]
  PIN weight_bf16[230]
    DIRECTION INPUT ;
    USE SIGNAL ;
    PORT
      LAYER M3 ;
        RECT  27.864 0 27.882 0.144 ;
    END
  END weight_bf16[230]
  PIN weight_bf16[231]
    DIRECTION INPUT ;
    USE SIGNAL ;
    PORT
      LAYER M5 ;
        RECT  27.888 0 27.912 0.192 ;
    END
  END weight_bf16[231]
  PIN weight_bf16[232]
    DIRECTION INPUT ;
    USE SIGNAL ;
    PORT
      LAYER M3 ;
        RECT  28.008 0 28.026 0.144 ;
    END
  END weight_bf16[232]
  PIN weight_bf16[233]
    DIRECTION INPUT ;
    USE SIGNAL ;
    PORT
      LAYER M5 ;
        RECT  28.032 0 28.056 0.192 ;
    END
  END weight_bf16[233]
  PIN weight_bf16[234]
    DIRECTION INPUT ;
    USE SIGNAL ;
    PORT
      LAYER M3 ;
        RECT  28.152 0 28.17 0.144 ;
    END
  END weight_bf16[234]
  PIN weight_bf16[235]
    DIRECTION INPUT ;
    USE SIGNAL ;
    PORT
      LAYER M5 ;
        RECT  28.176 0 28.2 0.192 ;
    END
  END weight_bf16[235]
  PIN weight_bf16[236]
    DIRECTION INPUT ;
    USE SIGNAL ;
    PORT
      LAYER M3 ;
        RECT  28.296 0 28.314 0.144 ;
    END
  END weight_bf16[236]
  PIN weight_bf16[237]
    DIRECTION INPUT ;
    USE SIGNAL ;
    PORT
      LAYER M5 ;
        RECT  28.32 0 28.344 0.192 ;
    END
  END weight_bf16[237]
  PIN weight_bf16[238]
    DIRECTION INPUT ;
    USE SIGNAL ;
    PORT
      LAYER M3 ;
        RECT  28.44 0 28.458 0.144 ;
    END
  END weight_bf16[238]
  PIN weight_bf16[239]
    DIRECTION INPUT ;
    USE SIGNAL ;
    PORT
      LAYER M5 ;
        RECT  28.464 0 28.488 0.192 ;
    END
  END weight_bf16[239]
  PIN weight_bf16[23]
    DIRECTION INPUT ;
    USE SIGNAL ;
    PORT
      LAYER M5 ;
        RECT  12.912 0 12.936 0.192 ;
    END
  END weight_bf16[23]
  PIN weight_bf16[240]
    DIRECTION INPUT ;
    USE SIGNAL ;
    PORT
      LAYER M3 ;
        RECT  28.584 0 28.602 0.144 ;
    END
  END weight_bf16[240]
  PIN weight_bf16[241]
    DIRECTION INPUT ;
    USE SIGNAL ;
    PORT
      LAYER M5 ;
        RECT  28.608 0 28.632 0.192 ;
    END
  END weight_bf16[241]
  PIN weight_bf16[242]
    DIRECTION INPUT ;
    USE SIGNAL ;
    PORT
      LAYER M3 ;
        RECT  28.728 0 28.746 0.144 ;
    END
  END weight_bf16[242]
  PIN weight_bf16[243]
    DIRECTION INPUT ;
    USE SIGNAL ;
    PORT
      LAYER M5 ;
        RECT  28.752 0 28.776 0.192 ;
    END
  END weight_bf16[243]
  PIN weight_bf16[244]
    DIRECTION INPUT ;
    USE SIGNAL ;
    PORT
      LAYER M3 ;
        RECT  28.872 0 28.89 0.144 ;
    END
  END weight_bf16[244]
  PIN weight_bf16[245]
    DIRECTION INPUT ;
    USE SIGNAL ;
    PORT
      LAYER M5 ;
        RECT  28.896 0 28.92 0.192 ;
    END
  END weight_bf16[245]
  PIN weight_bf16[246]
    DIRECTION INPUT ;
    USE SIGNAL ;
    PORT
      LAYER M3 ;
        RECT  29.016 0 29.034 0.144 ;
    END
  END weight_bf16[246]
  PIN weight_bf16[247]
    DIRECTION INPUT ;
    USE SIGNAL ;
    PORT
      LAYER M5 ;
        RECT  29.04 0 29.064 0.192 ;
    END
  END weight_bf16[247]
  PIN weight_bf16[248]
    DIRECTION INPUT ;
    USE SIGNAL ;
    PORT
      LAYER M3 ;
        RECT  29.16 0 29.178 0.144 ;
    END
  END weight_bf16[248]
  PIN weight_bf16[249]
    DIRECTION INPUT ;
    USE SIGNAL ;
    PORT
      LAYER M5 ;
        RECT  29.184 0 29.208 0.192 ;
    END
  END weight_bf16[249]
  PIN weight_bf16[24]
    DIRECTION INPUT ;
    USE SIGNAL ;
    PORT
      LAYER M3 ;
        RECT  13.032 0 13.05 0.144 ;
    END
  END weight_bf16[24]
  PIN weight_bf16[250]
    DIRECTION INPUT ;
    USE SIGNAL ;
    PORT
      LAYER M3 ;
        RECT  29.304 0 29.322 0.144 ;
    END
  END weight_bf16[250]
  PIN weight_bf16[251]
    DIRECTION INPUT ;
    USE SIGNAL ;
    PORT
      LAYER M5 ;
        RECT  29.328 0 29.352 0.192 ;
    END
  END weight_bf16[251]
  PIN weight_bf16[252]
    DIRECTION INPUT ;
    USE SIGNAL ;
    PORT
      LAYER M3 ;
        RECT  29.448 0 29.466 0.144 ;
    END
  END weight_bf16[252]
  PIN weight_bf16[253]
    DIRECTION INPUT ;
    USE SIGNAL ;
    PORT
      LAYER M5 ;
        RECT  29.472 0 29.496 0.192 ;
    END
  END weight_bf16[253]
  PIN weight_bf16[254]
    DIRECTION INPUT ;
    USE SIGNAL ;
    PORT
      LAYER M3 ;
        RECT  29.592 0 29.61 0.144 ;
    END
  END weight_bf16[254]
  PIN weight_bf16[255]
    DIRECTION INPUT ;
    USE SIGNAL ;
    PORT
      LAYER M5 ;
        RECT  29.616 0 29.64 0.192 ;
    END
  END weight_bf16[255]
  PIN weight_bf16[25]
    DIRECTION INPUT ;
    USE SIGNAL ;
    PORT
      LAYER M5 ;
        RECT  13.056 0 13.08 0.192 ;
    END
  END weight_bf16[25]
  PIN weight_bf16[26]
    DIRECTION INPUT ;
    USE SIGNAL ;
    PORT
      LAYER M3 ;
        RECT  13.176 0 13.194 0.144 ;
    END
  END weight_bf16[26]
  PIN weight_bf16[27]
    DIRECTION INPUT ;
    USE SIGNAL ;
    PORT
      LAYER M5 ;
        RECT  13.2 0 13.224 0.192 ;
    END
  END weight_bf16[27]
  PIN weight_bf16[28]
    DIRECTION INPUT ;
    USE SIGNAL ;
    PORT
      LAYER M3 ;
        RECT  13.32 0 13.338 0.144 ;
    END
  END weight_bf16[28]
  PIN weight_bf16[29]
    DIRECTION INPUT ;
    USE SIGNAL ;
    PORT
      LAYER M5 ;
        RECT  13.344 0 13.368 0.192 ;
    END
  END weight_bf16[29]
  PIN weight_bf16[2]
    DIRECTION INPUT ;
    USE SIGNAL ;
    PORT
      LAYER M3 ;
        RECT  11.448 0 11.466 0.144 ;
    END
  END weight_bf16[2]
  PIN weight_bf16[30]
    DIRECTION INPUT ;
    USE SIGNAL ;
    PORT
      LAYER M3 ;
        RECT  13.464 0 13.482 0.144 ;
    END
  END weight_bf16[30]
  PIN weight_bf16[31]
    DIRECTION INPUT ;
    USE SIGNAL ;
    PORT
      LAYER M5 ;
        RECT  13.488 0 13.512 0.192 ;
    END
  END weight_bf16[31]
  PIN weight_bf16[32]
    DIRECTION INPUT ;
    USE SIGNAL ;
    PORT
      LAYER M3 ;
        RECT  13.608 0 13.626 0.144 ;
    END
  END weight_bf16[32]
  PIN weight_bf16[33]
    DIRECTION INPUT ;
    USE SIGNAL ;
    PORT
      LAYER M5 ;
        RECT  13.632 0 13.656 0.192 ;
    END
  END weight_bf16[33]
  PIN weight_bf16[34]
    DIRECTION INPUT ;
    USE SIGNAL ;
    PORT
      LAYER M3 ;
        RECT  13.752 0 13.77 0.144 ;
    END
  END weight_bf16[34]
  PIN weight_bf16[35]
    DIRECTION INPUT ;
    USE SIGNAL ;
    PORT
      LAYER M5 ;
        RECT  13.776 0 13.8 0.192 ;
    END
  END weight_bf16[35]
  PIN weight_bf16[36]
    DIRECTION INPUT ;
    USE SIGNAL ;
    PORT
      LAYER M3 ;
        RECT  13.896 0 13.914 0.144 ;
    END
  END weight_bf16[36]
  PIN weight_bf16[37]
    DIRECTION INPUT ;
    USE SIGNAL ;
    PORT
      LAYER M5 ;
        RECT  13.92 0 13.944 0.192 ;
    END
  END weight_bf16[37]
  PIN weight_bf16[38]
    DIRECTION INPUT ;
    USE SIGNAL ;
    PORT
      LAYER M3 ;
        RECT  14.04 0 14.058 0.144 ;
    END
  END weight_bf16[38]
  PIN weight_bf16[39]
    DIRECTION INPUT ;
    USE SIGNAL ;
    PORT
      LAYER M5 ;
        RECT  14.064 0 14.088 0.192 ;
    END
  END weight_bf16[39]
  PIN weight_bf16[3]
    DIRECTION INPUT ;
    USE SIGNAL ;
    PORT
      LAYER M5 ;
        RECT  11.472 0 11.496 0.192 ;
    END
  END weight_bf16[3]
  PIN weight_bf16[40]
    DIRECTION INPUT ;
    USE SIGNAL ;
    PORT
      LAYER M3 ;
        RECT  14.184 0 14.202 0.144 ;
    END
  END weight_bf16[40]
  PIN weight_bf16[41]
    DIRECTION INPUT ;
    USE SIGNAL ;
    PORT
      LAYER M5 ;
        RECT  14.208 0 14.232 0.192 ;
    END
  END weight_bf16[41]
  PIN weight_bf16[42]
    DIRECTION INPUT ;
    USE SIGNAL ;
    PORT
      LAYER M3 ;
        RECT  14.328 0 14.346 0.144 ;
    END
  END weight_bf16[42]
  PIN weight_bf16[43]
    DIRECTION INPUT ;
    USE SIGNAL ;
    PORT
      LAYER M5 ;
        RECT  14.352 0 14.376 0.192 ;
    END
  END weight_bf16[43]
  PIN weight_bf16[44]
    DIRECTION INPUT ;
    USE SIGNAL ;
    PORT
      LAYER M3 ;
        RECT  14.472 0 14.49 0.144 ;
    END
  END weight_bf16[44]
  PIN weight_bf16[45]
    DIRECTION INPUT ;
    USE SIGNAL ;
    PORT
      LAYER M5 ;
        RECT  14.496 0 14.52 0.192 ;
    END
  END weight_bf16[45]
  PIN weight_bf16[46]
    DIRECTION INPUT ;
    USE SIGNAL ;
    PORT
      LAYER M3 ;
        RECT  14.616 0 14.634 0.144 ;
    END
  END weight_bf16[46]
  PIN weight_bf16[47]
    DIRECTION INPUT ;
    USE SIGNAL ;
    PORT
      LAYER M5 ;
        RECT  14.64 0 14.664 0.192 ;
    END
  END weight_bf16[47]
  PIN weight_bf16[48]
    DIRECTION INPUT ;
    USE SIGNAL ;
    PORT
      LAYER M3 ;
        RECT  14.76 0 14.778 0.144 ;
    END
  END weight_bf16[48]
  PIN weight_bf16[49]
    DIRECTION INPUT ;
    USE SIGNAL ;
    PORT
      LAYER M5 ;
        RECT  14.784 0 14.808 0.192 ;
    END
  END weight_bf16[49]
  PIN weight_bf16[4]
    DIRECTION INPUT ;
    USE SIGNAL ;
    PORT
      LAYER M3 ;
        RECT  11.592 0 11.61 0.144 ;
    END
  END weight_bf16[4]
  PIN weight_bf16[50]
    DIRECTION INPUT ;
    USE SIGNAL ;
    PORT
      LAYER M3 ;
        RECT  14.904 0 14.922 0.144 ;
    END
  END weight_bf16[50]
  PIN weight_bf16[51]
    DIRECTION INPUT ;
    USE SIGNAL ;
    PORT
      LAYER M5 ;
        RECT  14.928 0 14.952 0.192 ;
    END
  END weight_bf16[51]
  PIN weight_bf16[52]
    DIRECTION INPUT ;
    USE SIGNAL ;
    PORT
      LAYER M3 ;
        RECT  15.048 0 15.066 0.144 ;
    END
  END weight_bf16[52]
  PIN weight_bf16[53]
    DIRECTION INPUT ;
    USE SIGNAL ;
    PORT
      LAYER M5 ;
        RECT  15.072 0 15.096 0.192 ;
    END
  END weight_bf16[53]
  PIN weight_bf16[54]
    DIRECTION INPUT ;
    USE SIGNAL ;
    PORT
      LAYER M3 ;
        RECT  15.192 0 15.21 0.144 ;
    END
  END weight_bf16[54]
  PIN weight_bf16[55]
    DIRECTION INPUT ;
    USE SIGNAL ;
    PORT
      LAYER M5 ;
        RECT  15.216 0 15.24 0.192 ;
    END
  END weight_bf16[55]
  PIN weight_bf16[56]
    DIRECTION INPUT ;
    USE SIGNAL ;
    PORT
      LAYER M3 ;
        RECT  15.336 0 15.354 0.144 ;
    END
  END weight_bf16[56]
  PIN weight_bf16[57]
    DIRECTION INPUT ;
    USE SIGNAL ;
    PORT
      LAYER M5 ;
        RECT  15.36 0 15.384 0.192 ;
    END
  END weight_bf16[57]
  PIN weight_bf16[58]
    DIRECTION INPUT ;
    USE SIGNAL ;
    PORT
      LAYER M3 ;
        RECT  15.48 0 15.498 0.144 ;
    END
  END weight_bf16[58]
  PIN weight_bf16[59]
    DIRECTION INPUT ;
    USE SIGNAL ;
    PORT
      LAYER M5 ;
        RECT  15.504 0 15.528 0.192 ;
    END
  END weight_bf16[59]
  PIN weight_bf16[5]
    DIRECTION INPUT ;
    USE SIGNAL ;
    PORT
      LAYER M5 ;
        RECT  11.616 0 11.64 0.192 ;
    END
  END weight_bf16[5]
  PIN weight_bf16[60]
    DIRECTION INPUT ;
    USE SIGNAL ;
    PORT
      LAYER M3 ;
        RECT  15.624 0 15.642 0.144 ;
    END
  END weight_bf16[60]
  PIN weight_bf16[61]
    DIRECTION INPUT ;
    USE SIGNAL ;
    PORT
      LAYER M5 ;
        RECT  15.648 0 15.672 0.192 ;
    END
  END weight_bf16[61]
  PIN weight_bf16[62]
    DIRECTION INPUT ;
    USE SIGNAL ;
    PORT
      LAYER M3 ;
        RECT  15.768 0 15.786 0.144 ;
    END
  END weight_bf16[62]
  PIN weight_bf16[63]
    DIRECTION INPUT ;
    USE SIGNAL ;
    PORT
      LAYER M5 ;
        RECT  15.792 0 15.816 0.192 ;
    END
  END weight_bf16[63]
  PIN weight_bf16[64]
    DIRECTION INPUT ;
    USE SIGNAL ;
    PORT
      LAYER M3 ;
        RECT  15.912 0 15.93 0.144 ;
    END
  END weight_bf16[64]
  PIN weight_bf16[65]
    DIRECTION INPUT ;
    USE SIGNAL ;
    PORT
      LAYER M5 ;
        RECT  15.936 0 15.96 0.192 ;
    END
  END weight_bf16[65]
  PIN weight_bf16[66]
    DIRECTION INPUT ;
    USE SIGNAL ;
    PORT
      LAYER M3 ;
        RECT  16.056 0 16.074 0.144 ;
    END
  END weight_bf16[66]
  PIN weight_bf16[67]
    DIRECTION INPUT ;
    USE SIGNAL ;
    PORT
      LAYER M5 ;
        RECT  16.08 0 16.104 0.192 ;
    END
  END weight_bf16[67]
  PIN weight_bf16[68]
    DIRECTION INPUT ;
    USE SIGNAL ;
    PORT
      LAYER M3 ;
        RECT  16.2 0 16.218 0.144 ;
    END
  END weight_bf16[68]
  PIN weight_bf16[69]
    DIRECTION INPUT ;
    USE SIGNAL ;
    PORT
      LAYER M5 ;
        RECT  16.224 0 16.248 0.192 ;
    END
  END weight_bf16[69]
  PIN weight_bf16[6]
    DIRECTION INPUT ;
    USE SIGNAL ;
    PORT
      LAYER M3 ;
        RECT  11.736 0 11.754 0.144 ;
    END
  END weight_bf16[6]
  PIN weight_bf16[70]
    DIRECTION INPUT ;
    USE SIGNAL ;
    PORT
      LAYER M3 ;
        RECT  16.344 0 16.362 0.144 ;
    END
  END weight_bf16[70]
  PIN weight_bf16[71]
    DIRECTION INPUT ;
    USE SIGNAL ;
    PORT
      LAYER M5 ;
        RECT  16.368 0 16.392 0.192 ;
    END
  END weight_bf16[71]
  PIN weight_bf16[72]
    DIRECTION INPUT ;
    USE SIGNAL ;
    PORT
      LAYER M3 ;
        RECT  16.488 0 16.506 0.144 ;
    END
  END weight_bf16[72]
  PIN weight_bf16[73]
    DIRECTION INPUT ;
    USE SIGNAL ;
    PORT
      LAYER M5 ;
        RECT  16.512 0 16.536 0.192 ;
    END
  END weight_bf16[73]
  PIN weight_bf16[74]
    DIRECTION INPUT ;
    USE SIGNAL ;
    PORT
      LAYER M3 ;
        RECT  16.632 0 16.65 0.144 ;
    END
  END weight_bf16[74]
  PIN weight_bf16[75]
    DIRECTION INPUT ;
    USE SIGNAL ;
    PORT
      LAYER M5 ;
        RECT  16.656 0 16.68 0.192 ;
    END
  END weight_bf16[75]
  PIN weight_bf16[76]
    DIRECTION INPUT ;
    USE SIGNAL ;
    PORT
      LAYER M3 ;
        RECT  16.776 0 16.794 0.144 ;
    END
  END weight_bf16[76]
  PIN weight_bf16[77]
    DIRECTION INPUT ;
    USE SIGNAL ;
    PORT
      LAYER M5 ;
        RECT  16.8 0 16.824 0.192 ;
    END
  END weight_bf16[77]
  PIN weight_bf16[78]
    DIRECTION INPUT ;
    USE SIGNAL ;
    PORT
      LAYER M3 ;
        RECT  16.92 0 16.938 0.144 ;
    END
  END weight_bf16[78]
  PIN weight_bf16[79]
    DIRECTION INPUT ;
    USE SIGNAL ;
    PORT
      LAYER M5 ;
        RECT  16.944 0 16.968 0.192 ;
    END
  END weight_bf16[79]
  PIN weight_bf16[7]
    DIRECTION INPUT ;
    USE SIGNAL ;
    PORT
      LAYER M5 ;
        RECT  11.76 0 11.784 0.192 ;
    END
  END weight_bf16[7]
  PIN weight_bf16[80]
    DIRECTION INPUT ;
    USE SIGNAL ;
    PORT
      LAYER M3 ;
        RECT  17.064 0 17.082 0.144 ;
    END
  END weight_bf16[80]
  PIN weight_bf16[81]
    DIRECTION INPUT ;
    USE SIGNAL ;
    PORT
      LAYER M5 ;
        RECT  17.088 0 17.112 0.192 ;
    END
  END weight_bf16[81]
  PIN weight_bf16[82]
    DIRECTION INPUT ;
    USE SIGNAL ;
    PORT
      LAYER M3 ;
        RECT  17.208 0 17.226 0.144 ;
    END
  END weight_bf16[82]
  PIN weight_bf16[83]
    DIRECTION INPUT ;
    USE SIGNAL ;
    PORT
      LAYER M5 ;
        RECT  17.232 0 17.256 0.192 ;
    END
  END weight_bf16[83]
  PIN weight_bf16[84]
    DIRECTION INPUT ;
    USE SIGNAL ;
    PORT
      LAYER M3 ;
        RECT  17.352 0 17.37 0.144 ;
    END
  END weight_bf16[84]
  PIN weight_bf16[85]
    DIRECTION INPUT ;
    USE SIGNAL ;
    PORT
      LAYER M5 ;
        RECT  17.376 0 17.4 0.192 ;
    END
  END weight_bf16[85]
  PIN weight_bf16[86]
    DIRECTION INPUT ;
    USE SIGNAL ;
    PORT
      LAYER M3 ;
        RECT  17.496 0 17.514 0.144 ;
    END
  END weight_bf16[86]
  PIN weight_bf16[87]
    DIRECTION INPUT ;
    USE SIGNAL ;
    PORT
      LAYER M5 ;
        RECT  17.52 0 17.544 0.192 ;
    END
  END weight_bf16[87]
  PIN weight_bf16[88]
    DIRECTION INPUT ;
    USE SIGNAL ;
    PORT
      LAYER M3 ;
        RECT  17.64 0 17.658 0.144 ;
    END
  END weight_bf16[88]
  PIN weight_bf16[89]
    DIRECTION INPUT ;
    USE SIGNAL ;
    PORT
      LAYER M5 ;
        RECT  17.664 0 17.688 0.192 ;
    END
  END weight_bf16[89]
  PIN weight_bf16[8]
    DIRECTION INPUT ;
    USE SIGNAL ;
    PORT
      LAYER M3 ;
        RECT  11.88 0 11.898 0.144 ;
    END
  END weight_bf16[8]
  PIN weight_bf16[90]
    DIRECTION INPUT ;
    USE SIGNAL ;
    PORT
      LAYER M3 ;
        RECT  17.784 0 17.802 0.144 ;
    END
  END weight_bf16[90]
  PIN weight_bf16[91]
    DIRECTION INPUT ;
    USE SIGNAL ;
    PORT
      LAYER M5 ;
        RECT  17.808 0 17.832 0.192 ;
    END
  END weight_bf16[91]
  PIN weight_bf16[92]
    DIRECTION INPUT ;
    USE SIGNAL ;
    PORT
      LAYER M3 ;
        RECT  17.928 0 17.946 0.144 ;
    END
  END weight_bf16[92]
  PIN weight_bf16[93]
    DIRECTION INPUT ;
    USE SIGNAL ;
    PORT
      LAYER M5 ;
        RECT  17.952 0 17.976 0.192 ;
    END
  END weight_bf16[93]
  PIN weight_bf16[94]
    DIRECTION INPUT ;
    USE SIGNAL ;
    PORT
      LAYER M3 ;
        RECT  18.072 0 18.09 0.144 ;
    END
  END weight_bf16[94]
  PIN weight_bf16[95]
    DIRECTION INPUT ;
    USE SIGNAL ;
    PORT
      LAYER M5 ;
        RECT  18.096 0 18.12 0.192 ;
    END
  END weight_bf16[95]
  PIN weight_bf16[96]
    DIRECTION INPUT ;
    USE SIGNAL ;
    PORT
      LAYER M3 ;
        RECT  18.216 0 18.234 0.144 ;
    END
  END weight_bf16[96]
  PIN weight_bf16[97]
    DIRECTION INPUT ;
    USE SIGNAL ;
    PORT
      LAYER M5 ;
        RECT  18.24 0 18.264 0.192 ;
    END
  END weight_bf16[97]
  PIN weight_bf16[98]
    DIRECTION INPUT ;
    USE SIGNAL ;
    PORT
      LAYER M3 ;
        RECT  18.36 0 18.378 0.144 ;
    END
  END weight_bf16[98]
  PIN weight_bf16[99]
    DIRECTION INPUT ;
    USE SIGNAL ;
    PORT
      LAYER M5 ;
        RECT  18.384 0 18.408 0.192 ;
    END
  END weight_bf16[99]
  PIN weight_bf16[9]
    DIRECTION INPUT ;
    USE SIGNAL ;
    PORT
      LAYER M5 ;
        RECT  11.904 0 11.928 0.192 ;
    END
  END weight_bf16[9]
  PIN VDD
    DIRECTION INOUT ;
    USE POWER ;
    PORT
      LAYER M5 ;
        RECT  67.392 2.151 67.512 32.409 ;
        RECT  61.992 2.151 62.112 32.409 ;
        RECT  56.592 2.151 56.712 32.409 ;
        RECT  51.192 2.151 51.312 32.409 ;
        RECT  45.792 2.151 45.912 32.409 ;
        RECT  40.392 2.151 40.512 32.409 ;
        RECT  34.992 2.151 35.112 32.409 ;
        RECT  29.592 2.151 29.712 32.409 ;
        RECT  24.192 2.151 24.312 32.409 ;
        RECT  18.792 2.151 18.912 32.409 ;
        RECT  13.392 2.151 13.512 32.409 ;
        RECT  7.992 2.151 8.112 32.409 ;
        RECT  2.592 2.151 2.712 32.409 ;
    END
  END VDD
  PIN VSS
    DIRECTION INOUT ;
    USE GROUND ;
    PORT
      LAYER M5 ;
        RECT  67.2 2.137 67.32 32.423 ;
        RECT  61.8 2.137 61.92 32.423 ;
        RECT  56.4 2.137 56.52 32.423 ;
        RECT  51 2.137 51.12 32.423 ;
        RECT  45.6 2.137 45.72 32.423 ;
        RECT  40.2 2.137 40.32 32.423 ;
        RECT  34.8 2.137 34.92 32.423 ;
        RECT  29.4 2.137 29.52 32.423 ;
        RECT  24 2.137 24.12 32.423 ;
        RECT  18.6 2.137 18.72 32.423 ;
        RECT  13.2 2.137 13.32 32.423 ;
        RECT  7.8 2.137 7.92 32.423 ;
        RECT  2.4 2.137 2.52 32.423 ;
    END
  END VSS
  # OT_OBS_CLOSED layer=M5 d_um=1.536 added=27
  OBS
    LAYER RVTN ;
     RECT  2.16 2.16 71.28 2.295 ;
     RECT  2.16 2.565 71.28 2.835 ;
     RECT  2.16 3.105 71.28 3.375 ;
     RECT  2.16 3.645 71.28 3.915 ;
     RECT  2.16 4.185 71.28 4.455 ;
     RECT  2.16 4.725 71.28 4.995 ;
     RECT  2.16 5.265 71.28 5.535 ;
     RECT  2.16 5.805 71.28 6.075 ;
     RECT  2.16 6.345 71.28 6.615 ;
     RECT  2.16 6.885 71.28 7.155 ;
     RECT  2.16 7.425 71.28 7.695 ;
     RECT  2.16 7.965 71.28 8.235 ;
     RECT  2.16 8.505 71.28 8.775 ;
     RECT  2.16 9.045 71.28 9.315 ;
     RECT  2.16 9.585 71.28 9.855 ;
     RECT  2.16 10.125 71.28 10.395 ;
     RECT  2.16 10.665 71.28 10.935 ;
     RECT  2.16 11.205 71.28 11.475 ;
     RECT  2.16 11.745 71.28 12.015 ;
     RECT  2.16 12.285 71.28 12.555 ;
     RECT  2.16 12.825 71.28 13.095 ;
     RECT  2.16 13.365 71.28 13.635 ;
     RECT  2.16 13.905 71.28 14.175 ;
     RECT  2.16 14.445 71.28 14.715 ;
     RECT  2.16 14.985 71.28 15.255 ;
     RECT  2.16 15.525 71.28 15.795 ;
     RECT  2.16 16.065 71.28 16.335 ;
     RECT  2.16 16.605 71.28 16.875 ;
     RECT  2.16 17.145 71.28 17.415 ;
     RECT  2.16 17.685 71.28 17.955 ;
     RECT  2.16 18.225 71.28 18.495 ;
     RECT  2.16 18.765 71.28 19.035 ;
     RECT  2.16 19.305 71.28 19.575 ;
     RECT  2.16 19.845 71.28 20.115 ;
     RECT  2.16 20.385 71.28 20.655 ;
     RECT  2.16 20.925 71.28 21.195 ;
     RECT  2.16 21.465 71.28 21.735 ;
     RECT  2.16 22.005 71.28 22.275 ;
     RECT  2.16 22.545 71.28 22.815 ;
     RECT  2.16 23.085 71.28 23.355 ;
     RECT  2.16 23.625 71.28 23.895 ;
     RECT  2.16 24.165 71.28 24.435 ;
     RECT  2.16 24.705 71.28 24.975 ;
     RECT  2.16 25.245 71.28 25.515 ;
     RECT  2.16 25.785 71.28 26.055 ;
     RECT  2.16 26.325 71.28 26.595 ;
     RECT  2.16 26.865 71.28 27.135 ;
     RECT  2.16 27.405 71.28 27.675 ;
     RECT  2.16 27.945 71.28 28.215 ;
     RECT  2.16 28.485 71.28 28.755 ;
     RECT  2.16 29.025 71.28 29.295 ;
     RECT  2.16 29.565 71.28 29.835 ;
     RECT  2.16 30.105 71.28 30.375 ;
     RECT  2.16 30.645 71.28 30.915 ;
     RECT  2.16 31.185 71.28 31.455 ;
     RECT  2.16 31.725 71.28 31.995 ;
     RECT  2.16 32.265 71.28 32.4 ;
    LAYER RVTP ;
     RECT  2.16 2.295 71.28 2.565 ;
     RECT  2.16 2.835 71.28 3.105 ;
     RECT  2.16 3.375 71.28 3.645 ;
     RECT  2.16 3.915 71.28 4.185 ;
     RECT  2.16 4.455 71.28 4.725 ;
     RECT  2.16 4.995 71.28 5.265 ;
     RECT  2.16 5.535 71.28 5.805 ;
     RECT  2.16 6.075 71.28 6.345 ;
     RECT  2.16 6.615 71.28 6.885 ;
     RECT  2.16 7.155 71.28 7.425 ;
     RECT  2.16 7.695 71.28 7.965 ;
     RECT  2.16 8.235 71.28 8.505 ;
     RECT  2.16 8.775 71.28 9.045 ;
     RECT  2.16 9.315 71.28 9.585 ;
     RECT  2.16 9.855 71.28 10.125 ;
     RECT  2.16 10.395 71.28 10.665 ;
     RECT  2.16 10.935 71.28 11.205 ;
     RECT  2.16 11.475 71.28 11.745 ;
     RECT  2.16 12.015 71.28 12.285 ;
     RECT  2.16 12.555 71.28 12.825 ;
     RECT  2.16 13.095 71.28 13.365 ;
     RECT  2.16 13.635 71.28 13.905 ;
     RECT  2.16 14.175 71.28 14.445 ;
     RECT  2.16 14.715 71.28 14.985 ;
     RECT  2.16 15.255 71.28 15.525 ;
     RECT  2.16 15.795 71.28 16.065 ;
     RECT  2.16 16.335 71.28 16.605 ;
     RECT  2.16 16.875 71.28 17.145 ;
     RECT  2.16 17.415 71.28 17.685 ;
     RECT  2.16 17.955 71.28 18.225 ;
     RECT  2.16 18.495 71.28 18.765 ;
     RECT  2.16 19.035 71.28 19.305 ;
     RECT  2.16 19.575 71.28 19.845 ;
     RECT  2.16 20.115 71.28 20.385 ;
     RECT  2.16 20.655 71.28 20.925 ;
     RECT  2.16 21.195 71.28 21.465 ;
     RECT  2.16 21.735 71.28 22.005 ;
     RECT  2.16 22.275 71.28 22.545 ;
     RECT  2.16 22.815 71.28 23.085 ;
     RECT  2.16 23.355 71.28 23.625 ;
     RECT  2.16 23.895 71.28 24.165 ;
     RECT  2.16 24.435 71.28 24.705 ;
     RECT  2.16 24.975 71.28 25.245 ;
     RECT  2.16 25.515 71.28 25.785 ;
     RECT  2.16 26.055 71.28 26.325 ;
     RECT  2.16 26.595 71.28 26.865 ;
     RECT  2.16 27.135 71.28 27.405 ;
     RECT  2.16 27.675 71.28 27.945 ;
     RECT  2.16 28.215 71.28 28.485 ;
     RECT  2.16 28.755 71.28 29.025 ;
     RECT  2.16 29.295 71.28 29.565 ;
     RECT  2.16 29.835 71.28 30.105 ;
     RECT  2.16 30.375 71.28 30.645 ;
     RECT  2.16 30.915 71.28 31.185 ;
     RECT  2.16 31.455 71.28 31.725 ;
     RECT  2.16 31.995 71.28 32.265 ;
    LAYER M1 ;
     RECT  2.16 2.151 71.28 32.409 ;
    LAYER M2 ;
     RECT  10.291 0.144 11.443 0.162 ;
     RECT  11.515 1.152 11.587 1.17 ;
     RECT  11.443 0.144 11.615 0.324 ;
     RECT  11.615 0.144 11.795 0.162 ;
     RECT  11.587 1.152 11.795 1.359 ;
     RECT  11.795 1.152 11.831 1.278 ;
     RECT  12.379 33.741 12.479 33.759 ;
     RECT  12.775 0.216 12.883 0.234 ;
     RECT  11.831 1.152 12.983 1.242 ;
     RECT  12.883 0.144 13.055 0.234 ;
     RECT  2.16 2.151 13.135 32.409 ;
     RECT  13.135 2.151 13.343 33.066 ;
     RECT  13.343 2.151 13.531 32.409 ;
     RECT  13.055 0.144 13.927 0.162 ;
     RECT  12.983 1.152 13.999 1.17 ;
     RECT  13.531 2.106 14.099 32.409 ;
     RECT  13.999 1.152 14.323 1.206 ;
     RECT  14.323 1.152 14.495 1.359 ;
     RECT  14.495 1.152 14.567 1.278 ;
     RECT  13.927 0.144 14.611 0.234 ;
     RECT  14.611 0.144 14.639 0.324 ;
     RECT  14.567 1.152 14.711 1.242 ;
     RECT  14.099 2.151 15.331 32.409 ;
     RECT  14.711 1.152 15.395 1.17 ;
     RECT  14.639 0.306 15.475 0.324 ;
     RECT  15.475 0.144 15.647 0.324 ;
     RECT  15.331 2.106 15.791 32.409 ;
     RECT  15.791 2.151 16.159 32.409 ;
     RECT  16.159 1.224 16.195 1.242 ;
     RECT  16.159 2.151 16.259 32.562 ;
     RECT  15.647 0.144 16.367 0.234 ;
     RECT  16.367 0.216 16.511 0.234 ;
     RECT  16.195 1.152 16.619 1.242 ;
     RECT  16.619 1.152 16.871 1.17 ;
     RECT  16.259 2.151 17.563 32.409 ;
     RECT  17.563 2.106 17.699 32.409 ;
     RECT  17.347 0.144 17.815 0.162 ;
     RECT  17.815 0.144 18.383 0.279 ;
     RECT  17.699 2.151 18.427 32.409 ;
     RECT  18.427 2.151 18.671 32.634 ;
     RECT  18.671 2.151 18.967 32.409 ;
     RECT  18.967 1.728 19.103 32.409 ;
     RECT  19.003 33.156 19.103 33.174 ;
     RECT  18.383 0.144 19.219 0.162 ;
     RECT  19.219 0.144 19.319 0.234 ;
     RECT  19.319 0.144 20.227 0.162 ;
     RECT  20.227 0.144 20.399 0.324 ;
     RECT  19.103 2.151 20.767 32.409 ;
     RECT  20.767 1.764 20.903 32.409 ;
     RECT  20.399 0.144 21.127 0.162 ;
     RECT  21.127 0.144 21.263 0.198 ;
     RECT  21.703 1.152 21.803 1.17 ;
     RECT  20.903 2.151 22.243 32.409 ;
     RECT  21.263 0.144 22.531 0.162 ;
     RECT  22.315 1.224 22.603 1.314 ;
     RECT  22.243 2.151 22.631 33.066 ;
     RECT  22.603 1.152 22.703 1.314 ;
     RECT  22.703 1.152 23.099 1.242 ;
     RECT  22.531 0.144 23.279 0.324 ;
     RECT  22.631 2.151 24.151 32.409 ;
     RECT  24.151 2.151 24.359 33.066 ;
     RECT  23.099 1.152 24.467 1.17 ;
     RECT  23.279 0.144 25.087 0.162 ;
     RECT  25.087 0.144 25.123 0.279 ;
     RECT  25.123 0.144 25.295 0.324 ;
     RECT  24.359 2.151 25.555 32.409 ;
     RECT  25.555 1.728 25.763 32.409 ;
     RECT  25.295 0.144 26.887 0.162 ;
     RECT  26.887 0.144 27.535 0.234 ;
     RECT  27.535 0.144 27.743 0.279 ;
     RECT  27.743 0.144 27.887 0.162 ;
     RECT  25.763 2.151 28.003 32.409 ;
     RECT  28.003 2.151 28.103 33.066 ;
     RECT  28.103 2.151 28.111 32.409 ;
     RECT  28.111 1.764 28.247 32.409 ;
     RECT  28.247 1.836 29.299 32.409 ;
     RECT  29.191 0.144 29.327 0.162 ;
     RECT  29.299 1.728 29.371 32.409 ;
     RECT  29.371 1.728 29.471 33.066 ;
     RECT  29.471 2.151 29.615 33.066 ;
     RECT  29.803 1.152 29.903 1.17 ;
     RECT  29.615 2.151 30.667 32.409 ;
     RECT  30.667 2.151 30.767 33.066 ;
     RECT  30.199 0.144 31.235 0.162 ;
     RECT  30.767 2.151 31.315 32.562 ;
     RECT  31.315 1.728 31.415 32.562 ;
     RECT  31.415 2.151 31.559 32.562 ;
     RECT  31.559 2.151 32.755 32.409 ;
     RECT  32.035 0.144 32.827 0.162 ;
     RECT  32.827 0.144 32.891 0.234 ;
     RECT  32.891 0.216 32.927 0.234 ;
     RECT  32.755 2.151 32.963 33.066 ;
     RECT  32.963 2.151 33.295 32.409 ;
     RECT  33.295 1.764 33.431 32.409 ;
     RECT  33.907 0.144 34.043 0.162 ;
     RECT  34.447 0.216 34.583 0.234 ;
     RECT  34.915 0.144 36.787 0.162 ;
     RECT  36.787 0.144 37.031 0.234 ;
     RECT  33.431 2.151 37.183 32.409 ;
     RECT  37.183 1.764 37.319 32.409 ;
     RECT  37.031 0.144 37.571 0.162 ;
     RECT  38.803 0.144 38.911 0.162 ;
     RECT  38.911 0.144 39.263 0.234 ;
     RECT  37.319 2.151 39.343 32.409 ;
     RECT  39.343 1.764 39.479 32.409 ;
     RECT  39.479 2.151 40.171 32.409 ;
     RECT  40.171 2.151 40.271 33.066 ;
     RECT  39.263 0.144 41.135 0.162 ;
     RECT  40.271 2.151 41.467 32.409 ;
     RECT  41.467 1.728 41.999 32.409 ;
     RECT  42.331 0.144 43.295 0.162 ;
     RECT  44.167 0.144 44.887 0.162 ;
     RECT  44.887 34.398 44.987 34.488 ;
     RECT  41.999 2.151 45.067 32.409 ;
     RECT  45.067 2.151 45.167 33.066 ;
     RECT  44.887 0.144 45.311 0.594 ;
     RECT  44.987 34.398 45.751 34.416 ;
     RECT  45.167 2.151 46.003 32.409 ;
     RECT  46.003 1.728 46.247 32.409 ;
     RECT  45.751 34.398 46.391 34.488 ;
     RECT  45.311 0.144 46.651 0.162 ;
     RECT  46.651 0.144 46.715 0.234 ;
     RECT  46.715 0.216 46.751 0.234 ;
     RECT  46.247 2.151 46.867 32.409 ;
     RECT  46.867 2.151 46.967 33.066 ;
     RECT  47.443 0.144 48.055 0.162 ;
     RECT  48.055 0.144 48.595 0.198 ;
     RECT  48.595 0.144 48.739 0.234 ;
     RECT  48.739 0.144 48.839 0.279 ;
     RECT  48.839 0.144 48.875 0.234 ;
     RECT  48.875 0.144 48.911 0.162 ;
     RECT  48.811 1.152 48.983 1.17 ;
     RECT  46.967 2.151 49.351 32.409 ;
     RECT  49.351 1.728 49.775 32.409 ;
     RECT  49.775 2.151 50.935 32.409 ;
     RECT  50.935 2.151 51.215 33.066 ;
     RECT  51.215 2.151 71.28 32.409 ;
     RECT  71.28 12.258 71.879 22.734 ;
     RECT  71.879 15.696 71.915 22.734 ;
     RECT  71.879 12.258 72.383 14.814 ;
     RECT  71.915 15.696 72.383 21.384 ;
     RECT  71.915 22.176 72.383 22.734 ;
     RECT  72.383 12.258 72.419 13.392 ;
     RECT  72.383 14.796 72.419 14.814 ;
     RECT  72.383 16.344 72.419 18.792 ;
     RECT  72.383 20.358 72.419 21.186 ;
     RECT  72.419 12.528 72.455 13.392 ;
     RECT  72.419 17.586 72.455 18.792 ;
     RECT  72.419 21.168 72.455 21.186 ;
     RECT  71.28 23.598 72.455 23.616 ;
     RECT  72.455 12.834 72.491 13.392 ;
     RECT  72.455 18.198 72.491 18.216 ;
     RECT  72.491 12.996 72.527 13.014 ;
     RECT  72.427 22.788 72.527 22.806 ;
    LAYER M3 ;
     RECT  9 0.108 50.922 1.723 ;
     RECT  8.712 1.723 50.922 2.143 ;
     RECT  8.712 2.143 51.105 2.255 ;
     RECT  2.415 2.143 2.505 2.413 ;
     RECT  7.815 2.143 7.905 2.413 ;
     RECT  8.892 2.255 51.105 2.413 ;
     RECT  56.415 2.143 56.505 2.413 ;
     RECT  61.815 2.143 61.905 2.413 ;
     RECT  67.215 2.143 67.305 2.413 ;
     RECT  53.1 1.723 53.37 2.489 ;
     RECT  53.28 2.489 53.37 2.641 ;
     RECT  8.892 2.413 51.297 2.759 ;
     RECT  9 2.759 51.297 3.101 ;
     RECT  9.072 3.101 51.297 4.261 ;
     RECT  9.036 4.261 51.297 4.379 ;
     RECT  9.324 4.379 51.297 4.531 ;
     RECT  9.324 4.531 51.39 4.685 ;
     RECT  9.432 4.685 51.39 5.503 ;
     RECT  9.432 5.503 51.894 5.701 ;
     RECT  9.432 5.701 52.002 6.007 ;
     RECT  9.396 6.007 52.002 6.151 ;
     RECT  53.28 2.641 53.73 6.277 ;
     RECT  9.396 6.151 52.362 6.421 ;
     RECT  53.172 6.277 53.73 6.421 ;
     RECT  9.396 6.421 53.73 6.539 ;
     RECT  9.396 6.539 53.334 6.647 ;
     RECT  9.396 6.647 52.686 6.691 ;
     RECT  9.072 6.691 52.686 6.917 ;
     RECT  9.072 6.917 52.47 7.655 ;
     RECT  10.296 7.655 52.47 7.961 ;
     RECT  9.072 7.655 9.558 7.997 ;
     RECT  9.324 7.997 9.558 8.537 ;
     RECT  10.296 7.961 52.218 8.671 ;
     RECT  10.008 8.671 52.218 8.909 ;
     RECT  10.26 8.909 52.218 10.049 ;
     RECT  10.332 10.049 52.218 11.281 ;
     RECT  70.128 11.371 70.146 11.551 ;
     RECT  70.128 11.551 70.542 11.749 ;
     RECT  69.552 11.749 70.542 11.785 ;
     RECT  69.552 11.785 70.938 11.947 ;
     RECT  69.552 11.947 70.974 12.091 ;
     RECT  10.332 11.281 52.47 12.317 ;
     RECT  68.976 12.091 70.974 12.325 ;
     RECT  68.976 12.325 71.01 12.361 ;
     RECT  68.976 12.361 71.154 12.523 ;
     RECT  72.396 12.253 72.414 12.523 ;
     RECT  50.58 12.317 52.47 12.557 ;
     RECT  67.215 2.413 67.497 12.631 ;
     RECT  72.396 12.523 72.45 12.829 ;
     RECT  68.94 12.523 71.154 12.901 ;
     RECT  50.724 12.557 52.47 12.929 ;
     RECT  72.396 12.829 72.486 12.991 ;
     RECT  68.76 12.901 71.154 13.063 ;
     RECT  72.396 12.991 72.522 13.063 ;
     RECT  67.215 12.631 67.986 13.261 ;
     RECT  68.76 13.063 72.522 13.261 ;
     RECT  9.36 13.297 9.378 13.333 ;
     RECT  7.815 2.413 8.097 13.369 ;
     RECT  67.215 13.261 72.522 13.421 ;
     RECT  7.815 13.369 8.622 13.441 ;
     RECT  9.36 13.333 9.594 13.441 ;
     RECT  10.332 12.317 49.806 13.441 ;
     RECT  67.215 13.421 72.486 13.469 ;
     RECT  7.815 13.441 49.806 13.559 ;
     RECT  66.456 13.441 66.474 13.559 ;
     RECT  67.215 13.469 71.01 13.603 ;
     RECT  71.82 13.469 72.486 13.709 ;
     RECT  8.928 13.559 49.806 13.829 ;
     RECT  71.82 13.709 72.45 13.853 ;
     RECT  2.415 2.413 2.697 14.179 ;
     RECT  2.415 14.179 3.15 14.203 ;
     RECT  2.412 14.203 3.15 14.215 ;
     RECT  66.528 13.603 71.01 14.215 ;
     RECT  2.412 14.215 3.726 14.243 ;
     RECT  9.144 13.829 49.806 14.279 ;
     RECT  66.528 14.215 71.262 14.429 ;
     RECT  2.415 14.243 3.726 14.485 ;
     RECT  9.144 14.279 49.59 14.611 ;
     RECT  66.528 14.429 70.974 14.669 ;
     RECT  67.215 14.669 70.974 14.675 ;
     RECT  7.815 13.559 8.097 14.677 ;
     RECT  9 14.611 49.59 14.677 ;
     RECT  7.815 14.677 49.59 14.717 ;
     RECT  72.36 13.853 72.45 14.717 ;
     RECT  2.415 14.485 4.482 14.719 ;
     RECT  8.964 14.717 49.59 14.765 ;
     RECT  2.415 14.719 4.986 14.791 ;
     RECT  72.36 14.717 72.414 14.861 ;
     RECT  2.415 14.791 5.166 14.909 ;
     RECT  9 14.765 49.59 14.909 ;
     RECT  72.36 14.861 72.378 14.953 ;
     RECT  2.415 14.909 4.986 15.016 ;
     RECT  2.34 15.016 4.986 15.061 ;
     RECT  2.304 15.061 4.986 15.163 ;
     RECT  2.268 15.163 4.986 15.179 ;
     RECT  2.268 15.179 4.518 15.449 ;
     RECT  2.268 15.449 3.114 15.485 ;
     RECT  9.576 14.909 49.59 15.521 ;
     RECT  2.268 15.485 2.754 15.719 ;
     RECT  2.268 15.719 2.697 15.755 ;
     RECT  71.82 14.953 72.378 15.869 ;
     RECT  67.215 14.675 70.938 15.871 ;
     RECT  72.36 15.869 72.378 16.123 ;
     RECT  67.215 15.871 71.262 16.141 ;
     RECT  4.5 15.449 4.518 16.169 ;
     RECT  66.708 16.141 71.262 16.375 ;
     RECT  66.564 16.375 71.262 16.565 ;
     RECT  67.104 16.565 71.262 16.699 ;
     RECT  9.648 15.521 49.59 16.951 ;
     RECT  67.104 16.699 71.334 16.979 ;
     RECT  67.104 16.979 70.902 17.069 ;
     RECT  67.104 17.069 70.866 17.117 ;
     RECT  7.815 14.717 8.097 17.131 ;
     RECT  9.504 16.951 49.59 17.131 ;
     RECT  72.36 16.123 72.414 17.413 ;
     RECT  66.276 17.455 66.294 17.501 ;
     RECT  71.82 17.413 72.414 17.581 ;
     RECT  67.215 17.117 70.866 17.959 ;
     RECT  67.215 17.959 70.938 18.121 ;
     RECT  66.564 18.121 70.938 18.139 ;
     RECT  71.82 17.581 72.45 18.139 ;
     RECT  7.815 17.131 49.59 18.149 ;
     RECT  66.564 18.139 72.45 18.193 ;
     RECT  66.564 18.193 72.486 18.221 ;
     RECT  66.708 18.221 72.486 18.269 ;
     RECT  56.415 2.413 56.697 18.421 ;
     RECT  9 18.149 49.59 18.455 ;
     RECT  55.692 18.421 56.697 18.461 ;
     RECT  56.052 18.461 56.697 18.571 ;
     RECT  9 18.455 9.198 18.689 ;
     RECT  67.215 18.269 72.486 18.749 ;
     RECT  9.18 18.689 9.198 18.761 ;
     RECT  56.052 18.571 57.258 18.797 ;
     RECT  67.215 18.749 72.45 18.802 ;
     RECT  56.052 18.797 56.697 18.803 ;
     RECT  67.215 18.802 72.414 19.051 ;
     RECT  9.936 18.455 49.59 19.229 ;
     RECT  10.944 19.229 49.59 19.339 ;
     RECT  10.944 19.339 49.77 19.379 ;
     RECT  51.015 12.929 52.47 19.651 ;
     RECT  66.348 19.195 66.366 19.651 ;
     RECT  67.212 19.051 72.414 19.651 ;
     RECT  66.348 19.651 72.414 19.769 ;
     RECT  68.904 19.769 72.414 20.155 ;
     RECT  10.944 19.379 49.59 20.191 ;
     RECT  50.364 19.651 52.47 20.191 ;
     RECT  10.944 20.191 52.47 20.389 ;
     RECT  68.904 20.155 72.45 20.579 ;
     RECT  66.348 19.769 66.366 20.587 ;
     RECT  67.215 19.769 67.986 20.587 ;
     RECT  66.132 20.587 66.366 20.615 ;
     RECT  67.176 20.587 68.058 20.731 ;
     RECT  67.176 20.731 68.166 20.929 ;
     RECT  68.976 20.579 72.45 21.019 ;
     RECT  66.996 20.929 68.166 21.029 ;
     RECT  61.815 2.413 62.097 21.091 ;
     RECT  61.704 21.091 62.097 21.149 ;
     RECT  67.176 21.029 68.166 21.149 ;
     RECT  9.936 19.229 9.954 21.361 ;
     RECT  67.212 21.149 68.166 21.469 ;
     RECT  67.212 21.469 68.238 21.505 ;
     RECT  68.976 21.019 72.522 21.505 ;
     RECT  9.936 21.361 9.99 21.533 ;
     RECT  66.132 20.615 66.15 21.667 ;
     RECT  67.212 21.505 72.522 21.767 ;
     RECT  65.664 21.667 66.15 21.901 ;
     RECT  67.212 21.767 70.83 21.901 ;
     RECT  65.664 21.901 70.83 21.929 ;
     RECT  66.096 21.929 70.758 21.965 ;
     RECT  66.6 21.965 70.758 22.109 ;
     RECT  66.6 22.109 67.497 22.235 ;
     RECT  68.4 22.109 70.758 22.235 ;
     RECT  71.82 21.767 72.522 22.613 ;
     RECT  71.928 22.613 72.522 22.739 ;
     RECT  72.432 22.739 72.522 22.811 ;
     RECT  68.472 22.235 70.758 22.855 ;
     RECT  68.472 22.855 70.974 23.009 ;
     RECT  68.76 23.009 70.794 23.279 ;
     RECT  72.432 22.811 72.45 23.621 ;
     RECT  69.012 23.279 70.11 23.729 ;
     RECT  70.092 23.729 70.11 23.819 ;
     RECT  69.012 23.729 69.03 23.891 ;
     RECT  9.972 21.533 9.99 25.051 ;
     RECT  10.8 20.389 52.47 25.051 ;
     RECT  9.972 25.051 52.47 26.095 ;
     RECT  9.648 26.095 52.47 26.627 ;
     RECT  10.476 26.627 52.47 26.663 ;
     RECT  9.648 26.627 9.666 26.669 ;
     RECT  10.548 26.663 52.47 30.811 ;
     RECT  10.512 30.811 52.47 30.955 ;
     RECT  10.44 30.955 52.47 31.379 ;
     RECT  10.656 31.379 52.47 31.523 ;
     RECT  10.656 31.523 52.326 31.649 ;
     RECT  9.36 31.621 9.378 31.729 ;
     RECT  9.36 31.729 9.846 31.919 ;
     RECT  10.728 31.649 52.326 31.919 ;
     RECT  9.36 31.919 9.702 31.955 ;
     RECT  10.728 31.919 51.678 31.955 ;
     RECT  2.415 15.755 2.697 32.147 ;
     RECT  7.815 18.149 8.097 32.147 ;
     RECT  56.415 18.803 56.697 32.147 ;
     RECT  61.815 21.149 62.097 32.147 ;
     RECT  67.215 22.235 67.497 32.147 ;
     RECT  10.98 31.955 51.678 32.189 ;
     RECT  10.98 32.189 51.606 32.225 ;
     RECT  11.124 32.225 51.39 32.261 ;
     RECT  11.232 32.261 51.39 32.333 ;
     RECT  2.415 32.147 2.505 32.417 ;
     RECT  7.815 32.147 7.905 32.417 ;
     RECT  56.415 32.147 56.505 32.417 ;
     RECT  61.815 32.147 61.905 32.417 ;
     RECT  67.215 32.147 67.305 32.417 ;
     RECT  11.232 32.333 51.21 33.149 ;
     RECT  11.736 33.149 51.21 34.428 ;
     RECT  44.892 34.428 44.982 34.493 ;
     RECT  45.756 34.428 46.386 34.493 ;
    LAYER M4 ;
     RECT  0.156 14.88 0.181 15.192 ;
     RECT  0.181 14.88 0.227 16.056 ;
     RECT  0.227 15.024 2.401 16.056 ;
     RECT  2.401 14.208 2.408 16.056 ;
     RECT  2.408 2.148 2.512 32.412 ;
     RECT  2.512 2.418 2.704 32.142 ;
     RECT  2.704 14.208 2.915 14.712 ;
     RECT  2.915 14.688 7.808 14.712 ;
     RECT  2.704 16.032 7.808 16.056 ;
     RECT  7.808 2.148 7.912 32.412 ;
     RECT  7.912 2.148 8.104 32.142 ;
     RECT  8.104 14.688 8.627 14.76 ;
     RECT  8.104 13.392 8.668 13.656 ;
     RECT  8.104 17.136 8.813 17.64 ;
     RECT  8.668 13.632 9.137 13.656 ;
     RECT  9.125 0.576 9.208 0.6 ;
     RECT  9.208 0.528 9.209 0.6 ;
     RECT  9.209 0.528 9.347 0.552 ;
     RECT  8.104 7.968 9.353 7.992 ;
     RECT  8.701 1.728 9.385 1.752 ;
     RECT  8.627 14.736 9.605 14.76 ;
     RECT  8.104 16.032 9.817 16.056 ;
     RECT  8.813 17.136 9.817 17.16 ;
     RECT  9.457 3.408 9.923 3.432 ;
     RECT  9.745 14.256 10.325 14.28 ;
     RECT  9.817 15.408 10.325 16.056 ;
     RECT  10.069 3.936 10.393 4.008 ;
     RECT  9.817 17.136 10.433 17.64 ;
     RECT  9.385 6.528 10.465 6.552 ;
     RECT  10.393 3.936 10.573 4.584 ;
     RECT  10.573 3.936 10.604 5.16 ;
     RECT  10.465 6.528 10.604 7.224 ;
     RECT  9.385 1.728 10.645 2.328 ;
     RECT  10.433 17.136 10.789 17.16 ;
     RECT  10.789 17.04 10.829 17.16 ;
     RECT  10.325 16.032 10.837 16.056 ;
     RECT  10.829 17.04 10.837 17.064 ;
     RECT  10.837 16.032 10.924 17.064 ;
     RECT  10.645 1.104 10.931 2.328 ;
     RECT  10.465 10.848 11.009 10.872 ;
     RECT  10.931 1.728 11.036 2.328 ;
     RECT  11.036 24.48 11.077 24.504 ;
     RECT  10.604 3.936 11.153 7.224 ;
     RECT  11.153 3.936 11.189 5.736 ;
     RECT  11.036 1.728 11.221 2.904 ;
     RECT  11.189 3.936 11.221 5.112 ;
     RECT  11.077 24.48 11.329 25.128 ;
     RECT  9.637 26.64 11.329 26.664 ;
     RECT  11.221 1.728 11.356 5.112 ;
     RECT  11.317 31.92 11.365 31.944 ;
     RECT  11.365 31.344 11.401 31.944 ;
     RECT  11.221 33.12 11.401 33.144 ;
     RECT  10.681 14.688 11.437 14.856 ;
     RECT  11.329 24.48 11.549 26.664 ;
     RECT  11.153 7.2 11.581 7.224 ;
     RECT  9.997 8.88 11.581 8.904 ;
     RECT  11.293 23.328 11.605 23.352 ;
     RECT  11.549 24.48 11.605 24.504 ;
     RECT  11.461 0.576 11.657 0.6 ;
     RECT  11.581 7.2 11.665 8.904 ;
     RECT  11.437 14.496 11.701 14.856 ;
     RECT  11.701 13.68 11.725 14.856 ;
     RECT  11.401 31.344 11.795 33.144 ;
     RECT  11.795 31.344 11.941 31.992 ;
     RECT  10.924 17.04 11.948 17.064 ;
     RECT  11.356 1.728 11.981 1.848 ;
     RECT  11.948 17.04 11.989 17.352 ;
     RECT  10.924 16.032 12.049 16.056 ;
     RECT  11.989 17.04 12.049 17.544 ;
     RECT  11.725 13.68 12.085 15 ;
     RECT  12.049 16.032 12.085 17.544 ;
     RECT  11.605 23.328 12.125 24.504 ;
     RECT  11.795 33.024 12.181 33.144 ;
     RECT  11.725 22.176 12.193 22.2 ;
     RECT  12.125 23.328 12.193 23.352 ;
     RECT  12.049 10.8 12.229 10.824 ;
     RECT  10.285 19.2 12.301 19.224 ;
     RECT  11.356 2.832 12.373 5.112 ;
     RECT  12.085 13.68 12.373 17.544 ;
     RECT  11.665 7.2 12.517 7.224 ;
     RECT  12.125 24.48 12.517 24.504 ;
     RECT  11.549 25.872 12.517 26.664 ;
     RECT  12.229 10.8 12.527 10.872 ;
     RECT  12.517 6.816 12.553 7.224 ;
     RECT  12.517 27.984 12.553 28.008 ;
     RECT  12.373 2.832 12.589 5.16 ;
     RECT  12.553 27.888 12.613 28.008 ;
     RECT  12.589 29.184 12.613 29.208 ;
     RECT  12.553 6.672 12.661 7.224 ;
     RECT  12.613 27.888 12.757 29.208 ;
     RECT  12.527 9.984 12.769 10.872 ;
     RECT  12.049 12 12.769 12.024 ;
     RECT  12.661 21.12 12.985 21.144 ;
     RECT  12.193 22.176 12.985 23.352 ;
     RECT  12.769 9.984 12.997 12.024 ;
     RECT  12.373 13.104 12.997 17.544 ;
     RECT  12.517 24.48 12.997 26.664 ;
     RECT  12.757 27.888 12.997 29.304 ;
     RECT  12.997 9.984 13.093 17.544 ;
     RECT  12.301 19.2 13.129 20.088 ;
     RECT  12.997 24.48 13.129 29.304 ;
     RECT  13.129 24.48 13.165 29.784 ;
     RECT  11.981 1.728 13.208 1.8 ;
     RECT  12.589 2.832 13.208 5.208 ;
     RECT  12.661 6.672 13.208 7.368 ;
     RECT  11.665 8.88 13.208 8.904 ;
     RECT  13.093 9.984 13.208 17.64 ;
     RECT  13.129 18.768 13.208 20.088 ;
     RECT  12.985 21.12 13.208 23.352 ;
     RECT  13.165 24.384 13.208 29.784 ;
     RECT  11.941 30.768 13.208 31.992 ;
     RECT  12.181 33.024 13.208 33.672 ;
     RECT  13.093 0.288 13.235 0.312 ;
     RECT  13.208 1.728 13.504 33.672 ;
     RECT  13.504 1.728 13.619 2.088 ;
     RECT  13.504 17.616 13.907 19.992 ;
     RECT  13.619 1.728 14.053 1.752 ;
     RECT  13.504 21.12 14.213 31.944 ;
     RECT  14.053 1.152 14.245 1.752 ;
     RECT  14.213 21.12 14.285 21.72 ;
     RECT  13.504 33.072 14.341 33.672 ;
     RECT  14.245 0.576 14.389 1.752 ;
     RECT  14.341 33.072 14.483 33.768 ;
     RECT  14.213 22.8 14.485 31.944 ;
     RECT  14.483 33.072 14.485 33.672 ;
     RECT  14.389 0.288 14.531 1.752 ;
     RECT  13.504 3.312 14.537 4.584 ;
     RECT  14.485 22.8 14.617 33.672 ;
     RECT  14.531 1.152 14.641 1.752 ;
     RECT  14.617 22.8 14.681 23.352 ;
     RECT  14.537 3.312 14.713 3.96 ;
     RECT  14.641 1.152 14.717 1.8 ;
     RECT  13.907 19.392 14.821 19.992 ;
     RECT  14.285 21.12 14.821 21.672 ;
     RECT  14.821 19.392 14.825 21.672 ;
     RECT  14.717 1.728 14.917 1.8 ;
     RECT  14.713 2.832 14.917 3.96 ;
     RECT  13.504 10.176 14.969 16.392 ;
     RECT  13.504 6.672 15.037 7.368 ;
     RECT  13.907 17.616 15.203 18.216 ;
     RECT  15.203 17.616 15.253 17.976 ;
     RECT  14.969 15.84 15.289 16.392 ;
     RECT  15.253 17.568 15.289 17.976 ;
     RECT  14.917 1.728 15.395 3.96 ;
     RECT  14.969 10.176 15.397 14.856 ;
     RECT  15.289 15.84 15.401 17.976 ;
     RECT  14.825 19.92 15.509 21.672 ;
     RECT  15.397 10.128 15.545 14.856 ;
     RECT  15.037 6.672 15.548 8.328 ;
     RECT  15.545 10.224 15.617 14.856 ;
     RECT  15.548 6.672 15.635 8.808 ;
     RECT  15.617 10.704 15.653 14.856 ;
     RECT  14.681 23.328 15.685 23.352 ;
     RECT  14.617 24.48 15.685 33.672 ;
     RECT  15.395 2.832 15.697 3.96 ;
     RECT  15.653 10.704 15.697 14.808 ;
     RECT  15.401 15.936 15.725 17.976 ;
     RECT  15.697 3.408 15.749 3.96 ;
     RECT  15.685 23.328 15.781 33.672 ;
     RECT  15.697 11.952 15.805 14.808 ;
     RECT  15.509 19.92 15.805 20.04 ;
     RECT  15.509 21.264 15.893 21.672 ;
     RECT  15.781 22.8 15.893 33.672 ;
     RECT  15.893 21.264 15.977 33.672 ;
     RECT  15.725 15.936 16.013 17.688 ;
     RECT  15.805 12.336 16.019 14.808 ;
     RECT  15.635 6.672 16.085 7.992 ;
     RECT  16.045 0.576 16.129 0.6 ;
     RECT  16.085 6.672 16.153 6.696 ;
     RECT  16.153 6.288 16.193 6.696 ;
     RECT  15.977 21.264 16.193 21.528 ;
     RECT  16.013 15.936 16.373 16.056 ;
     RECT  15.395 1.728 16.403 1.848 ;
     RECT  16.403 1.728 16.513 1.8 ;
     RECT  15.977 22.512 16.645 33.672 ;
     RECT  15.749 3.408 16.693 4.584 ;
     RECT  16.693 3.216 16.739 4.584 ;
     RECT  15.805 19.92 16.801 19.992 ;
     RECT  15.697 10.704 16.837 10.872 ;
     RECT  16.019 12.336 16.837 14.424 ;
     RECT  16.645 22.512 16.841 33.72 ;
     RECT  16.739 3.216 16.873 4.056 ;
     RECT  16.841 22.512 16.949 33.672 ;
     RECT  16.837 9.888 16.981 10.872 ;
     RECT  16.837 11.952 16.981 14.424 ;
     RECT  16.085 7.968 17.053 7.992 ;
     RECT  16.013 17.568 17.053 17.688 ;
     RECT  17.053 7.968 17.093 8.28 ;
     RECT  16.193 6.288 17.125 6.312 ;
     RECT  17.053 17.568 17.125 17.736 ;
     RECT  16.801 19.392 17.125 19.992 ;
     RECT  17.125 5.664 17.161 6.312 ;
     RECT  16.981 9.888 17.161 14.424 ;
     RECT  16.193 21.504 17.161 21.528 ;
     RECT  16.949 22.512 17.161 23.928 ;
     RECT  17.161 5.664 17.209 6.888 ;
     RECT  17.125 19.392 17.221 20.04 ;
     RECT  17.161 21.504 17.221 23.928 ;
     RECT  17.221 19.392 17.237 23.928 ;
     RECT  17.209 6.288 17.273 6.888 ;
     RECT  16.513 1.104 17.413 1.8 ;
     RECT  16.873 2.832 17.413 4.056 ;
     RECT  17.273 6.288 17.453 6.408 ;
     RECT  17.125 17.472 17.521 17.736 ;
     RECT  17.161 9.888 17.557 14.856 ;
     RECT  17.521 17.232 17.557 18.216 ;
     RECT  17.237 19.392 17.557 20.568 ;
     RECT  17.413 1.104 17.621 4.056 ;
     RECT  17.557 9.888 17.653 14.952 ;
     RECT  17.621 0.576 17.749 4.056 ;
     RECT  17.653 9.888 17.797 15 ;
     RECT  16.373 16.032 17.797 16.056 ;
     RECT  17.749 0.288 17.813 4.584 ;
     RECT  16.949 25.104 17.845 33.672 ;
     RECT  17.845 25.104 17.987 33.768 ;
     RECT  17.557 17.232 18.044 20.568 ;
     RECT  17.237 21.648 18.061 23.928 ;
     RECT  17.987 25.104 18.061 33.72 ;
     RECT  17.813 0.288 18.197 0.312 ;
     RECT  18.044 17.088 18.229 20.568 ;
     RECT  18.061 21.648 18.229 33.72 ;
     RECT  18.197 0.192 18.281 0.312 ;
     RECT  17.453 6.384 18.313 6.408 ;
     RECT  17.093 8.256 18.565 8.28 ;
     RECT  17.813 1.728 18.608 4.584 ;
     RECT  18.313 6.384 18.608 6.888 ;
     RECT  18.565 8.256 18.608 8.856 ;
     RECT  17.797 9.888 18.608 16.056 ;
     RECT  18.229 17.088 18.608 33.72 ;
     RECT  18.281 0.288 18.805 0.312 ;
     RECT  18.608 1.728 18.904 33.72 ;
     RECT  18.904 21.072 19.073 25.176 ;
     RECT  18.904 9.888 19.109 18.024 ;
     RECT  18.904 1.728 19.181 4.728 ;
     RECT  18.805 0.288 19.187 0.6 ;
     RECT  19.073 22.752 19.261 25.176 ;
     RECT  19.109 9.888 19.379 16.056 ;
     RECT  18.904 31.92 19.381 33.72 ;
     RECT  19.379 9.888 19.433 12.84 ;
     RECT  19.379 13.824 19.433 16.056 ;
     RECT  19.381 31.92 19.469 33.768 ;
     RECT  19.073 21.072 19.571 21.672 ;
     RECT  19.433 14.832 19.757 16.056 ;
     RECT  19.469 31.92 19.763 33.72 ;
     RECT  18.904 7.968 19.865 8.856 ;
     RECT  19.261 23.904 19.865 25.176 ;
     RECT  18.904 26.208 19.957 30.84 ;
     RECT  18.904 6.816 19.964 6.84 ;
     RECT  19.181 1.728 19.973 4.584 ;
     RECT  19.433 13.824 19.973 13.848 ;
     RECT  19.187 0.576 20.009 0.6 ;
     RECT  19.964 6.816 20.051 7.416 ;
     RECT  19.957 26.208 20.101 30.936 ;
     RECT  19.763 31.92 20.101 33.672 ;
     RECT  19.261 22.752 20.117 22.872 ;
     RECT  19.865 8.832 20.185 8.856 ;
     RECT  18.904 19.008 20.221 20.088 ;
     RECT  20.185 8.832 20.225 9.096 ;
     RECT  19.757 15.312 20.257 16.056 ;
     RECT  20.221 18.816 20.305 20.088 ;
     RECT  19.433 10.176 20.339 12.84 ;
     RECT  20.305 19.008 20.389 20.088 ;
     RECT  19.571 21.072 20.389 21.096 ;
     RECT  20.101 26.208 20.405 33.672 ;
     RECT  20.339 12.528 20.437 12.84 ;
     RECT  19.865 24.48 20.473 25.176 ;
     RECT  20.405 26.208 20.473 28.488 ;
     RECT  20.401 17.232 20.509 17.256 ;
     RECT  20.339 10.176 20.513 11.112 ;
     RECT  20.513 10.176 20.531 11.016 ;
     RECT  20.509 17.232 20.545 17.688 ;
     RECT  20.437 12.528 20.549 13.8 ;
     RECT  20.545 17.232 20.621 17.976 ;
     RECT  20.473 24.48 20.675 28.488 ;
     RECT  20.257 15.312 20.773 16.152 ;
     RECT  20.675 28.368 20.845 28.488 ;
     RECT  19.973 1.728 20.867 1.848 ;
     RECT  20.773 15.312 20.869 16.824 ;
     RECT  20.531 10.176 20.909 10.968 ;
     RECT  20.869 14.784 21.053 16.824 ;
     RECT  20.051 6.816 21.077 6.84 ;
     RECT  20.867 1.728 21.085 1.752 ;
     RECT  20.389 19.008 21.085 21.096 ;
     RECT  21.077 6.816 21.161 7.464 ;
     RECT  21.085 1.104 21.169 1.752 ;
     RECT  20.117 22.8 21.185 22.872 ;
     RECT  21.185 22.8 21.229 23.4 ;
     RECT  20.675 24.48 21.229 27.384 ;
     RECT  21.229 22.8 21.313 27.384 ;
     RECT  19.973 2.832 21.373 4.584 ;
     RECT  21.313 22.8 21.385 23.4 ;
     RECT  20.549 12.528 21.409 12.552 ;
     RECT  21.085 19.008 21.445 21.144 ;
     RECT  21.053 15.216 21.449 16.824 ;
     RECT  21.373 2.832 21.539 4.632 ;
     RECT  21.445 19.008 21.539 22.152 ;
     RECT  21.449 15.456 21.589 16.824 ;
     RECT  20.621 17.952 21.589 17.976 ;
     RECT  20.909 10.848 21.593 10.968 ;
     RECT  21.409 12 21.625 12.552 ;
     RECT  21.313 24.624 21.637 27.384 ;
     RECT  20.845 28.368 21.637 28.44 ;
     RECT  21.589 15.456 21.665 17.976 ;
     RECT  21.539 21.12 21.683 22.152 ;
     RECT  21.653 0.576 21.737 0.6 ;
     RECT  21.539 19.008 21.809 19.992 ;
     RECT  21.683 21.12 21.827 21.672 ;
     RECT  21.169 1.728 21.877 1.752 ;
     RECT  21.637 24.624 21.949 28.44 ;
     RECT  20.405 29.664 21.949 33.672 ;
     RECT  21.665 17.664 21.985 17.976 ;
     RECT  20.225 9.072 22.025 9.096 ;
     RECT  21.665 15.456 22.025 16.536 ;
     RECT  21.593 10.944 22.057 10.968 ;
     RECT  21.625 12 22.057 12.792 ;
     RECT  21.809 19.296 22.211 19.992 ;
     RECT  21.877 1.728 22.261 1.848 ;
     RECT  21.539 2.832 22.261 4.536 ;
     RECT  22.057 10.944 22.313 12.792 ;
     RECT  22.313 12.528 22.421 12.792 ;
     RECT  22.211 19.296 22.421 19.608 ;
     RECT  22.261 1.728 22.453 4.536 ;
     RECT  22.453 1.152 22.457 4.536 ;
     RECT  21.827 21.168 22.565 21.672 ;
     RECT  22.313 10.944 22.601 11.496 ;
     RECT  22.025 15.456 22.633 16.248 ;
     RECT  22.601 10.944 22.643 11.448 ;
     RECT  22.457 1.152 22.673 1.8 ;
     RECT  22.633 14.832 22.745 16.248 ;
     RECT  22.421 12.768 22.777 12.792 ;
     RECT  20.549 13.776 22.777 13.8 ;
     RECT  21.949 24.624 22.789 33.672 ;
     RECT  22.673 1.152 22.813 1.752 ;
     RECT  21.385 23.376 22.837 23.4 ;
     RECT  21.985 17.664 22.961 18.264 ;
     RECT  22.837 22.8 22.981 23.4 ;
     RECT  22.789 24.48 22.981 33.672 ;
     RECT  22.981 22.8 23.027 33.672 ;
     RECT  22.961 18.144 23.093 18.264 ;
     RECT  22.421 19.296 23.093 19.416 ;
     RECT  22.813 1.056 23.281 1.752 ;
     RECT  23.281 0.528 23.315 1.752 ;
     RECT  22.489 9.648 23.317 9.672 ;
     RECT  22.643 10.944 23.317 11.064 ;
     RECT  22.565 21.6 23.453 21.672 ;
     RECT  23.027 22.8 23.453 22.824 ;
     RECT  23.315 0.528 23.459 0.552 ;
     RECT  22.745 14.976 23.653 16.248 ;
     RECT  23.317 9.648 23.713 11.064 ;
     RECT  22.777 12.768 23.785 13.8 ;
     RECT  23.653 14.976 23.785 16.536 ;
     RECT  23.315 1.632 23.929 1.752 ;
     RECT  22.457 2.832 23.929 4.536 ;
     RECT  23.929 1.632 24.008 4.536 ;
     RECT  21.161 6.816 24.008 6.84 ;
     RECT  23.713 9.648 24.008 11.256 ;
     RECT  23.785 12.768 24.008 16.536 ;
     RECT  23.093 18.144 24.008 19.416 ;
     RECT  23.453 21.6 24.008 22.824 ;
     RECT  23.027 23.808 24.008 33.672 ;
     RECT  24.008 1.632 24.109 33.672 ;
     RECT  24.109 1.632 24.304 33.72 ;
     RECT  24.304 1.632 24.325 5.016 ;
     RECT  24.304 23.328 24.325 33.72 ;
     RECT  24.325 23.328 24.467 33.816 ;
     RECT  24.304 12 24.473 17.112 ;
     RECT  24.304 10.368 24.515 10.968 ;
     RECT  24.304 18.672 24.515 20.088 ;
     RECT  24.304 21.648 24.515 22.344 ;
     RECT  24.325 1.152 24.524 5.016 ;
     RECT  24.473 12.096 24.553 17.112 ;
     RECT  24.524 1.104 24.563 5.016 ;
     RECT  24.563 1.104 24.577 1.8 ;
     RECT  24.553 12.528 24.581 17.112 ;
     RECT  24.467 23.328 24.652 33.768 ;
     RECT  24.515 21.648 24.653 22.2 ;
     RECT  24.577 1.008 24.755 1.8 ;
     RECT  24.515 18.672 24.803 18.744 ;
     RECT  24.652 33.648 24.833 33.768 ;
     RECT  24.803 18.72 24.905 18.744 ;
     RECT  24.581 12.576 25.085 17.112 ;
     RECT  24.652 23.328 25.085 32.376 ;
     RECT  24.563 2.832 25.139 4.632 ;
     RECT  25.117 0.576 25.201 0.6 ;
     RECT  25.139 2.832 25.201 2.856 ;
     RECT  25.085 12.576 25.229 14.904 ;
     RECT  24.653 22.176 25.445 22.2 ;
     RECT  24.515 20.016 25.477 20.088 ;
     RECT  24.755 1.728 25.489 1.8 ;
     RECT  24.304 6.816 25.513 6.84 ;
     RECT  25.229 12.576 25.553 14.856 ;
     RECT  25.085 16.032 25.553 17.112 ;
     RECT  25.139 3.888 25.619 4.632 ;
     RECT  25.513 6.816 25.625 6.888 ;
     RECT  25.553 12.576 25.667 14.808 ;
     RECT  25.085 23.328 25.667 31.944 ;
     RECT  24.833 33.648 25.693 33.672 ;
     RECT  25.667 12.576 25.697 14.232 ;
     RECT  25.477 20.016 25.861 20.76 ;
     RECT  25.697 13.296 25.877 14.232 ;
     RECT  25.861 19.872 25.909 20.76 ;
     RECT  25.619 3.888 26.197 4.584 ;
     RECT  25.667 23.328 26.197 26.232 ;
     RECT  26.197 3.408 26.209 4.584 ;
     RECT  26.197 22.56 26.237 26.232 ;
     RECT  25.909 19.872 26.243 21.384 ;
     RECT  26.243 19.872 26.492 21.096 ;
     RECT  26.209 3.408 26.569 3.432 ;
     RECT  25.667 27.312 26.581 31.944 ;
     RECT  25.693 32.976 26.581 33.672 ;
     RECT  26.237 22.56 26.597 25.128 ;
     RECT  25.489 1.728 26.626 1.752 ;
     RECT  26.237 26.112 26.677 26.232 ;
     RECT  26.581 27.312 26.677 33.672 ;
     RECT  25.553 16.032 26.821 16.536 ;
     RECT  26.053 17.616 26.845 17.64 ;
     RECT  26.821 15.936 26.957 16.536 ;
     RECT  26.597 23.904 26.993 25.128 ;
     RECT  26.626 1.728 27.097 1.8 ;
     RECT  26.953 2.832 27.097 2.856 ;
     RECT  26.989 14.832 27.164 14.856 ;
     RECT  26.677 26.112 27.173 33.672 ;
     RECT  26.845 17.616 27.205 17.832 ;
     RECT  26.597 22.56 27.209 22.584 ;
     RECT  27.205 17.616 27.245 17.976 ;
     RECT  27.164 14.832 27.251 15.144 ;
     RECT  27.251 14.832 27.317 14.856 ;
     RECT  27.173 28.944 27.317 31.416 ;
     RECT  27.097 1.728 27.347 2.856 ;
     RECT  25.877 13.296 27.385 13.656 ;
     RECT  26.993 24.912 27.397 25.128 ;
     RECT  27.173 26.112 27.397 27.912 ;
     RECT  24.515 10.368 27.421 10.392 ;
     RECT  26.993 23.904 27.425 23.928 ;
     RECT  27.245 17.808 27.457 17.976 ;
     RECT  26.492 19.344 27.457 21.096 ;
     RECT  27.385 5.664 27.469 5.688 ;
     RECT  26.209 4.56 27.491 4.584 ;
     RECT  27.421 10.368 27.533 10.824 ;
     RECT  27.397 24.912 27.533 27.912 ;
     RECT  27.173 32.4 27.677 33.672 ;
     RECT  27.457 17.808 27.713 21.096 ;
     RECT  27.533 26.208 27.724 27.912 ;
     RECT  27.533 10.608 27.745 10.824 ;
     RECT  27.677 32.4 27.82 32.52 ;
     RECT  27.677 33.648 27.829 33.672 ;
     RECT  27.745 10.608 27.925 10.92 ;
     RECT  27.845 4.992 27.929 5.016 ;
     RECT  27.385 13.296 27.997 14.664 ;
     RECT  27.953 21.648 28.037 21.768 ;
     RECT  28.037 21.744 28.163 21.768 ;
     RECT  27.317 28.992 28.165 31.416 ;
     RECT  27.347 2.832 28.213 2.856 ;
     RECT  27.533 24.912 28.213 24.936 ;
     RECT  28.213 2.832 28.297 3.432 ;
     RECT  27.347 1.728 28.309 1.8 ;
     RECT  28.297 2.832 28.309 2.856 ;
     RECT  27.724 27.312 28.309 27.912 ;
     RECT  27.713 17.808 28.46 20.424 ;
     RECT  27.997 12.528 28.501 14.664 ;
     RECT  26.957 16.176 28.501 16.536 ;
     RECT  28.309 27.312 28.501 28.008 ;
     RECT  28.165 28.992 28.501 31.992 ;
     RECT  28.213 23.952 28.573 24.936 ;
     RECT  27.724 26.208 28.573 26.28 ;
     RECT  27.637 22.8 28.604 22.824 ;
     RECT  28.573 23.952 28.604 26.28 ;
     RECT  28.573 3.84 28.709 3.96 ;
     RECT  28.604 22.8 28.741 26.28 ;
     RECT  27.829 33.648 28.741 33.72 ;
     RECT  28.741 33.648 28.825 33.768 ;
     RECT  28.741 22.656 28.981 26.28 ;
     RECT  28.501 27.312 28.981 31.992 ;
     RECT  28.981 22.656 28.997 31.992 ;
     RECT  28.825 33.072 28.997 33.768 ;
     RECT  27.925 10.608 29.036 11.4 ;
     RECT  28.501 12.528 29.036 16.536 ;
     RECT  28.709 3.84 29.077 4.008 ;
     RECT  28.309 1.728 29.081 2.856 ;
     RECT  29.077 0.384 29.125 0.408 ;
     RECT  29.081 1.824 29.408 2.856 ;
     RECT  29.077 3.84 29.408 4.68 ;
     RECT  25.625 6.816 29.408 6.84 ;
     RECT  29.036 10.608 29.408 16.536 ;
     RECT  28.46 17.568 29.408 20.424 ;
     RECT  28.997 22.656 29.408 33.768 ;
     RECT  29.408 1.824 29.605 33.768 ;
     RECT  29.605 1.824 29.704 33.816 ;
     RECT  29.125 0.288 29.717 0.408 ;
     RECT  29.704 18.48 29.765 20.472 ;
     RECT  29.704 9.84 29.837 11.256 ;
     RECT  29.717 0.24 29.843 0.408 ;
     RECT  29.704 15.84 29.843 16.392 ;
     RECT  29.843 0.24 29.893 0.312 ;
     RECT  29.704 22.608 29.939 23.976 ;
     RECT  29.893 0.192 29.98 0.312 ;
     RECT  29.704 26.496 30.035 33.816 ;
     RECT  29.704 3.936 30.089 4.68 ;
     RECT  29.704 13.056 30.197 13.32 ;
     RECT  29.704 1.824 30.275 2.76 ;
     RECT  29.939 22.608 30.275 23.88 ;
     RECT  30.035 26.736 30.275 33.816 ;
     RECT  30.275 1.824 30.293 1.848 ;
     RECT  30.275 22.608 30.563 22.632 ;
     RECT  29.837 9.84 30.593 10.968 ;
     RECT  30.275 26.736 30.611 28.584 ;
     RECT  29.765 18.48 30.629 19.032 ;
     RECT  29.704 8.832 30.659 8.856 ;
     RECT  29.704 5.712 30.689 7.8 ;
     RECT  30.611 26.736 30.709 27.912 ;
     RECT  30.275 29.616 30.737 33.816 ;
     RECT  30.689 5.664 30.755 7.8 ;
     RECT  30.737 33.648 30.757 33.816 ;
     RECT  30.755 5.664 30.773 7.416 ;
     RECT  29.765 20.304 30.773 20.472 ;
     RECT  30.275 23.856 30.773 23.88 ;
     RECT  30.737 29.616 30.773 32.376 ;
     RECT  29.704 14.4 30.812 14.856 ;
     RECT  30.773 20.448 30.881 20.472 ;
     RECT  29.98 0.288 30.899 0.312 ;
     RECT  30.629 18.768 30.985 19.032 ;
     RECT  30.773 29.616 30.995 32.088 ;
     RECT  30.757 33.648 30.995 34.296 ;
     RECT  30.593 10.608 31.057 10.968 ;
     RECT  31.057 10.608 31.229 11.544 ;
     RECT  31.052 2.88 31.237 2.904 ;
     RECT  30.089 3.936 31.237 4.632 ;
     RECT  30.812 14.4 31.301 15.048 ;
     RECT  29.843 16.032 31.301 16.392 ;
     RECT  31.229 10.608 31.313 12.024 ;
     RECT  31.237 2.88 31.34 4.632 ;
     RECT  30.773 6.192 31.421 7.416 ;
     RECT  31.381 24.528 31.529 24.552 ;
     RECT  30.985 18.768 31.601 19.128 ;
     RECT  30.293 1.728 31.669 1.848 ;
     RECT  31.34 2.88 31.669 5.112 ;
     RECT  30.995 33.648 31.673 33.768 ;
     RECT  31.421 6.192 31.715 6.936 ;
     RECT  31.669 1.728 31.753 5.112 ;
     RECT  31.621 29.376 31.765 29.4 ;
     RECT  31.673 33.648 31.841 33.672 ;
     RECT  30.197 13.056 31.909 13.08 ;
     RECT  31.301 14.4 31.909 16.392 ;
     RECT  30.995 30.768 31.909 32.088 ;
     RECT  31.841 33.072 31.909 33.672 ;
     RECT  31.753 3.936 31.925 5.112 ;
     RECT  31.877 0.192 31.961 0.216 ;
     RECT  30.709 26.784 31.993 27.912 ;
     RECT  31.765 29.04 32.029 29.4 ;
     RECT  31.909 30.768 32.029 33.672 ;
     RECT  30.985 8.4 32.053 8.52 ;
     RECT  31.993 26.736 32.076 27.912 ;
     RECT  31.753 1.728 32.099 2.904 ;
     RECT  31.715 6.192 32.099 6.888 ;
     RECT  32.053 8.4 32.101 8.904 ;
     RECT  32.099 6.192 32.137 6.312 ;
     RECT  32.101 7.968 32.173 8.904 ;
     RECT  32.076 26.688 32.177 27.912 ;
     RECT  31.601 19.104 32.217 19.128 ;
     RECT  32.217 19.104 32.291 19.368 ;
     RECT  31.921 23.376 32.291 23.4 ;
     RECT  32.173 7.968 32.339 9 ;
     RECT  32.245 18 32.393 18.024 ;
     RECT  32.029 29.04 32.465 33.672 ;
     RECT  31.313 10.608 32.483 11.736 ;
     RECT  31.909 13.056 32.501 16.392 ;
     RECT  32.177 27.216 32.597 27.912 ;
     RECT  32.465 29.04 32.597 32.472 ;
     RECT  32.099 2.832 32.773 2.904 ;
     RECT  31.925 3.936 32.773 4.008 ;
     RECT  32.483 10.848 32.773 11.736 ;
     RECT  32.501 13.056 32.773 14.808 ;
     RECT  32.137 5.136 32.797 6.312 ;
     RECT  32.797 5.616 32.861 6.312 ;
     RECT  32.339 7.968 32.885 8.904 ;
     RECT  32.773 2.832 32.893 4.008 ;
     RECT  32.099 1.728 33.013 1.752 ;
     RECT  32.773 10.848 33.059 14.808 ;
     RECT  32.861 5.76 33.181 6.312 ;
     RECT  32.885 7.392 33.181 8.904 ;
     RECT  33.059 10.848 33.185 11.736 ;
     RECT  33.181 5.76 33.299 8.904 ;
     RECT  32.597 27.216 33.308 32.472 ;
     RECT  33.013 1.056 33.325 1.752 ;
     RECT  33.185 10.848 33.347 11.544 ;
     RECT  33.299 7.392 33.389 8.904 ;
     RECT  33.308 26.88 33.395 32.472 ;
     RECT  33.325 1.056 33.409 1.848 ;
     RECT  33.389 7.392 33.493 9.144 ;
     RECT  33.299 5.76 33.625 6.264 ;
     RECT  32.501 16.032 33.649 16.392 ;
     RECT  33.409 1.056 33.653 1.8 ;
     RECT  32.291 19.344 33.781 19.368 ;
     RECT  33.395 27.216 33.781 32.472 ;
     RECT  32.465 33.648 33.781 33.672 ;
     RECT  33.493 7.392 33.925 9.432 ;
     RECT  33.347 10.848 33.925 11.496 ;
     RECT  32.893 2.832 34.081 4.584 ;
     RECT  33.733 0.528 34.117 0.552 ;
     RECT  34.117 0.48 34.229 0.552 ;
     RECT  33.781 17.616 34.297 18.216 ;
     RECT  33.781 19.344 34.297 20.136 ;
     RECT  33.925 7.392 34.369 11.496 ;
     RECT  34.369 6.864 34.453 11.496 ;
     RECT  34.229 0.48 34.477 0.504 ;
     RECT  34.081 2.832 34.501 4.68 ;
     RECT  33.625 5.76 34.645 5.784 ;
     RECT  34.453 6.864 34.645 11.976 ;
     RECT  34.477 0.192 34.657 0.504 ;
     RECT  34.657 0.144 34.805 0.504 ;
     RECT  33.653 1.728 34.808 1.8 ;
     RECT  34.501 2.784 34.808 4.68 ;
     RECT  34.645 5.76 34.808 11.976 ;
     RECT  33.059 13.104 34.808 14.808 ;
     RECT  33.649 16.032 34.808 16.536 ;
     RECT  34.297 17.616 34.808 20.136 ;
     RECT  33.781 27.216 34.808 33.672 ;
     RECT  34.805 0.24 35.093 0.504 ;
     RECT  34.808 1.728 35.104 33.672 ;
     RECT  35.104 13.536 35.165 14.424 ;
     RECT  35.104 19.248 35.201 19.368 ;
     RECT  35.093 0.288 35.219 0.504 ;
     RECT  35.104 12 35.245 12.552 ;
     RECT  35.104 3.36 35.267 9.816 ;
     RECT  35.104 10.848 35.267 10.872 ;
     RECT  35.165 13.536 35.267 14.136 ;
     RECT  35.104 1.728 35.269 1.752 ;
     RECT  35.269 1.68 35.324 1.752 ;
     RECT  35.104 26.736 35.345 33.672 ;
     RECT  35.267 3.36 35.353 6.936 ;
     RECT  35.267 7.968 35.363 9.816 ;
     RECT  35.201 19.248 35.363 19.272 ;
     RECT  35.345 32.448 35.365 33.672 ;
     RECT  35.345 26.736 35.381 31.464 ;
     RECT  35.324 0.528 35.411 1.752 ;
     RECT  35.365 32.448 35.507 33.768 ;
     RECT  35.411 1.68 35.525 1.752 ;
     RECT  35.104 16.032 35.525 18.264 ;
     RECT  35.525 16.032 35.553 17.496 ;
     RECT  35.245 12.528 35.651 12.552 ;
     RECT  35.363 8.448 35.669 9.816 ;
     RECT  35.507 32.448 35.813 33.672 ;
     RECT  35.669 9.072 35.849 9.816 ;
     RECT  35.411 0.528 35.987 0.552 ;
     RECT  35.381 26.736 36.179 31.368 ;
     RECT  35.353 3.36 36.181 4.632 ;
     RECT  35.525 1.728 36.28 1.752 ;
     RECT  35.353 5.712 36.317 6.936 ;
     RECT  36.181 2.976 36.325 4.632 ;
     RECT  36.325 2.88 36.371 4.632 ;
     RECT  36.179 30.768 36.373 31.368 ;
     RECT  35.553 16.032 36.389 17.112 ;
     RECT  36.371 2.88 36.412 4.584 ;
     RECT  36.179 26.736 36.419 29.688 ;
     RECT  36.317 6.912 36.493 6.936 ;
     RECT  35.849 9.696 36.493 9.816 ;
     RECT  36.493 9.696 36.497 10.344 ;
     RECT  35.813 32.976 36.517 33.672 ;
     RECT  36.419 26.736 36.524 29.64 ;
     RECT  36.524 26.64 36.611 29.64 ;
     RECT  36.317 5.712 36.637 5.928 ;
     RECT  36.493 6.912 36.707 7.656 ;
     RECT  36.497 10.272 36.737 10.344 ;
     RECT  36.517 32.976 36.755 33.768 ;
     RECT  36.755 33.648 36.785 33.768 ;
     RECT  36.737 10.272 36.853 10.392 ;
     RECT  36.745 7.968 36.899 8.568 ;
     RECT  36.853 10.272 36.947 10.872 ;
     RECT  36.853 13.104 37.001 13.128 ;
     RECT  36.785 33.648 37.037 33.72 ;
     RECT  36.947 10.32 37.043 10.872 ;
     RECT  36.28 1.728 37.237 1.8 ;
     RECT  36.707 6.912 37.253 6.936 ;
     RECT  36.469 25.632 37.276 25.656 ;
     RECT  37.237 1.728 37.325 1.848 ;
     RECT  36.637 5.664 37.421 5.928 ;
     RECT  36.611 27.36 37.429 29.64 ;
     RECT  36.899 7.968 37.657 7.992 ;
     RECT  36.373 30.768 37.789 31.944 ;
     RECT  37.789 30.768 37.813 32.472 ;
     RECT  36.412 3.36 37.933 4.584 ;
     RECT  37.421 5.664 37.933 6.264 ;
     RECT  37.933 3.36 38.005 6.264 ;
     RECT  37.033 12.192 38.005 12.552 ;
     RECT  37.813 30.672 38.099 32.472 ;
     RECT  38.005 12.192 38.113 13.08 ;
     RECT  37.325 1.728 38.147 1.8 ;
     RECT  38.005 2.928 38.153 6.264 ;
     RECT  38.113 11.952 38.153 13.08 ;
     RECT  38.153 3.744 38.257 6.264 ;
     RECT  37.765 7.344 38.257 7.416 ;
     RECT  38.257 3.744 38.333 7.416 ;
     RECT  37.037 33.648 38.365 33.672 ;
     RECT  38.149 0.192 38.435 0.216 ;
     RECT  38.341 9.12 38.437 9.144 ;
     RECT  37.043 10.32 38.437 10.344 ;
     RECT  37.429 27.36 38.437 29.688 ;
     RECT  38.437 9.12 38.473 10.344 ;
     RECT  38.153 11.952 38.485 12.072 ;
     RECT  35.267 14.112 38.531 14.136 ;
     RECT  38.437 27.264 38.617 29.688 ;
     RECT  38.099 30.672 38.617 32.04 ;
     RECT  38.153 13.056 38.653 13.08 ;
     RECT  38.473 9.12 38.657 10.488 ;
     RECT  38.657 9.12 38.684 9.144 ;
     RECT  38.657 10.32 38.693 10.488 ;
     RECT  36.389 16.032 38.693 16.2 ;
     RECT  35.104 20.64 38.761 20.664 ;
     RECT  38.684 8.496 38.771 9.144 ;
     RECT  38.761 20.64 38.797 20.712 ;
     RECT  38.653 13.056 38.801 13.128 ;
     RECT  38.365 33.072 38.821 33.672 ;
     RECT  38.797 0.576 38.881 0.6 ;
     RECT  38.821 33.072 38.908 33.768 ;
     RECT  38.869 14.832 38.981 14.856 ;
     RECT  38.485 11.664 39.013 12.072 ;
     RECT  38.797 20.592 39.017 20.712 ;
     RECT  39.017 20.592 39.053 20.664 ;
     RECT  38.617 27.264 39.061 32.04 ;
     RECT  39.013 11.424 39.221 12.072 ;
     RECT  38.333 3.744 39.265 4.008 ;
     RECT  38.147 1.728 39.373 1.752 ;
     RECT  39.061 26.976 39.397 32.04 ;
     RECT  38.771 9.12 39.685 9.144 ;
     RECT  38.693 10.32 39.685 10.344 ;
     RECT  39.397 26.784 39.685 32.04 ;
     RECT  38.908 33.072 39.701 33.672 ;
     RECT  39.373 1.728 39.733 1.848 ;
     RECT  39.265 2.832 39.733 4.008 ;
     RECT  38.333 5.184 39.733 7.416 ;
     RECT  39.685 9.12 39.733 10.344 ;
     RECT  39.221 11.424 39.733 12.552 ;
     RECT  39.733 5.184 39.781 7.464 ;
     RECT  39.733 9.12 39.781 12.552 ;
     RECT  39.733 1.728 39.805 4.008 ;
     RECT  39.781 5.184 39.805 12.552 ;
     RECT  39.685 26.448 39.973 32.04 ;
     RECT  39.701 33.072 39.973 33.144 ;
     RECT  39.973 26.256 40.021 32.04 ;
     RECT  39.973 33.024 40.021 33.144 ;
     RECT  38.693 16.176 40.057 16.2 ;
     RECT  39.805 1.728 40.208 12.552 ;
     RECT  40.057 16.08 40.208 16.2 ;
     RECT  39.053 20.64 40.208 20.664 ;
     RECT  40.021 26.256 40.208 33.144 ;
     RECT  40.021 0.288 40.451 0.312 ;
     RECT  40.208 1.728 40.504 33.144 ;
     RECT  40.504 15.984 40.643 16.104 ;
     RECT  40.504 2.784 40.691 4.008 ;
     RECT  40.504 5.232 40.691 8.04 ;
     RECT  40.504 1.728 40.739 1.8 ;
     RECT  40.691 5.712 40.739 8.04 ;
     RECT  40.504 10.8 40.931 12.552 ;
     RECT  40.739 7.392 41.075 8.04 ;
     RECT  40.931 11.664 41.267 12.552 ;
     RECT  40.504 26.256 41.269 33.144 ;
     RECT  40.504 20.64 41.459 20.664 ;
     RECT  40.691 2.88 41.489 4.008 ;
     RECT  40.504 18.72 41.5 19.56 ;
     RECT  41.489 2.88 41.573 4.584 ;
     RECT  41.573 2.88 41.596 4.536 ;
     RECT  41.497 0.144 41.717 0.168 ;
     RECT  41.269 26.256 41.725 33.672 ;
     RECT  41.075 7.968 41.785 8.04 ;
     RECT  40.504 9.264 41.785 9.384 ;
     RECT  40.739 5.712 41.891 6.264 ;
     RECT  41.785 7.968 41.893 9.384 ;
     RECT  40.739 1.728 41.896 1.752 ;
     RECT  41.896 1.728 41.965 1.8 ;
     RECT  41.891 5.808 41.996 6.264 ;
     RECT  41.725 26.256 42.037 29.16 ;
     RECT  41.596 3.36 42.077 4.536 ;
     RECT  41.713 23.568 42.109 23.592 ;
     RECT  41.725 30.192 42.109 33.672 ;
     RECT  42.077 3.408 42.121 4.536 ;
     RECT  41.996 5.808 42.149 6.312 ;
     RECT  42.037 26.208 42.185 29.16 ;
     RECT  41.893 7.968 42.293 10.488 ;
     RECT  42.109 30.192 42.508 33.72 ;
     RECT  42.508 30.192 42.689 32.52 ;
     RECT  42.508 33.648 42.707 33.72 ;
     RECT  42.149 5.904 42.721 6.312 ;
     RECT  42.293 7.968 42.721 9.912 ;
     RECT  42.721 5.904 42.755 9.912 ;
     RECT  42.613 0.528 42.869 0.552 ;
     RECT  41.267 11.664 42.893 11.976 ;
     RECT  41.965 1.728 43.045 2.28 ;
     RECT  42.121 3.408 43.045 4.008 ;
     RECT  42.893 11.664 43.189 12.024 ;
     RECT  42.109 22.608 43.229 23.592 ;
     RECT  43.045 1.728 43.237 4.008 ;
     RECT  43.189 11.664 43.283 12.552 ;
     RECT  42.185 26.4 43.333 29.16 ;
     RECT  42.689 30.192 43.333 31.944 ;
     RECT  43.333 26.4 43.369 31.944 ;
     RECT  43.229 22.704 43.373 23.592 ;
     RECT  43.369 26.304 43.523 31.944 ;
     RECT  42.707 33.648 43.621 33.672 ;
     RECT  43.237 1.728 43.649 4.536 ;
     RECT  43.593 19.92 43.657 19.944 ;
     RECT  41.5 18.72 43.667 18.744 ;
     RECT  43.649 1.728 43.693 4.584 ;
     RECT  42.755 5.904 43.693 9.528 ;
     RECT  43.523 26.736 43.693 31.944 ;
     RECT  43.621 33.072 43.693 33.672 ;
     RECT  43.693 1.728 43.907 9.528 ;
     RECT  43.693 26.736 43.907 33.672 ;
     RECT  43.907 2.832 44.156 9.528 ;
     RECT  44.156 2.832 44.243 10.056 ;
     RECT  43.907 30.576 44.339 33.672 ;
     RECT  44.339 33.072 44.345 33.672 ;
     RECT  44.053 18.912 44.417 18.936 ;
     RECT  44.243 2.832 44.435 9.432 ;
     RECT  43.907 1.728 44.437 1.848 ;
     RECT  44.435 2.832 44.453 9.336 ;
     RECT  44.345 33.648 44.53 33.672 ;
     RECT  43.283 11.664 44.557 11.736 ;
     RECT  44.557 11.232 44.629 11.736 ;
     RECT  44.629 11.232 44.773 12.024 ;
     RECT  43.373 22.752 44.845 23.592 ;
     RECT  44.773 11.232 44.914 12.552 ;
     RECT  43.907 26.736 44.953 29.4 ;
     RECT  44.339 30.576 44.953 31.992 ;
     RECT  44.437 0.624 44.981 0.648 ;
     RECT  44.981 0.576 45.065 0.648 ;
     RECT  44.953 26.736 45.301 31.992 ;
     RECT  44.845 22.224 45.356 23.592 ;
     RECT  40.643 15.984 45.445 16.008 ;
     RECT  44.437 1.68 45.457 1.848 ;
     RECT  45.301 26.736 45.589 32.04 ;
     RECT  45.457 1.104 45.608 1.848 ;
     RECT  44.453 2.832 45.608 9.288 ;
     RECT  44.914 11.232 45.608 12.6 ;
     RECT  45.133 14.832 45.608 14.856 ;
     RECT  45.445 15.984 45.608 16.104 ;
     RECT  43.333 17.184 45.608 17.208 ;
     RECT  45.097 18.192 45.608 18.216 ;
     RECT  43.657 19.92 45.608 20.328 ;
     RECT  45.356 21.648 45.608 23.592 ;
     RECT  45.589 26.736 45.608 32.568 ;
     RECT  45.608 1.104 45.904 32.568 ;
     RECT  45.904 1.104 46.019 13.08 ;
     RECT  44.53 33.648 46.021 33.72 ;
     RECT  45.904 26.592 46.037 32.568 ;
     RECT  45.904 17.184 46.045 18.84 ;
     RECT  46.019 1.104 46.067 4.152 ;
     RECT  46.019 5.568 46.073 13.08 ;
     RECT  45.904 14.832 46.115 14.856 ;
     RECT  46.037 30.24 46.133 32.568 ;
     RECT  46.021 33.648 46.133 33.768 ;
     RECT  46.133 30.24 46.145 33.768 ;
     RECT  46.073 5.568 46.181 7.944 ;
     RECT  45.904 22.224 46.181 23.592 ;
     RECT  46.067 1.104 46.217 4.008 ;
     RECT  46.145 30.24 46.217 33.72 ;
     RECT  46.217 1.104 46.289 1.8 ;
     RECT  46.045 17.184 46.451 18.456 ;
     RECT  46.037 26.592 46.657 29.112 ;
     RECT  46.217 33.072 46.739 33.72 ;
     RECT  46.68 0.288 46.801 0.312 ;
     RECT  46.217 2.832 46.829 4.008 ;
     RECT  46.073 9.072 46.865 13.08 ;
     RECT  46.451 17.616 46.901 18.456 ;
     RECT  46.181 22.224 46.901 23.352 ;
     RECT  46.865 9.072 46.979 11.352 ;
     RECT  46.979 9.264 47.045 11.352 ;
     RECT  47.005 24.528 47.089 24.552 ;
     RECT  46.657 26.688 47.125 29.112 ;
     RECT  46.217 30.24 47.125 32.04 ;
     RECT  46.289 1.728 47.221 1.8 ;
     RECT  46.829 3.408 47.257 4.008 ;
     RECT  45.904 20.064 47.261 20.952 ;
     RECT  47.045 10.272 47.267 11.352 ;
     RECT  47.221 1.728 47.333 2.28 ;
     RECT  46.865 12.528 47.341 13.08 ;
     RECT  46.901 22.752 47.365 23.352 ;
     RECT  47.261 20.064 47.369 20.616 ;
     RECT  46.739 33.072 47.404 33.672 ;
     RECT  47.404 33.072 47.461 33.096 ;
     RECT  47.125 26.688 47.651 32.04 ;
     RECT  47.257 3.408 47.797 4.584 ;
     RECT  46.181 5.712 47.833 7.944 ;
     RECT  47.651 26.784 47.873 32.04 ;
     RECT  47.797 3.216 47.881 4.68 ;
     RECT  47.881 3.216 47.884 4.056 ;
     RECT  46.901 17.616 47.981 17.64 ;
     RECT  47.401 18.816 47.981 18.84 ;
     RECT  47.045 9.264 48.085 9.288 ;
     RECT  47.267 10.272 48.085 11.304 ;
     RECT  47.365 22.752 48.085 23.688 ;
     RECT  48.085 9.264 48.265 11.304 ;
     RECT  47.884 3.408 48.266 4.056 ;
     RECT  47.873 27.312 48.448 32.04 ;
     RECT  47.461 33.024 48.448 33.096 ;
     RECT  48.266 3.408 48.485 4.008 ;
     RECT  47.333 1.728 48.625 1.848 ;
     RECT  47.341 13.056 48.625 13.08 ;
     RECT  47.369 20.304 48.665 20.616 ;
     RECT  47.833 5.712 48.773 7.992 ;
     RECT  48.265 9.264 48.805 11.448 ;
     RECT  48.625 13.056 48.841 13.656 ;
     RECT  48.448 27.312 48.901 33.096 ;
     RECT  48.625 21.648 48.956 21.672 ;
     RECT  48.085 22.752 48.956 23.832 ;
     RECT  48.665 20.304 48.985 20.328 ;
     RECT  48.805 8.976 48.989 11.448 ;
     RECT  48.989 11.424 48.995 11.448 ;
     RECT  48.901 26.736 49.021 33.096 ;
     RECT  49.021 26.736 49.025 33.144 ;
     RECT  48.956 21.648 49.043 23.832 ;
     RECT  49.025 28.464 49.045 33.144 ;
     RECT  48.485 3.408 49.091 3.96 ;
     RECT  48.989 8.976 49.091 10.248 ;
     RECT  49.045 28.464 49.091 33.672 ;
     RECT  48.841 12.528 49.097 13.656 ;
     RECT  48.997 18.816 49.187 18.84 ;
     RECT  49.025 26.736 49.187 27.384 ;
     RECT  48.625 1.728 49.237 1.896 ;
     RECT  48.985 19.92 49.237 20.328 ;
     RECT  49.043 23.28 49.313 23.304 ;
     RECT  49.043 21.648 49.345 22.2 ;
     RECT  49.237 1.728 49.379 2.28 ;
     RECT  49.091 30.576 49.619 33.672 ;
     RECT  49.165 24.336 49.621 24.36 ;
     RECT  48.913 25.44 49.621 25.464 ;
     RECT  49.619 30.768 49.621 33.672 ;
     RECT  49.589 3.984 49.673 4.584 ;
     RECT  49.621 24.336 49.745 25.464 ;
     RECT  49.745 24.336 49.781 25.08 ;
     RECT  49.345 21.6 49.997 22.2 ;
     RECT  49.621 30.768 50.003 33.72 ;
     RECT  49.091 9.264 50.033 10.248 ;
     RECT  49.091 28.464 50.041 29.304 ;
     RECT  50.003 33.648 50.099 33.72 ;
     RECT  47.401 0.576 50.101 0.6 ;
     RECT  49.187 27.072 50.149 27.384 ;
     RECT  49.997 21.6 50.173 21.672 ;
     RECT  50.101 0.144 50.213 0.6 ;
     RECT  50.213 0.576 50.257 0.6 ;
     RECT  50.149 26.784 50.293 27.384 ;
     RECT  50.041 28.464 50.293 28.584 ;
     RECT  50.281 10.848 50.569 10.872 ;
     RECT  50.099 33.648 50.579 33.672 ;
     RECT  49.379 1.728 50.629 1.848 ;
     RECT  50.629 1.728 50.677 2.712 ;
     RECT  49.673 3.984 50.677 4.008 ;
     RECT  50.677 1.728 50.681 4.008 ;
     RECT  49.237 19.344 50.725 20.328 ;
     RECT  50.173 21.408 50.725 21.672 ;
     RECT  50.725 18.96 50.773 21.672 ;
     RECT  50.681 2.148 51.008 4.008 ;
     RECT  48.773 5.712 51.008 7.608 ;
     RECT  50.033 9.264 51.008 9.288 ;
     RECT  50.569 10.848 51.008 11.448 ;
     RECT  49.097 12.528 51.008 12.552 ;
     RECT  49.097 13.632 51.008 13.656 ;
     RECT  45.904 16.08 51.008 16.104 ;
     RECT  50.773 18.768 51.008 21.672 ;
     RECT  50.137 22.752 51.008 22.872 ;
     RECT  49.781 24.336 51.008 24.36 ;
     RECT  50.293 26.784 51.008 28.584 ;
     RECT  50.129 29.616 51.008 29.784 ;
     RECT  50.003 30.768 51.008 32.136 ;
     RECT  51.008 2.148 51.112 32.412 ;
     RECT  51.112 2.418 51.304 32.142 ;
     RECT  51.304 9.264 51.443 9.288 ;
     RECT  51.304 31.488 51.443 31.512 ;
     RECT  51.304 13.632 51.827 13.656 ;
     RECT  51.304 15.984 52.157 16.44 ;
     RECT  52.157 16.416 52.163 16.44 ;
     RECT  51.304 20.304 52.163 20.328 ;
     RECT  53.045 1.728 53.129 1.752 ;
     RECT  51.304 6.288 53.201 6.312 ;
     RECT  51.304 18.432 56.408 18.792 ;
     RECT  51.304 21.408 56.408 21.432 ;
     RECT  56.408 2.148 56.512 32.412 ;
     RECT  56.512 2.418 56.704 32.142 ;
     RECT  56.704 21.408 61.649 21.432 ;
     RECT  61.669 14.928 61.808 14.952 ;
     RECT  56.704 18.432 61.808 18.792 ;
     RECT  61.649 21.12 61.808 21.432 ;
     RECT  61.808 2.148 61.912 32.412 ;
     RECT  61.912 2.418 62.104 32.142 ;
     RECT  62.104 21.408 63.781 21.432 ;
     RECT  63.781 21.408 63.827 21.912 ;
     RECT  63.827 21.888 65.693 21.912 ;
     RECT  62.104 18.768 66.337 18.792 ;
     RECT  62.104 14.928 66.517 14.952 ;
     RECT  66.133 17.472 66.553 17.496 ;
     RECT  66.337 18.768 66.553 19.224 ;
     RECT  66.553 17.472 67.093 19.224 ;
     RECT  66.085 21.936 67.165 21.96 ;
     RECT  66.517 14.64 67.208 14.952 ;
     RECT  67.093 17.088 67.208 19.224 ;
     RECT  67.165 21.12 67.208 21.96 ;
     RECT  67.208 2.148 67.312 32.412 ;
     RECT  67.312 2.418 67.504 32.142 ;
     RECT  67.504 14.64 67.601 14.952 ;
     RECT  67.601 14.64 67.853 14.808 ;
     RECT  67.504 17.088 67.853 19.08 ;
     RECT  67.853 17.616 67.997 19.08 ;
     RECT  67.504 21.12 68.177 21.336 ;
     RECT  67.997 17.616 69.001 18.792 ;
     RECT  67.853 14.784 69.041 14.808 ;
     RECT  69.001 17.568 69.077 18.792 ;
     RECT  68.177 21.312 69.221 21.336 ;
     RECT  69.077 17.568 69.689 18.216 ;
     RECT  69.689 18.192 69.797 18.216 ;
     RECT  70.189 16.512 70.369 16.536 ;
     RECT  70.369 15.552 70.693 16.536 ;
     RECT  70.693 15.264 70.729 16.536 ;
     RECT  70.729 15.264 70.837 17.304 ;
     RECT  70.693 13.248 70.909 13.272 ;
     RECT  70.909 12.672 70.981 13.272 ;
     RECT  70.981 12.672 71.233 13.56 ;
     RECT  70.837 14.976 71.233 17.304 ;
     RECT  70.765 18.864 71.233 18.888 ;
     RECT  71.233 19.872 71.809 19.896 ;
     RECT  71.233 21.312 71.809 21.336 ;
     RECT  71.233 12.672 71.845 18.888 ;
     RECT  71.809 19.872 71.845 21.336 ;
     RECT  71.845 12.672 72.349 21.624 ;
     RECT  72.349 12.672 73.26 21.768 ;
    LAYER M5 ;
     RECT  9.024 0.144 50.664 1.763 ;
     RECT  9.6 1.763 50.664 1.811 ;
     RECT  9.6 1.811 16.392 1.859 ;
     RECT  17.424 1.811 50.664 2.137 ;
     RECT  2.4 2.137 2.52 2.151 ;
     RECT  7.8 2.137 7.92 2.151 ;
     RECT  17.424 2.137 51.12 2.151 ;
     RECT  56.4 2.137 56.52 2.151 ;
     RECT  61.8 2.137 61.92 2.151 ;
     RECT  67.2 2.137 67.32 2.151 ;
     RECT  17.424 2.151 51.312 2.291 ;
     RECT  9.6 1.859 15.816 2.339 ;
     RECT  17.424 2.291 41.736 2.821 ;
     RECT  9.888 2.339 15.816 3.205 ;
     RECT  16.896 2.821 41.736 3.205 ;
     RECT  9.888 3.205 41.736 3.349 ;
     RECT  9.888 3.349 41.976 3.397 ;
     RECT  43.008 2.291 51.312 3.397 ;
     RECT  9.888 3.397 51.312 3.443 ;
     RECT  10.176 3.443 51.312 4.019 ;
     RECT  10.464 4.019 49.656 4.595 ;
     RECT  10.8 4.595 26.52 5.653 ;
     RECT  27.648 4.595 48.984 5.653 ;
     RECT  10.8 5.653 48.984 5.701 ;
     RECT  10.656 5.701 48.984 5.795 ;
     RECT  48.96 5.795 48.984 5.797 ;
     RECT  10.656 5.795 47.736 5.843 ;
     RECT  50.64 4.019 51.312 6.181 ;
     RECT  11.088 5.843 47.736 6.323 ;
     RECT  50.544 6.181 51.312 6.661 ;
     RECT  11.424 6.323 47.736 6.805 ;
     RECT  48.96 5.797 49.032 6.805 ;
     RECT  11.424 6.805 49.032 8.579 ;
     RECT  42.432 8.579 49.032 8.965 ;
     RECT  50.16 6.661 51.312 9.253 ;
     RECT  11.424 8.579 41.256 9.781 ;
     RECT  42.432 8.965 49.08 9.781 ;
     RECT  7.8 2.151 8.112 13.381 ;
     RECT  50.16 9.253 51.432 13.621 ;
     RECT  2.4 2.151 2.712 14.197 ;
     RECT  2.4 14.197 2.904 14.723 ;
     RECT  7.8 13.381 8.616 14.723 ;
     RECT  61.8 2.151 62.112 14.917 ;
     RECT  0.192 14.869 0.216 16.067 ;
     RECT  50.16 13.621 51.816 16.405 ;
     RECT  11.424 9.781 49.08 16.501 ;
     RECT  10.848 16.501 49.08 17.075 ;
     RECT  66.144 17.461 66.168 18.181 ;
     RECT  67.2 2.151 67.512 18.181 ;
     RECT  66.144 18.181 67.512 18.803 ;
     RECT  11.424 17.075 49.08 18.805 ;
     RECT  66.672 18.803 67.512 19.235 ;
     RECT  11.424 18.805 49.176 19.333 ;
     RECT  50.16 16.405 52.152 19.333 ;
     RECT  11.424 19.333 52.152 20.339 ;
     RECT  61.68 14.917 62.112 21.155 ;
     RECT  63.792 21.397 63.816 21.923 ;
     RECT  11.424 20.339 51.432 23.651 ;
     RECT  11.424 23.651 16.632 23.987 ;
     RECT  11.424 23.987 14.04 24.469 ;
     RECT  15.024 23.987 16.632 24.563 ;
     RECT  11.088 24.469 14.04 24.949 ;
     RECT  15.024 24.563 16.536 24.949 ;
     RECT  11.088 24.949 16.536 25.139 ;
     RECT  17.808 23.651 51.432 25.139 ;
     RECT  15.888 25.139 16.536 26.149 ;
     RECT  17.856 25.139 51.432 26.149 ;
     RECT  11.424 25.139 14.568 26.197 ;
     RECT  11.424 26.197 14.76 26.243 ;
     RECT  13.104 26.243 14.76 26.773 ;
     RECT  15.888 26.149 51.432 26.773 ;
     RECT  13.104 26.773 51.432 27.301 ;
     RECT  11.616 26.243 11.64 27.877 ;
     RECT  13.008 27.301 51.432 27.877 ;
     RECT  11.616 27.877 51.432 31.523 ;
     RECT  11.616 31.523 51.312 31.909 ;
     RECT  2.4 14.723 2.712 32.409 ;
     RECT  7.8 14.723 8.112 32.409 ;
     RECT  11.328 31.909 51.312 32.409 ;
     RECT  56.4 2.151 56.712 32.409 ;
     RECT  61.8 21.155 62.112 32.409 ;
     RECT  67.2 19.235 67.512 32.409 ;
     RECT  2.4 32.409 2.52 32.423 ;
     RECT  7.8 32.409 7.92 32.423 ;
     RECT  11.328 32.409 51.12 32.423 ;
     RECT  56.4 32.409 56.52 32.423 ;
     RECT  61.8 32.409 61.92 32.423 ;
     RECT  67.2 32.409 67.32 32.423 ;
     RECT  11.328 32.423 50.568 33.683 ;
     RECT  11.328 33.683 50.376 34.384 ;
     RECT  9.024 1.763 9.6 2.137 ;
     RECT  16.392 1.811 17.424 1.859 ;
     RECT  15.816 1.859 17.424 2.821 ;
     RECT  7.92 2.137 9.6 2.151 ;
     RECT  8.112 2.151 9.6 2.339 ;
     RECT  41.736 2.291 43.008 3.349 ;
     RECT  15.816 2.821 16.896 3.205 ;
     RECT  41.976 3.349 43.008 3.397 ;
     RECT  49.656 4.019 50.64 4.595 ;
     RECT  10.656 4.595 10.8 5.701 ;
     RECT  26.52 4.595 27.648 5.653 ;
     RECT  48.984 4.595 49.032 5.797 ;
     RECT  47.736 5.795 48.96 6.805 ;
     RECT  49.032 6.181 50.544 6.661 ;
     RECT  49.032 6.661 50.16 8.965 ;
     RECT  41.256 8.579 42.432 9.781 ;
     RECT  49.08 8.965 50.16 18.805 ;
     RECT  66.168 17.461 67.2 18.181 ;
     RECT  49.176 18.805 50.16 19.333 ;
     RECT  16.632 23.651 17.808 24.563 ;
     RECT  14.04 23.987 15.024 24.949 ;
     RECT  16.536 24.563 17.808 25.139 ;
     RECT  14.568 25.139 15.888 26.197 ;
     RECT  16.536 25.139 17.856 26.149 ;
     RECT  14.76 26.197 15.888 26.773 ;
     RECT  11.64 26.243 13.104 27.301 ;
     RECT  11.64 27.301 13.008 27.877 ;
  END
END ot_s81_markov_ctl_static
END LIBRARY
